VERSION 5.8 ;
BUSBITCHARS "[]" ;
DIVIDERCHAR "/" ;
UNITS
    DATABASE MICRONS 1000 ;
END UNITS

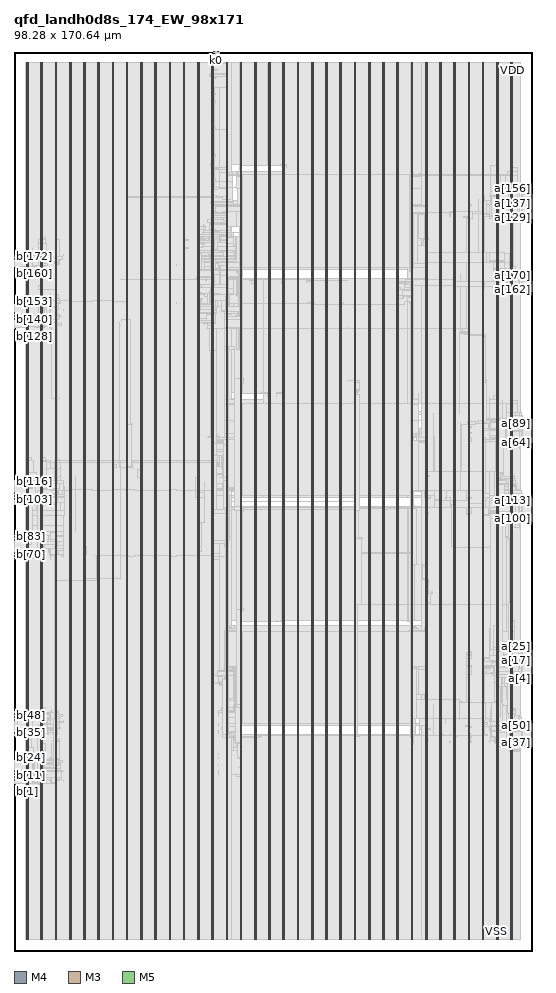
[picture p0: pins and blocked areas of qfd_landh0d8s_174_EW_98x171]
MACRO qfd_landh0d8s_174_EW_98x171
  FOREIGN qfd_landh0d8s_174_EW_98x171 0 0 ;
  CLASS BLOCK ;
  SIZE 98.28 BY 170.64 ;
  PIN a[0]
    DIRECTION INPUT ;
    USE SIGNAL ;
    PORT
      LAYER M4 ;
        RECT  98.196 52.56 98.28 52.584 ;
    END
  END a[0]
  PIN a[100]
    DIRECTION INPUT ;
    USE SIGNAL ;
    PORT
      LAYER M4 ;
        RECT  98.196 81.936 98.28 81.96 ;
    END
  END a[100]
  PIN a[101]
    DIRECTION INPUT ;
    USE SIGNAL ;
    PORT
      LAYER M4 ;
        RECT  98.196 82.08 98.28 82.104 ;
    END
  END a[101]
  PIN a[102]
    DIRECTION INPUT ;
    USE SIGNAL ;
    PORT
      LAYER M4 ;
        RECT  98.196 82.224 98.28 82.248 ;
    END
  END a[102]
  PIN a[103]
    DIRECTION INPUT ;
    USE SIGNAL ;
    PORT
      LAYER M4 ;
        RECT  98.196 82.368 98.28 82.392 ;
    END
  END a[103]
  PIN a[104]
    DIRECTION INPUT ;
    USE SIGNAL ;
    PORT
      LAYER M4 ;
        RECT  98.196 82.512 98.28 82.536 ;
    END
  END a[104]
  PIN a[105]
    DIRECTION INPUT ;
    USE SIGNAL ;
    PORT
      LAYER M4 ;
        RECT  98.196 82.656 98.28 82.68 ;
    END
  END a[105]
  PIN a[106]
    DIRECTION INPUT ;
    USE SIGNAL ;
    PORT
      LAYER M4 ;
        RECT  98.196 82.8 98.28 82.824 ;
    END
  END a[106]
  PIN a[107]
    DIRECTION INPUT ;
    USE SIGNAL ;
    PORT
      LAYER M4 ;
        RECT  98.196 82.944 98.28 82.968 ;
    END
  END a[107]
  PIN a[108]
    DIRECTION INPUT ;
    USE SIGNAL ;
    PORT
      LAYER M4 ;
        RECT  98.196 83.088 98.28 83.112 ;
    END
  END a[108]
  PIN a[109]
    DIRECTION INPUT ;
    USE SIGNAL ;
    PORT
      LAYER M4 ;
        RECT  98.196 83.232 98.28 83.256 ;
    END
  END a[109]
  PIN a[10]
    DIRECTION INPUT ;
    USE SIGNAL ;
    PORT
      LAYER M4 ;
        RECT  98.196 54 98.28 54.024 ;
    END
  END a[10]
  PIN a[110]
    DIRECTION INPUT ;
    USE SIGNAL ;
    PORT
      LAYER M4 ;
        RECT  98.196 83.376 98.28 83.4 ;
    END
  END a[110]
  PIN a[111]
    DIRECTION INPUT ;
    USE SIGNAL ;
    PORT
      LAYER M4 ;
        RECT  98.196 83.52 98.28 83.544 ;
    END
  END a[111]
  PIN a[112]
    DIRECTION INPUT ;
    USE SIGNAL ;
    PORT
      LAYER M4 ;
        RECT  98.196 83.664 98.28 83.688 ;
    END
  END a[112]
  PIN a[113]
    DIRECTION INPUT ;
    USE SIGNAL ;
    PORT
      LAYER M4 ;
        RECT  98.196 83.808 98.28 83.832 ;
    END
  END a[113]
  PIN a[114]
    DIRECTION INPUT ;
    USE SIGNAL ;
    PORT
      LAYER M4 ;
        RECT  98.196 83.952 98.28 83.976 ;
    END
  END a[114]
  PIN a[115]
    DIRECTION INPUT ;
    USE SIGNAL ;
    PORT
      LAYER M4 ;
        RECT  98.196 84.096 98.28 84.12 ;
    END
  END a[115]
  PIN a[116]
    DIRECTION INPUT ;
    USE SIGNAL ;
    PORT
      LAYER M4 ;
        RECT  98.196 84.24 98.28 84.264 ;
    END
  END a[116]
  PIN a[117]
    DIRECTION INPUT ;
    USE SIGNAL ;
    PORT
      LAYER M4 ;
        RECT  98.196 84.384 98.28 84.408 ;
    END
  END a[117]
  PIN a[118]
    DIRECTION INPUT ;
    USE SIGNAL ;
    PORT
      LAYER M4 ;
        RECT  98.196 84.528 98.28 84.552 ;
    END
  END a[118]
  PIN a[119]
    DIRECTION INPUT ;
    USE SIGNAL ;
    PORT
      LAYER M4 ;
        RECT  98.196 84.672 98.28 84.696 ;
    END
  END a[119]
  PIN a[11]
    DIRECTION INPUT ;
    USE SIGNAL ;
    PORT
      LAYER M4 ;
        RECT  98.196 54.144 98.28 54.168 ;
    END
  END a[11]
  PIN a[120]
    DIRECTION INPUT ;
    USE SIGNAL ;
    PORT
      LAYER M4 ;
        RECT  98.196 84.816 98.28 84.84 ;
    END
  END a[120]
  PIN a[121]
    DIRECTION INPUT ;
    USE SIGNAL ;
    PORT
      LAYER M4 ;
        RECT  98.196 84.96 98.28 84.984 ;
    END
  END a[121]
  PIN a[122]
    DIRECTION INPUT ;
    USE SIGNAL ;
    PORT
      LAYER M4 ;
        RECT  98.196 85.104 98.28 85.128 ;
    END
  END a[122]
  PIN a[123]
    DIRECTION INPUT ;
    USE SIGNAL ;
    PORT
      LAYER M4 ;
        RECT  98.196 85.248 98.28 85.272 ;
    END
  END a[123]
  PIN a[124]
    DIRECTION INPUT ;
    USE SIGNAL ;
    PORT
      LAYER M4 ;
        RECT  98.196 85.392 98.28 85.416 ;
    END
  END a[124]
  PIN a[125]
    DIRECTION INPUT ;
    USE SIGNAL ;
    PORT
      LAYER M4 ;
        RECT  98.196 85.536 98.28 85.56 ;
    END
  END a[125]
  PIN a[126]
    DIRECTION INPUT ;
    USE SIGNAL ;
    PORT
      LAYER M4 ;
        RECT  98.196 85.68 98.28 85.704 ;
    END
  END a[126]
  PIN a[127]
    DIRECTION INPUT ;
    USE SIGNAL ;
    PORT
      LAYER M4 ;
        RECT  98.196 85.824 98.28 85.848 ;
    END
  END a[127]
  PIN a[128]
    DIRECTION INPUT ;
    USE SIGNAL ;
    PORT
      LAYER M4 ;
        RECT  98.196 138.96 98.28 138.984 ;
    END
  END a[128]
  PIN a[129]
    DIRECTION INPUT ;
    USE SIGNAL ;
    PORT
      LAYER M4 ;
        RECT  98.196 139.104 98.28 139.128 ;
    END
  END a[129]
  PIN a[12]
    DIRECTION INPUT ;
    USE SIGNAL ;
    PORT
      LAYER M4 ;
        RECT  98.196 54.288 98.28 54.312 ;
    END
  END a[12]
  PIN a[130]
    DIRECTION INPUT ;
    USE SIGNAL ;
    PORT
      LAYER M4 ;
        RECT  98.196 139.248 98.28 139.272 ;
    END
  END a[130]
  PIN a[131]
    DIRECTION INPUT ;
    USE SIGNAL ;
    PORT
      LAYER M4 ;
        RECT  98.196 139.392 98.28 139.416 ;
    END
  END a[131]
  PIN a[132]
    DIRECTION INPUT ;
    USE SIGNAL ;
    PORT
      LAYER M4 ;
        RECT  98.196 139.536 98.28 139.56 ;
    END
  END a[132]
  PIN a[133]
    DIRECTION INPUT ;
    USE SIGNAL ;
    PORT
      LAYER M4 ;
        RECT  98.196 139.68 98.28 139.704 ;
    END
  END a[133]
  PIN a[134]
    DIRECTION INPUT ;
    USE SIGNAL ;
    PORT
      LAYER M4 ;
        RECT  98.196 139.824 98.28 139.848 ;
    END
  END a[134]
  PIN a[135]
    DIRECTION INPUT ;
    USE SIGNAL ;
    PORT
      LAYER M4 ;
        RECT  98.196 139.968 98.28 139.992 ;
    END
  END a[135]
  PIN a[136]
    DIRECTION INPUT ;
    USE SIGNAL ;
    PORT
      LAYER M4 ;
        RECT  98.196 140.112 98.28 140.136 ;
    END
  END a[136]
  PIN a[137]
    DIRECTION INPUT ;
    USE SIGNAL ;
    PORT
      LAYER M4 ;
        RECT  98.196 140.256 98.28 140.28 ;
    END
  END a[137]
  PIN a[138]
    DIRECTION INPUT ;
    USE SIGNAL ;
    PORT
      LAYER M4 ;
        RECT  98.196 140.4 98.28 140.424 ;
    END
  END a[138]
  PIN a[139]
    DIRECTION INPUT ;
    USE SIGNAL ;
    PORT
      LAYER M4 ;
        RECT  98.196 140.544 98.28 140.568 ;
    END
  END a[139]
  PIN a[13]
    DIRECTION INPUT ;
    USE SIGNAL ;
    PORT
      LAYER M4 ;
        RECT  98.196 54.432 98.28 54.456 ;
    END
  END a[13]
  PIN a[140]
    DIRECTION INPUT ;
    USE SIGNAL ;
    PORT
      LAYER M4 ;
        RECT  98.196 140.688 98.28 140.712 ;
    END
  END a[140]
  PIN a[141]
    DIRECTION INPUT ;
    USE SIGNAL ;
    PORT
      LAYER M4 ;
        RECT  98.196 140.832 98.28 140.856 ;
    END
  END a[141]
  PIN a[142]
    DIRECTION INPUT ;
    USE SIGNAL ;
    PORT
      LAYER M4 ;
        RECT  98.196 140.976 98.28 141 ;
    END
  END a[142]
  PIN a[143]
    DIRECTION INPUT ;
    USE SIGNAL ;
    PORT
      LAYER M4 ;
        RECT  98.196 141.12 98.28 141.144 ;
    END
  END a[143]
  PIN a[144]
    DIRECTION INPUT ;
    USE SIGNAL ;
    PORT
      LAYER M4 ;
        RECT  98.196 141.264 98.28 141.288 ;
    END
  END a[144]
  PIN a[145]
    DIRECTION INPUT ;
    USE SIGNAL ;
    PORT
      LAYER M4 ;
        RECT  98.196 141.408 98.28 141.432 ;
    END
  END a[145]
  PIN a[146]
    DIRECTION INPUT ;
    USE SIGNAL ;
    PORT
      LAYER M4 ;
        RECT  98.196 141.552 98.28 141.576 ;
    END
  END a[146]
  PIN a[147]
    DIRECTION INPUT ;
    USE SIGNAL ;
    PORT
      LAYER M4 ;
        RECT  98.196 141.696 98.28 141.72 ;
    END
  END a[147]
  PIN a[148]
    DIRECTION INPUT ;
    USE SIGNAL ;
    PORT
      LAYER M4 ;
        RECT  98.196 141.84 98.28 141.864 ;
    END
  END a[148]
  PIN a[149]
    DIRECTION INPUT ;
    USE SIGNAL ;
    PORT
      LAYER M4 ;
        RECT  98.196 141.984 98.28 142.008 ;
    END
  END a[149]
  PIN a[14]
    DIRECTION INPUT ;
    USE SIGNAL ;
    PORT
      LAYER M4 ;
        RECT  98.196 54.576 98.28 54.6 ;
    END
  END a[14]
  PIN a[150]
    DIRECTION INPUT ;
    USE SIGNAL ;
    PORT
      LAYER M4 ;
        RECT  98.196 142.128 98.28 142.152 ;
    END
  END a[150]
  PIN a[151]
    DIRECTION INPUT ;
    USE SIGNAL ;
    PORT
      LAYER M4 ;
        RECT  98.196 142.272 98.28 142.296 ;
    END
  END a[151]
  PIN a[152]
    DIRECTION INPUT ;
    USE SIGNAL ;
    PORT
      LAYER M4 ;
        RECT  98.196 142.416 98.28 142.44 ;
    END
  END a[152]
  PIN a[153]
    DIRECTION INPUT ;
    USE SIGNAL ;
    PORT
      LAYER M4 ;
        RECT  98.196 142.56 98.28 142.584 ;
    END
  END a[153]
  PIN a[154]
    DIRECTION INPUT ;
    USE SIGNAL ;
    PORT
      LAYER M4 ;
        RECT  98.196 142.704 98.28 142.728 ;
    END
  END a[154]
  PIN a[155]
    DIRECTION INPUT ;
    USE SIGNAL ;
    PORT
      LAYER M4 ;
        RECT  98.196 142.848 98.28 142.872 ;
    END
  END a[155]
  PIN a[156]
    DIRECTION INPUT ;
    USE SIGNAL ;
    PORT
      LAYER M4 ;
        RECT  98.196 142.992 98.28 143.016 ;
    END
  END a[156]
  PIN a[157]
    DIRECTION INPUT ;
    USE SIGNAL ;
    PORT
      LAYER M4 ;
        RECT  98.196 143.136 98.28 143.16 ;
    END
  END a[157]
  PIN a[158]
    DIRECTION INPUT ;
    USE SIGNAL ;
    PORT
      LAYER M4 ;
        RECT  98.196 143.28 98.28 143.304 ;
    END
  END a[158]
  PIN a[159]
    DIRECTION INPUT ;
    USE SIGNAL ;
    PORT
      LAYER M4 ;
        RECT  98.196 143.424 98.28 143.448 ;
    END
  END a[159]
  PIN a[15]
    DIRECTION INPUT ;
    USE SIGNAL ;
    PORT
      LAYER M4 ;
        RECT  98.196 54.72 98.28 54.744 ;
    END
  END a[15]
  PIN a[160]
    DIRECTION INPUT ;
    USE SIGNAL ;
    PORT
      LAYER M4 ;
        RECT  98.196 125.136 98.28 125.16 ;
    END
  END a[160]
  PIN a[161]
    DIRECTION INPUT ;
    USE SIGNAL ;
    PORT
      LAYER M4 ;
        RECT  98.196 125.28 98.28 125.304 ;
    END
  END a[161]
  PIN a[162]
    DIRECTION INPUT ;
    USE SIGNAL ;
    PORT
      LAYER M4 ;
        RECT  98.196 125.424 98.28 125.448 ;
    END
  END a[162]
  PIN a[163]
    DIRECTION INPUT ;
    USE SIGNAL ;
    PORT
      LAYER M4 ;
        RECT  98.196 125.568 98.28 125.592 ;
    END
  END a[163]
  PIN a[164]
    DIRECTION INPUT ;
    USE SIGNAL ;
    PORT
      LAYER M4 ;
        RECT  98.196 125.712 98.28 125.736 ;
    END
  END a[164]
  PIN a[165]
    DIRECTION INPUT ;
    USE SIGNAL ;
    PORT
      LAYER M4 ;
        RECT  98.196 125.856 98.28 125.88 ;
    END
  END a[165]
  PIN a[166]
    DIRECTION INPUT ;
    USE SIGNAL ;
    PORT
      LAYER M4 ;
        RECT  98.196 126 98.28 126.024 ;
    END
  END a[166]
  PIN a[167]
    DIRECTION INPUT ;
    USE SIGNAL ;
    PORT
      LAYER M4 ;
        RECT  98.196 126.144 98.28 126.168 ;
    END
  END a[167]
  PIN a[168]
    DIRECTION INPUT ;
    USE SIGNAL ;
    PORT
      LAYER M4 ;
        RECT  98.196 126.288 98.28 126.312 ;
    END
  END a[168]
  PIN a[169]
    DIRECTION INPUT ;
    USE SIGNAL ;
    PORT
      LAYER M4 ;
        RECT  98.196 126.432 98.28 126.456 ;
    END
  END a[169]
  PIN a[16]
    DIRECTION INPUT ;
    USE SIGNAL ;
    PORT
      LAYER M4 ;
        RECT  98.196 54.864 98.28 54.888 ;
    END
  END a[16]
  PIN a[170]
    DIRECTION INPUT ;
    USE SIGNAL ;
    PORT
      LAYER M4 ;
        RECT  98.196 126.576 98.28 126.6 ;
    END
  END a[170]
  PIN a[171]
    DIRECTION INPUT ;
    USE SIGNAL ;
    PORT
      LAYER M4 ;
        RECT  98.196 126.72 98.28 126.744 ;
    END
  END a[171]
  PIN a[172]
    DIRECTION INPUT ;
    USE SIGNAL ;
    PORT
      LAYER M4 ;
        RECT  98.196 126.864 98.28 126.888 ;
    END
  END a[172]
  PIN a[173]
    DIRECTION INPUT ;
    USE SIGNAL ;
    PORT
      LAYER M4 ;
        RECT  98.196 127.008 98.28 127.032 ;
    END
  END a[173]
  PIN a[17]
    DIRECTION INPUT ;
    USE SIGNAL ;
    PORT
      LAYER M4 ;
        RECT  98.196 55.008 98.28 55.032 ;
    END
  END a[17]
  PIN a[18]
    DIRECTION INPUT ;
    USE SIGNAL ;
    PORT
      LAYER M4 ;
        RECT  98.196 55.152 98.28 55.176 ;
    END
  END a[18]
  PIN a[19]
    DIRECTION INPUT ;
    USE SIGNAL ;
    PORT
      LAYER M4 ;
        RECT  98.196 55.296 98.28 55.32 ;
    END
  END a[19]
  PIN a[1]
    DIRECTION INPUT ;
    USE SIGNAL ;
    PORT
      LAYER M4 ;
        RECT  98.196 52.704 98.28 52.728 ;
    END
  END a[1]
  PIN a[20]
    DIRECTION INPUT ;
    USE SIGNAL ;
    PORT
      LAYER M4 ;
        RECT  98.196 55.44 98.28 55.464 ;
    END
  END a[20]
  PIN a[21]
    DIRECTION INPUT ;
    USE SIGNAL ;
    PORT
      LAYER M4 ;
        RECT  98.196 55.584 98.28 55.608 ;
    END
  END a[21]
  PIN a[22]
    DIRECTION INPUT ;
    USE SIGNAL ;
    PORT
      LAYER M4 ;
        RECT  98.196 55.728 98.28 55.752 ;
    END
  END a[22]
  PIN a[23]
    DIRECTION INPUT ;
    USE SIGNAL ;
    PORT
      LAYER M4 ;
        RECT  98.196 55.872 98.28 55.896 ;
    END
  END a[23]
  PIN a[24]
    DIRECTION INPUT ;
    USE SIGNAL ;
    PORT
      LAYER M4 ;
        RECT  98.196 56.016 98.28 56.04 ;
    END
  END a[24]
  PIN a[25]
    DIRECTION INPUT ;
    USE SIGNAL ;
    PORT
      LAYER M4 ;
        RECT  98.196 56.16 98.28 56.184 ;
    END
  END a[25]
  PIN a[26]
    DIRECTION INPUT ;
    USE SIGNAL ;
    PORT
      LAYER M4 ;
        RECT  98.196 56.304 98.28 56.328 ;
    END
  END a[26]
  PIN a[27]
    DIRECTION INPUT ;
    USE SIGNAL ;
    PORT
      LAYER M4 ;
        RECT  98.196 56.448 98.28 56.472 ;
    END
  END a[27]
  PIN a[28]
    DIRECTION INPUT ;
    USE SIGNAL ;
    PORT
      LAYER M4 ;
        RECT  98.196 56.592 98.28 56.616 ;
    END
  END a[28]
  PIN a[29]
    DIRECTION INPUT ;
    USE SIGNAL ;
    PORT
      LAYER M4 ;
        RECT  98.196 56.736 98.28 56.76 ;
    END
  END a[29]
  PIN a[2]
    DIRECTION INPUT ;
    USE SIGNAL ;
    PORT
      LAYER M4 ;
        RECT  98.196 52.848 98.28 52.872 ;
    END
  END a[2]
  PIN a[30]
    DIRECTION INPUT ;
    USE SIGNAL ;
    PORT
      LAYER M4 ;
        RECT  98.196 56.88 98.28 56.904 ;
    END
  END a[30]
  PIN a[31]
    DIRECTION INPUT ;
    USE SIGNAL ;
    PORT
      LAYER M4 ;
        RECT  98.196 57.024 98.28 57.048 ;
    END
  END a[31]
  PIN a[32]
    DIRECTION INPUT ;
    USE SIGNAL ;
    PORT
      LAYER M4 ;
        RECT  98.196 38.736 98.28 38.76 ;
    END
  END a[32]
  PIN a[33]
    DIRECTION INPUT ;
    USE SIGNAL ;
    PORT
      LAYER M4 ;
        RECT  98.196 38.88 98.28 38.904 ;
    END
  END a[33]
  PIN a[34]
    DIRECTION INPUT ;
    USE SIGNAL ;
    PORT
      LAYER M4 ;
        RECT  98.196 39.024 98.28 39.048 ;
    END
  END a[34]
  PIN a[35]
    DIRECTION INPUT ;
    USE SIGNAL ;
    PORT
      LAYER M4 ;
        RECT  98.196 39.168 98.28 39.192 ;
    END
  END a[35]
  PIN a[36]
    DIRECTION INPUT ;
    USE SIGNAL ;
    PORT
      LAYER M4 ;
        RECT  98.196 39.312 98.28 39.336 ;
    END
  END a[36]
  PIN a[37]
    DIRECTION INPUT ;
    USE SIGNAL ;
    PORT
      LAYER M4 ;
        RECT  98.196 39.456 98.28 39.48 ;
    END
  END a[37]
  PIN a[38]
    DIRECTION INPUT ;
    USE SIGNAL ;
    PORT
      LAYER M4 ;
        RECT  98.196 39.6 98.28 39.624 ;
    END
  END a[38]
  PIN a[39]
    DIRECTION INPUT ;
    USE SIGNAL ;
    PORT
      LAYER M4 ;
        RECT  98.196 39.744 98.28 39.768 ;
    END
  END a[39]
  PIN a[3]
    DIRECTION INPUT ;
    USE SIGNAL ;
    PORT
      LAYER M4 ;
        RECT  98.196 52.992 98.28 53.016 ;
    END
  END a[3]
  PIN a[40]
    DIRECTION INPUT ;
    USE SIGNAL ;
    PORT
      LAYER M4 ;
        RECT  98.196 39.888 98.28 39.912 ;
    END
  END a[40]
  PIN a[41]
    DIRECTION INPUT ;
    USE SIGNAL ;
    PORT
      LAYER M4 ;
        RECT  98.196 40.032 98.28 40.056 ;
    END
  END a[41]
  PIN a[42]
    DIRECTION INPUT ;
    USE SIGNAL ;
    PORT
      LAYER M4 ;
        RECT  98.196 40.176 98.28 40.2 ;
    END
  END a[42]
  PIN a[43]
    DIRECTION INPUT ;
    USE SIGNAL ;
    PORT
      LAYER M4 ;
        RECT  98.196 40.32 98.28 40.344 ;
    END
  END a[43]
  PIN a[44]
    DIRECTION INPUT ;
    USE SIGNAL ;
    PORT
      LAYER M4 ;
        RECT  98.196 40.464 98.28 40.488 ;
    END
  END a[44]
  PIN a[45]
    DIRECTION INPUT ;
    USE SIGNAL ;
    PORT
      LAYER M4 ;
        RECT  98.196 40.608 98.28 40.632 ;
    END
  END a[45]
  PIN a[46]
    DIRECTION INPUT ;
    USE SIGNAL ;
    PORT
      LAYER M4 ;
        RECT  98.196 40.752 98.28 40.776 ;
    END
  END a[46]
  PIN a[47]
    DIRECTION INPUT ;
    USE SIGNAL ;
    PORT
      LAYER M4 ;
        RECT  98.196 40.896 98.28 40.92 ;
    END
  END a[47]
  PIN a[48]
    DIRECTION INPUT ;
    USE SIGNAL ;
    PORT
      LAYER M4 ;
        RECT  98.196 41.04 98.28 41.064 ;
    END
  END a[48]
  PIN a[49]
    DIRECTION INPUT ;
    USE SIGNAL ;
    PORT
      LAYER M4 ;
        RECT  98.196 41.184 98.28 41.208 ;
    END
  END a[49]
  PIN a[4]
    DIRECTION INPUT ;
    USE SIGNAL ;
    PORT
      LAYER M4 ;
        RECT  98.196 53.136 98.28 53.16 ;
    END
  END a[4]
  PIN a[50]
    DIRECTION INPUT ;
    USE SIGNAL ;
    PORT
      LAYER M4 ;
        RECT  98.196 41.328 98.28 41.352 ;
    END
  END a[50]
  PIN a[51]
    DIRECTION INPUT ;
    USE SIGNAL ;
    PORT
      LAYER M4 ;
        RECT  98.196 41.472 98.28 41.496 ;
    END
  END a[51]
  PIN a[52]
    DIRECTION INPUT ;
    USE SIGNAL ;
    PORT
      LAYER M4 ;
        RECT  98.196 41.616 98.28 41.64 ;
    END
  END a[52]
  PIN a[53]
    DIRECTION INPUT ;
    USE SIGNAL ;
    PORT
      LAYER M4 ;
        RECT  98.196 41.76 98.28 41.784 ;
    END
  END a[53]
  PIN a[54]
    DIRECTION INPUT ;
    USE SIGNAL ;
    PORT
      LAYER M4 ;
        RECT  98.196 41.904 98.28 41.928 ;
    END
  END a[54]
  PIN a[55]
    DIRECTION INPUT ;
    USE SIGNAL ;
    PORT
      LAYER M4 ;
        RECT  98.196 42.048 98.28 42.072 ;
    END
  END a[55]
  PIN a[56]
    DIRECTION INPUT ;
    USE SIGNAL ;
    PORT
      LAYER M4 ;
        RECT  98.196 42.192 98.28 42.216 ;
    END
  END a[56]
  PIN a[57]
    DIRECTION INPUT ;
    USE SIGNAL ;
    PORT
      LAYER M4 ;
        RECT  98.196 42.336 98.28 42.36 ;
    END
  END a[57]
  PIN a[58]
    DIRECTION INPUT ;
    USE SIGNAL ;
    PORT
      LAYER M4 ;
        RECT  98.196 42.48 98.28 42.504 ;
    END
  END a[58]
  PIN a[59]
    DIRECTION INPUT ;
    USE SIGNAL ;
    PORT
      LAYER M4 ;
        RECT  98.196 42.624 98.28 42.648 ;
    END
  END a[59]
  PIN a[5]
    DIRECTION INPUT ;
    USE SIGNAL ;
    PORT
      LAYER M4 ;
        RECT  98.196 53.28 98.28 53.304 ;
    END
  END a[5]
  PIN a[60]
    DIRECTION INPUT ;
    USE SIGNAL ;
    PORT
      LAYER M4 ;
        RECT  98.196 42.768 98.28 42.792 ;
    END
  END a[60]
  PIN a[61]
    DIRECTION INPUT ;
    USE SIGNAL ;
    PORT
      LAYER M4 ;
        RECT  98.196 42.912 98.28 42.936 ;
    END
  END a[61]
  PIN a[62]
    DIRECTION INPUT ;
    USE SIGNAL ;
    PORT
      LAYER M4 ;
        RECT  98.196 43.056 98.28 43.08 ;
    END
  END a[62]
  PIN a[63]
    DIRECTION INPUT ;
    USE SIGNAL ;
    PORT
      LAYER M4 ;
        RECT  98.196 43.2 98.28 43.224 ;
    END
  END a[63]
  PIN a[64]
    DIRECTION INPUT ;
    USE SIGNAL ;
    PORT
      LAYER M4 ;
        RECT  98.196 96.336 98.28 96.36 ;
    END
  END a[64]
  PIN a[65]
    DIRECTION INPUT ;
    USE SIGNAL ;
    PORT
      LAYER M4 ;
        RECT  98.196 96.48 98.28 96.504 ;
    END
  END a[65]
  PIN a[66]
    DIRECTION INPUT ;
    USE SIGNAL ;
    PORT
      LAYER M4 ;
        RECT  98.196 96.624 98.28 96.648 ;
    END
  END a[66]
  PIN a[67]
    DIRECTION INPUT ;
    USE SIGNAL ;
    PORT
      LAYER M4 ;
        RECT  98.196 96.768 98.28 96.792 ;
    END
  END a[67]
  PIN a[68]
    DIRECTION INPUT ;
    USE SIGNAL ;
    PORT
      LAYER M4 ;
        RECT  98.196 96.912 98.28 96.936 ;
    END
  END a[68]
  PIN a[69]
    DIRECTION INPUT ;
    USE SIGNAL ;
    PORT
      LAYER M4 ;
        RECT  98.196 97.056 98.28 97.08 ;
    END
  END a[69]
  PIN a[6]
    DIRECTION INPUT ;
    USE SIGNAL ;
    PORT
      LAYER M4 ;
        RECT  98.196 53.424 98.28 53.448 ;
    END
  END a[6]
  PIN a[70]
    DIRECTION INPUT ;
    USE SIGNAL ;
    PORT
      LAYER M4 ;
        RECT  98.196 97.2 98.28 97.224 ;
    END
  END a[70]
  PIN a[71]
    DIRECTION INPUT ;
    USE SIGNAL ;
    PORT
      LAYER M4 ;
        RECT  98.196 97.344 98.28 97.368 ;
    END
  END a[71]
  PIN a[72]
    DIRECTION INPUT ;
    USE SIGNAL ;
    PORT
      LAYER M4 ;
        RECT  98.196 97.488 98.28 97.512 ;
    END
  END a[72]
  PIN a[73]
    DIRECTION INPUT ;
    USE SIGNAL ;
    PORT
      LAYER M4 ;
        RECT  98.196 97.632 98.28 97.656 ;
    END
  END a[73]
  PIN a[74]
    DIRECTION INPUT ;
    USE SIGNAL ;
    PORT
      LAYER M4 ;
        RECT  98.196 97.776 98.28 97.8 ;
    END
  END a[74]
  PIN a[75]
    DIRECTION INPUT ;
    USE SIGNAL ;
    PORT
      LAYER M4 ;
        RECT  98.196 97.92 98.28 97.944 ;
    END
  END a[75]
  PIN a[76]
    DIRECTION INPUT ;
    USE SIGNAL ;
    PORT
      LAYER M4 ;
        RECT  98.196 98.064 98.28 98.088 ;
    END
  END a[76]
  PIN a[77]
    DIRECTION INPUT ;
    USE SIGNAL ;
    PORT
      LAYER M4 ;
        RECT  98.196 98.208 98.28 98.232 ;
    END
  END a[77]
  PIN a[78]
    DIRECTION INPUT ;
    USE SIGNAL ;
    PORT
      LAYER M4 ;
        RECT  98.196 98.352 98.28 98.376 ;
    END
  END a[78]
  PIN a[79]
    DIRECTION INPUT ;
    USE SIGNAL ;
    PORT
      LAYER M4 ;
        RECT  98.196 98.496 98.28 98.52 ;
    END
  END a[79]
  PIN a[7]
    DIRECTION INPUT ;
    USE SIGNAL ;
    PORT
      LAYER M4 ;
        RECT  98.196 53.568 98.28 53.592 ;
    END
  END a[7]
  PIN a[80]
    DIRECTION INPUT ;
    USE SIGNAL ;
    PORT
      LAYER M4 ;
        RECT  98.196 98.64 98.28 98.664 ;
    END
  END a[80]
  PIN a[81]
    DIRECTION INPUT ;
    USE SIGNAL ;
    PORT
      LAYER M4 ;
        RECT  98.196 98.784 98.28 98.808 ;
    END
  END a[81]
  PIN a[82]
    DIRECTION INPUT ;
    USE SIGNAL ;
    PORT
      LAYER M4 ;
        RECT  98.196 98.928 98.28 98.952 ;
    END
  END a[82]
  PIN a[83]
    DIRECTION INPUT ;
    USE SIGNAL ;
    PORT
      LAYER M4 ;
        RECT  98.196 99.072 98.28 99.096 ;
    END
  END a[83]
  PIN a[84]
    DIRECTION INPUT ;
    USE SIGNAL ;
    PORT
      LAYER M4 ;
        RECT  98.196 99.216 98.28 99.24 ;
    END
  END a[84]
  PIN a[85]
    DIRECTION INPUT ;
    USE SIGNAL ;
    PORT
      LAYER M4 ;
        RECT  98.196 99.36 98.28 99.384 ;
    END
  END a[85]
  PIN a[86]
    DIRECTION INPUT ;
    USE SIGNAL ;
    PORT
      LAYER M4 ;
        RECT  98.196 99.504 98.28 99.528 ;
    END
  END a[86]
  PIN a[87]
    DIRECTION INPUT ;
    USE SIGNAL ;
    PORT
      LAYER M4 ;
        RECT  98.196 99.648 98.28 99.672 ;
    END
  END a[87]
  PIN a[88]
    DIRECTION INPUT ;
    USE SIGNAL ;
    PORT
      LAYER M4 ;
        RECT  98.196 99.792 98.28 99.816 ;
    END
  END a[88]
  PIN a[89]
    DIRECTION INPUT ;
    USE SIGNAL ;
    PORT
      LAYER M4 ;
        RECT  98.196 99.936 98.28 99.96 ;
    END
  END a[89]
  PIN a[8]
    DIRECTION INPUT ;
    USE SIGNAL ;
    PORT
      LAYER M4 ;
        RECT  98.196 53.712 98.28 53.736 ;
    END
  END a[8]
  PIN a[90]
    DIRECTION INPUT ;
    USE SIGNAL ;
    PORT
      LAYER M4 ;
        RECT  98.196 100.08 98.28 100.104 ;
    END
  END a[90]
  PIN a[91]
    DIRECTION INPUT ;
    USE SIGNAL ;
    PORT
      LAYER M4 ;
        RECT  98.196 100.224 98.28 100.248 ;
    END
  END a[91]
  PIN a[92]
    DIRECTION INPUT ;
    USE SIGNAL ;
    PORT
      LAYER M4 ;
        RECT  98.196 100.368 98.28 100.392 ;
    END
  END a[92]
  PIN a[93]
    DIRECTION INPUT ;
    USE SIGNAL ;
    PORT
      LAYER M4 ;
        RECT  98.196 100.512 98.28 100.536 ;
    END
  END a[93]
  PIN a[94]
    DIRECTION INPUT ;
    USE SIGNAL ;
    PORT
      LAYER M4 ;
        RECT  98.196 100.656 98.28 100.68 ;
    END
  END a[94]
  PIN a[95]
    DIRECTION INPUT ;
    USE SIGNAL ;
    PORT
      LAYER M4 ;
        RECT  98.196 100.8 98.28 100.824 ;
    END
  END a[95]
  PIN a[96]
    DIRECTION INPUT ;
    USE SIGNAL ;
    PORT
      LAYER M4 ;
        RECT  98.196 81.36 98.28 81.384 ;
    END
  END a[96]
  PIN a[97]
    DIRECTION INPUT ;
    USE SIGNAL ;
    PORT
      LAYER M4 ;
        RECT  98.196 81.504 98.28 81.528 ;
    END
  END a[97]
  PIN a[98]
    DIRECTION INPUT ;
    USE SIGNAL ;
    PORT
      LAYER M4 ;
        RECT  98.196 81.648 98.28 81.672 ;
    END
  END a[98]
  PIN a[99]
    DIRECTION INPUT ;
    USE SIGNAL ;
    PORT
      LAYER M4 ;
        RECT  98.196 81.792 98.28 81.816 ;
    END
  END a[99]
  PIN a[9]
    DIRECTION INPUT ;
    USE SIGNAL ;
    PORT
      LAYER M4 ;
        RECT  98.196 53.856 98.28 53.88 ;
    END
  END a[9]
  PIN b[0]
    DIRECTION OUTPUT ;
    USE SIGNAL ;
    PORT
      LAYER M4 ;
        RECT  0 31.68 0.084 31.704 ;
    END
  END b[0]
  PIN b[100]
    DIRECTION OUTPUT ;
    USE SIGNAL ;
    PORT
      LAYER M4 ;
        RECT  0 85.248 0.084 85.272 ;
    END
  END b[100]
  PIN b[101]
    DIRECTION OUTPUT ;
    USE SIGNAL ;
    PORT
      LAYER M4 ;
        RECT  0 85.392 0.084 85.416 ;
    END
  END b[101]
  PIN b[102]
    DIRECTION OUTPUT ;
    USE SIGNAL ;
    PORT
      LAYER M4 ;
        RECT  0 85.536 0.084 85.56 ;
    END
  END b[102]
  PIN b[103]
    DIRECTION OUTPUT ;
    USE SIGNAL ;
    PORT
      LAYER M4 ;
        RECT  0 85.68 0.084 85.704 ;
    END
  END b[103]
  PIN b[104]
    DIRECTION OUTPUT ;
    USE SIGNAL ;
    PORT
      LAYER M4 ;
        RECT  0 85.824 0.084 85.848 ;
    END
  END b[104]
  PIN b[105]
    DIRECTION OUTPUT ;
    USE SIGNAL ;
    PORT
      LAYER M4 ;
        RECT  0 85.968 0.084 85.992 ;
    END
  END b[105]
  PIN b[106]
    DIRECTION OUTPUT ;
    USE SIGNAL ;
    PORT
      LAYER M4 ;
        RECT  0 86.112 0.084 86.136 ;
    END
  END b[106]
  PIN b[107]
    DIRECTION OUTPUT ;
    USE SIGNAL ;
    PORT
      LAYER M4 ;
        RECT  0 86.256 0.084 86.28 ;
    END
  END b[107]
  PIN b[108]
    DIRECTION OUTPUT ;
    USE SIGNAL ;
    PORT
      LAYER M4 ;
        RECT  0 86.4 0.084 86.424 ;
    END
  END b[108]
  PIN b[109]
    DIRECTION OUTPUT ;
    USE SIGNAL ;
    PORT
      LAYER M4 ;
        RECT  0 86.544 0.084 86.568 ;
    END
  END b[109]
  PIN b[10]
    DIRECTION OUTPUT ;
    USE SIGNAL ;
    PORT
      LAYER M4 ;
        RECT  0 33.12 0.084 33.144 ;
    END
  END b[10]
  PIN b[110]
    DIRECTION OUTPUT ;
    USE SIGNAL ;
    PORT
      LAYER M4 ;
        RECT  0 86.688 0.084 86.712 ;
    END
  END b[110]
  PIN b[111]
    DIRECTION OUTPUT ;
    USE SIGNAL ;
    PORT
      LAYER M4 ;
        RECT  0 86.832 0.084 86.856 ;
    END
  END b[111]
  PIN b[112]
    DIRECTION OUTPUT ;
    USE SIGNAL ;
    PORT
      LAYER M4 ;
        RECT  0 86.976 0.084 87 ;
    END
  END b[112]
  PIN b[113]
    DIRECTION OUTPUT ;
    USE SIGNAL ;
    PORT
      LAYER M4 ;
        RECT  0 87.12 0.084 87.144 ;
    END
  END b[113]
  PIN b[114]
    DIRECTION OUTPUT ;
    USE SIGNAL ;
    PORT
      LAYER M4 ;
        RECT  0 87.264 0.084 87.288 ;
    END
  END b[114]
  PIN b[115]
    DIRECTION OUTPUT ;
    USE SIGNAL ;
    PORT
      LAYER M4 ;
        RECT  0 87.408 0.084 87.432 ;
    END
  END b[115]
  PIN b[116]
    DIRECTION OUTPUT ;
    USE SIGNAL ;
    PORT
      LAYER M4 ;
        RECT  0 87.552 0.084 87.576 ;
    END
  END b[116]
  PIN b[117]
    DIRECTION OUTPUT ;
    USE SIGNAL ;
    PORT
      LAYER M4 ;
        RECT  0 87.696 0.084 87.72 ;
    END
  END b[117]
  PIN b[118]
    DIRECTION OUTPUT ;
    USE SIGNAL ;
    PORT
      LAYER M4 ;
        RECT  0 87.84 0.084 87.864 ;
    END
  END b[118]
  PIN b[119]
    DIRECTION OUTPUT ;
    USE SIGNAL ;
    PORT
      LAYER M4 ;
        RECT  0 87.984 0.084 88.008 ;
    END
  END b[119]
  PIN b[11]
    DIRECTION OUTPUT ;
    USE SIGNAL ;
    PORT
      LAYER M4 ;
        RECT  0 33.264 0.084 33.288 ;
    END
  END b[11]
  PIN b[120]
    DIRECTION OUTPUT ;
    USE SIGNAL ;
    PORT
      LAYER M4 ;
        RECT  0 88.128 0.084 88.152 ;
    END
  END b[120]
  PIN b[121]
    DIRECTION OUTPUT ;
    USE SIGNAL ;
    PORT
      LAYER M4 ;
        RECT  0 88.272 0.084 88.296 ;
    END
  END b[121]
  PIN b[122]
    DIRECTION OUTPUT ;
    USE SIGNAL ;
    PORT
      LAYER M4 ;
        RECT  0 88.416 0.084 88.44 ;
    END
  END b[122]
  PIN b[123]
    DIRECTION OUTPUT ;
    USE SIGNAL ;
    PORT
      LAYER M4 ;
        RECT  0 88.56 0.084 88.584 ;
    END
  END b[123]
  PIN b[124]
    DIRECTION OUTPUT ;
    USE SIGNAL ;
    PORT
      LAYER M4 ;
        RECT  0 88.704 0.084 88.728 ;
    END
  END b[124]
  PIN b[125]
    DIRECTION OUTPUT ;
    USE SIGNAL ;
    PORT
      LAYER M4 ;
        RECT  0 88.848 0.084 88.872 ;
    END
  END b[125]
  PIN b[126]
    DIRECTION OUTPUT ;
    USE SIGNAL ;
    PORT
      LAYER M4 ;
        RECT  0 88.992 0.084 89.016 ;
    END
  END b[126]
  PIN b[127]
    DIRECTION OUTPUT ;
    USE SIGNAL ;
    PORT
      LAYER M4 ;
        RECT  0 89.136 0.084 89.16 ;
    END
  END b[127]
  PIN b[128]
    DIRECTION OUTPUT ;
    USE SIGNAL ;
    PORT
      LAYER M4 ;
        RECT  0 118.08 0.084 118.104 ;
    END
  END b[128]
  PIN b[129]
    DIRECTION OUTPUT ;
    USE SIGNAL ;
    PORT
      LAYER M4 ;
        RECT  0 118.224 0.084 118.248 ;
    END
  END b[129]
  PIN b[12]
    DIRECTION OUTPUT ;
    USE SIGNAL ;
    PORT
      LAYER M4 ;
        RECT  0 33.408 0.084 33.432 ;
    END
  END b[12]
  PIN b[130]
    DIRECTION OUTPUT ;
    USE SIGNAL ;
    PORT
      LAYER M4 ;
        RECT  0 118.368 0.084 118.392 ;
    END
  END b[130]
  PIN b[131]
    DIRECTION OUTPUT ;
    USE SIGNAL ;
    PORT
      LAYER M4 ;
        RECT  0 118.512 0.084 118.536 ;
    END
  END b[131]
  PIN b[132]
    DIRECTION OUTPUT ;
    USE SIGNAL ;
    PORT
      LAYER M4 ;
        RECT  0 118.656 0.084 118.68 ;
    END
  END b[132]
  PIN b[133]
    DIRECTION OUTPUT ;
    USE SIGNAL ;
    PORT
      LAYER M4 ;
        RECT  0 118.8 0.084 118.824 ;
    END
  END b[133]
  PIN b[134]
    DIRECTION OUTPUT ;
    USE SIGNAL ;
    PORT
      LAYER M4 ;
        RECT  0 118.944 0.084 118.968 ;
    END
  END b[134]
  PIN b[135]
    DIRECTION OUTPUT ;
    USE SIGNAL ;
    PORT
      LAYER M4 ;
        RECT  0 119.088 0.084 119.112 ;
    END
  END b[135]
  PIN b[136]
    DIRECTION OUTPUT ;
    USE SIGNAL ;
    PORT
      LAYER M4 ;
        RECT  0 119.232 0.084 119.256 ;
    END
  END b[136]
  PIN b[137]
    DIRECTION OUTPUT ;
    USE SIGNAL ;
    PORT
      LAYER M4 ;
        RECT  0 119.376 0.084 119.4 ;
    END
  END b[137]
  PIN b[138]
    DIRECTION OUTPUT ;
    USE SIGNAL ;
    PORT
      LAYER M4 ;
        RECT  0 119.52 0.084 119.544 ;
    END
  END b[138]
  PIN b[139]
    DIRECTION OUTPUT ;
    USE SIGNAL ;
    PORT
      LAYER M4 ;
        RECT  0 119.664 0.084 119.688 ;
    END
  END b[139]
  PIN b[13]
    DIRECTION OUTPUT ;
    USE SIGNAL ;
    PORT
      LAYER M4 ;
        RECT  0 33.552 0.084 33.576 ;
    END
  END b[13]
  PIN b[140]
    DIRECTION OUTPUT ;
    USE SIGNAL ;
    PORT
      LAYER M4 ;
        RECT  0 119.808 0.084 119.832 ;
    END
  END b[140]
  PIN b[141]
    DIRECTION OUTPUT ;
    USE SIGNAL ;
    PORT
      LAYER M4 ;
        RECT  0 119.952 0.084 119.976 ;
    END
  END b[141]
  PIN b[142]
    DIRECTION OUTPUT ;
    USE SIGNAL ;
    PORT
      LAYER M4 ;
        RECT  0 120.096 0.084 120.12 ;
    END
  END b[142]
  PIN b[143]
    DIRECTION OUTPUT ;
    USE SIGNAL ;
    PORT
      LAYER M4 ;
        RECT  0 120.24 0.084 120.264 ;
    END
  END b[143]
  PIN b[144]
    DIRECTION OUTPUT ;
    USE SIGNAL ;
    PORT
      LAYER M4 ;
        RECT  0 120.384 0.084 120.408 ;
    END
  END b[144]
  PIN b[145]
    DIRECTION OUTPUT ;
    USE SIGNAL ;
    PORT
      LAYER M4 ;
        RECT  0 120.528 0.084 120.552 ;
    END
  END b[145]
  PIN b[146]
    DIRECTION OUTPUT ;
    USE SIGNAL ;
    PORT
      LAYER M4 ;
        RECT  0 120.672 0.084 120.696 ;
    END
  END b[146]
  PIN b[147]
    DIRECTION OUTPUT ;
    USE SIGNAL ;
    PORT
      LAYER M4 ;
        RECT  0 120.816 0.084 120.84 ;
    END
  END b[147]
  PIN b[148]
    DIRECTION OUTPUT ;
    USE SIGNAL ;
    PORT
      LAYER M4 ;
        RECT  0 120.96 0.084 120.984 ;
    END
  END b[148]
  PIN b[149]
    DIRECTION OUTPUT ;
    USE SIGNAL ;
    PORT
      LAYER M4 ;
        RECT  0 121.104 0.084 121.128 ;
    END
  END b[149]
  PIN b[14]
    DIRECTION OUTPUT ;
    USE SIGNAL ;
    PORT
      LAYER M4 ;
        RECT  0 33.696 0.084 33.72 ;
    END
  END b[14]
  PIN b[150]
    DIRECTION OUTPUT ;
    USE SIGNAL ;
    PORT
      LAYER M4 ;
        RECT  0 121.248 0.084 121.272 ;
    END
  END b[150]
  PIN b[151]
    DIRECTION OUTPUT ;
    USE SIGNAL ;
    PORT
      LAYER M4 ;
        RECT  0 121.392 0.084 121.416 ;
    END
  END b[151]
  PIN b[152]
    DIRECTION OUTPUT ;
    USE SIGNAL ;
    PORT
      LAYER M4 ;
        RECT  0 121.536 0.084 121.56 ;
    END
  END b[152]
  PIN b[153]
    DIRECTION OUTPUT ;
    USE SIGNAL ;
    PORT
      LAYER M4 ;
        RECT  0 121.68 0.084 121.704 ;
    END
  END b[153]
  PIN b[154]
    DIRECTION OUTPUT ;
    USE SIGNAL ;
    PORT
      LAYER M4 ;
        RECT  0 121.824 0.084 121.848 ;
    END
  END b[154]
  PIN b[155]
    DIRECTION OUTPUT ;
    USE SIGNAL ;
    PORT
      LAYER M4 ;
        RECT  0 121.968 0.084 121.992 ;
    END
  END b[155]
  PIN b[156]
    DIRECTION OUTPUT ;
    USE SIGNAL ;
    PORT
      LAYER M4 ;
        RECT  0 122.112 0.084 122.136 ;
    END
  END b[156]
  PIN b[157]
    DIRECTION OUTPUT ;
    USE SIGNAL ;
    PORT
      LAYER M4 ;
        RECT  0 122.256 0.084 122.28 ;
    END
  END b[157]
  PIN b[158]
    DIRECTION OUTPUT ;
    USE SIGNAL ;
    PORT
      LAYER M4 ;
        RECT  0 122.4 0.084 122.424 ;
    END
  END b[158]
  PIN b[159]
    DIRECTION OUTPUT ;
    USE SIGNAL ;
    PORT
      LAYER M4 ;
        RECT  0 122.544 0.084 122.568 ;
    END
  END b[159]
  PIN b[15]
    DIRECTION OUTPUT ;
    USE SIGNAL ;
    PORT
      LAYER M4 ;
        RECT  0 33.84 0.084 33.864 ;
    END
  END b[15]
  PIN b[160]
    DIRECTION OUTPUT ;
    USE SIGNAL ;
    PORT
      LAYER M4 ;
        RECT  0 129.888 0.084 129.912 ;
    END
  END b[160]
  PIN b[161]
    DIRECTION OUTPUT ;
    USE SIGNAL ;
    PORT
      LAYER M4 ;
        RECT  0 130.032 0.084 130.056 ;
    END
  END b[161]
  PIN b[162]
    DIRECTION OUTPUT ;
    USE SIGNAL ;
    PORT
      LAYER M4 ;
        RECT  0 130.176 0.084 130.2 ;
    END
  END b[162]
  PIN b[163]
    DIRECTION OUTPUT ;
    USE SIGNAL ;
    PORT
      LAYER M4 ;
        RECT  0 130.32 0.084 130.344 ;
    END
  END b[163]
  PIN b[164]
    DIRECTION OUTPUT ;
    USE SIGNAL ;
    PORT
      LAYER M4 ;
        RECT  0 130.464 0.084 130.488 ;
    END
  END b[164]
  PIN b[165]
    DIRECTION OUTPUT ;
    USE SIGNAL ;
    PORT
      LAYER M4 ;
        RECT  0 130.608 0.084 130.632 ;
    END
  END b[165]
  PIN b[166]
    DIRECTION OUTPUT ;
    USE SIGNAL ;
    PORT
      LAYER M4 ;
        RECT  0 130.752 0.084 130.776 ;
    END
  END b[166]
  PIN b[167]
    DIRECTION OUTPUT ;
    USE SIGNAL ;
    PORT
      LAYER M4 ;
        RECT  0 130.896 0.084 130.92 ;
    END
  END b[167]
  PIN b[168]
    DIRECTION OUTPUT ;
    USE SIGNAL ;
    PORT
      LAYER M4 ;
        RECT  0 131.04 0.084 131.064 ;
    END
  END b[168]
  PIN b[169]
    DIRECTION OUTPUT ;
    USE SIGNAL ;
    PORT
      LAYER M4 ;
        RECT  0 131.184 0.084 131.208 ;
    END
  END b[169]
  PIN b[16]
    DIRECTION OUTPUT ;
    USE SIGNAL ;
    PORT
      LAYER M4 ;
        RECT  0 33.984 0.084 34.008 ;
    END
  END b[16]
  PIN b[170]
    DIRECTION OUTPUT ;
    USE SIGNAL ;
    PORT
      LAYER M4 ;
        RECT  0 131.328 0.084 131.352 ;
    END
  END b[170]
  PIN b[171]
    DIRECTION OUTPUT ;
    USE SIGNAL ;
    PORT
      LAYER M4 ;
        RECT  0 131.472 0.084 131.496 ;
    END
  END b[171]
  PIN b[172]
    DIRECTION OUTPUT ;
    USE SIGNAL ;
    PORT
      LAYER M4 ;
        RECT  0 131.616 0.084 131.64 ;
    END
  END b[172]
  PIN b[173]
    DIRECTION OUTPUT ;
    USE SIGNAL ;
    PORT
      LAYER M4 ;
        RECT  0 131.76 0.084 131.784 ;
    END
  END b[173]
  PIN b[17]
    DIRECTION OUTPUT ;
    USE SIGNAL ;
    PORT
      LAYER M4 ;
        RECT  0 34.128 0.084 34.152 ;
    END
  END b[17]
  PIN b[18]
    DIRECTION OUTPUT ;
    USE SIGNAL ;
    PORT
      LAYER M4 ;
        RECT  0 34.272 0.084 34.296 ;
    END
  END b[18]
  PIN b[19]
    DIRECTION OUTPUT ;
    USE SIGNAL ;
    PORT
      LAYER M4 ;
        RECT  0 34.416 0.084 34.44 ;
    END
  END b[19]
  PIN b[1]
    DIRECTION OUTPUT ;
    USE SIGNAL ;
    PORT
      LAYER M4 ;
        RECT  0 31.824 0.084 31.848 ;
    END
  END b[1]
  PIN b[20]
    DIRECTION OUTPUT ;
    USE SIGNAL ;
    PORT
      LAYER M4 ;
        RECT  0 34.56 0.084 34.584 ;
    END
  END b[20]
  PIN b[21]
    DIRECTION OUTPUT ;
    USE SIGNAL ;
    PORT
      LAYER M4 ;
        RECT  0 34.704 0.084 34.728 ;
    END
  END b[21]
  PIN b[22]
    DIRECTION OUTPUT ;
    USE SIGNAL ;
    PORT
      LAYER M4 ;
        RECT  0 34.848 0.084 34.872 ;
    END
  END b[22]
  PIN b[23]
    DIRECTION OUTPUT ;
    USE SIGNAL ;
    PORT
      LAYER M4 ;
        RECT  0 34.992 0.084 35.016 ;
    END
  END b[23]
  PIN b[24]
    DIRECTION OUTPUT ;
    USE SIGNAL ;
    PORT
      LAYER M4 ;
        RECT  0 35.136 0.084 35.16 ;
    END
  END b[24]
  PIN b[25]
    DIRECTION OUTPUT ;
    USE SIGNAL ;
    PORT
      LAYER M4 ;
        RECT  0 35.28 0.084 35.304 ;
    END
  END b[25]
  PIN b[26]
    DIRECTION OUTPUT ;
    USE SIGNAL ;
    PORT
      LAYER M4 ;
        RECT  0 35.424 0.084 35.448 ;
    END
  END b[26]
  PIN b[27]
    DIRECTION OUTPUT ;
    USE SIGNAL ;
    PORT
      LAYER M4 ;
        RECT  0 35.568 0.084 35.592 ;
    END
  END b[27]
  PIN b[28]
    DIRECTION OUTPUT ;
    USE SIGNAL ;
    PORT
      LAYER M4 ;
        RECT  0 35.712 0.084 35.736 ;
    END
  END b[28]
  PIN b[29]
    DIRECTION OUTPUT ;
    USE SIGNAL ;
    PORT
      LAYER M4 ;
        RECT  0 35.856 0.084 35.88 ;
    END
  END b[29]
  PIN b[2]
    DIRECTION OUTPUT ;
    USE SIGNAL ;
    PORT
      LAYER M4 ;
        RECT  0 31.968 0.084 31.992 ;
    END
  END b[2]
  PIN b[30]
    DIRECTION OUTPUT ;
    USE SIGNAL ;
    PORT
      LAYER M4 ;
        RECT  0 36 0.084 36.024 ;
    END
  END b[30]
  PIN b[31]
    DIRECTION OUTPUT ;
    USE SIGNAL ;
    PORT
      LAYER M4 ;
        RECT  0 36.144 0.084 36.168 ;
    END
  END b[31]
  PIN b[32]
    DIRECTION OUTPUT ;
    USE SIGNAL ;
    PORT
      LAYER M4 ;
        RECT  0 40.896 0.084 40.92 ;
    END
  END b[32]
  PIN b[33]
    DIRECTION OUTPUT ;
    USE SIGNAL ;
    PORT
      LAYER M4 ;
        RECT  0 41.04 0.084 41.064 ;
    END
  END b[33]
  PIN b[34]
    DIRECTION OUTPUT ;
    USE SIGNAL ;
    PORT
      LAYER M4 ;
        RECT  0 41.184 0.084 41.208 ;
    END
  END b[34]
  PIN b[35]
    DIRECTION OUTPUT ;
    USE SIGNAL ;
    PORT
      LAYER M4 ;
        RECT  0 41.328 0.084 41.352 ;
    END
  END b[35]
  PIN b[36]
    DIRECTION OUTPUT ;
    USE SIGNAL ;
    PORT
      LAYER M4 ;
        RECT  0 41.472 0.084 41.496 ;
    END
  END b[36]
  PIN b[37]
    DIRECTION OUTPUT ;
    USE SIGNAL ;
    PORT
      LAYER M4 ;
        RECT  0 41.616 0.084 41.64 ;
    END
  END b[37]
  PIN b[38]
    DIRECTION OUTPUT ;
    USE SIGNAL ;
    PORT
      LAYER M4 ;
        RECT  0 41.76 0.084 41.784 ;
    END
  END b[38]
  PIN b[39]
    DIRECTION OUTPUT ;
    USE SIGNAL ;
    PORT
      LAYER M4 ;
        RECT  0 41.904 0.084 41.928 ;
    END
  END b[39]
  PIN b[3]
    DIRECTION OUTPUT ;
    USE SIGNAL ;
    PORT
      LAYER M4 ;
        RECT  0 32.112 0.084 32.136 ;
    END
  END b[3]
  PIN b[40]
    DIRECTION OUTPUT ;
    USE SIGNAL ;
    PORT
      LAYER M4 ;
        RECT  0 42.048 0.084 42.072 ;
    END
  END b[40]
  PIN b[41]
    DIRECTION OUTPUT ;
    USE SIGNAL ;
    PORT
      LAYER M4 ;
        RECT  0 42.192 0.084 42.216 ;
    END
  END b[41]
  PIN b[42]
    DIRECTION OUTPUT ;
    USE SIGNAL ;
    PORT
      LAYER M4 ;
        RECT  0 42.336 0.084 42.36 ;
    END
  END b[42]
  PIN b[43]
    DIRECTION OUTPUT ;
    USE SIGNAL ;
    PORT
      LAYER M4 ;
        RECT  0 42.48 0.084 42.504 ;
    END
  END b[43]
  PIN b[44]
    DIRECTION OUTPUT ;
    USE SIGNAL ;
    PORT
      LAYER M4 ;
        RECT  0 42.624 0.084 42.648 ;
    END
  END b[44]
  PIN b[45]
    DIRECTION OUTPUT ;
    USE SIGNAL ;
    PORT
      LAYER M4 ;
        RECT  0 42.768 0.084 42.792 ;
    END
  END b[45]
  PIN b[46]
    DIRECTION OUTPUT ;
    USE SIGNAL ;
    PORT
      LAYER M4 ;
        RECT  0 42.912 0.084 42.936 ;
    END
  END b[46]
  PIN b[47]
    DIRECTION OUTPUT ;
    USE SIGNAL ;
    PORT
      LAYER M4 ;
        RECT  0 43.056 0.084 43.08 ;
    END
  END b[47]
  PIN b[48]
    DIRECTION OUTPUT ;
    USE SIGNAL ;
    PORT
      LAYER M4 ;
        RECT  0 43.2 0.084 43.224 ;
    END
  END b[48]
  PIN b[49]
    DIRECTION OUTPUT ;
    USE SIGNAL ;
    PORT
      LAYER M4 ;
        RECT  0 43.344 0.084 43.368 ;
    END
  END b[49]
  PIN b[4]
    DIRECTION OUTPUT ;
    USE SIGNAL ;
    PORT
      LAYER M4 ;
        RECT  0 32.256 0.084 32.28 ;
    END
  END b[4]
  PIN b[50]
    DIRECTION OUTPUT ;
    USE SIGNAL ;
    PORT
      LAYER M4 ;
        RECT  0 43.488 0.084 43.512 ;
    END
  END b[50]
  PIN b[51]
    DIRECTION OUTPUT ;
    USE SIGNAL ;
    PORT
      LAYER M4 ;
        RECT  0 43.632 0.084 43.656 ;
    END
  END b[51]
  PIN b[52]
    DIRECTION OUTPUT ;
    USE SIGNAL ;
    PORT
      LAYER M4 ;
        RECT  0 43.776 0.084 43.8 ;
    END
  END b[52]
  PIN b[53]
    DIRECTION OUTPUT ;
    USE SIGNAL ;
    PORT
      LAYER M4 ;
        RECT  0 43.92 0.084 43.944 ;
    END
  END b[53]
  PIN b[54]
    DIRECTION OUTPUT ;
    USE SIGNAL ;
    PORT
      LAYER M4 ;
        RECT  0 44.064 0.084 44.088 ;
    END
  END b[54]
  PIN b[55]
    DIRECTION OUTPUT ;
    USE SIGNAL ;
    PORT
      LAYER M4 ;
        RECT  0 44.208 0.084 44.232 ;
    END
  END b[55]
  PIN b[56]
    DIRECTION OUTPUT ;
    USE SIGNAL ;
    PORT
      LAYER M4 ;
        RECT  0 44.352 0.084 44.376 ;
    END
  END b[56]
  PIN b[57]
    DIRECTION OUTPUT ;
    USE SIGNAL ;
    PORT
      LAYER M4 ;
        RECT  0 44.496 0.084 44.52 ;
    END
  END b[57]
  PIN b[58]
    DIRECTION OUTPUT ;
    USE SIGNAL ;
    PORT
      LAYER M4 ;
        RECT  0 44.64 0.084 44.664 ;
    END
  END b[58]
  PIN b[59]
    DIRECTION OUTPUT ;
    USE SIGNAL ;
    PORT
      LAYER M4 ;
        RECT  0 44.784 0.084 44.808 ;
    END
  END b[59]
  PIN b[5]
    DIRECTION OUTPUT ;
    USE SIGNAL ;
    PORT
      LAYER M4 ;
        RECT  0 32.4 0.084 32.424 ;
    END
  END b[5]
  PIN b[60]
    DIRECTION OUTPUT ;
    USE SIGNAL ;
    PORT
      LAYER M4 ;
        RECT  0 44.928 0.084 44.952 ;
    END
  END b[60]
  PIN b[61]
    DIRECTION OUTPUT ;
    USE SIGNAL ;
    PORT
      LAYER M4 ;
        RECT  0 45.072 0.084 45.096 ;
    END
  END b[61]
  PIN b[62]
    DIRECTION OUTPUT ;
    USE SIGNAL ;
    PORT
      LAYER M4 ;
        RECT  0 45.216 0.084 45.24 ;
    END
  END b[62]
  PIN b[63]
    DIRECTION OUTPUT ;
    USE SIGNAL ;
    PORT
      LAYER M4 ;
        RECT  0 45.36 0.084 45.384 ;
    END
  END b[63]
  PIN b[64]
    DIRECTION OUTPUT ;
    USE SIGNAL ;
    PORT
      LAYER M4 ;
        RECT  0 74.304 0.084 74.328 ;
    END
  END b[64]
  PIN b[65]
    DIRECTION OUTPUT ;
    USE SIGNAL ;
    PORT
      LAYER M4 ;
        RECT  0 74.448 0.084 74.472 ;
    END
  END b[65]
  PIN b[66]
    DIRECTION OUTPUT ;
    USE SIGNAL ;
    PORT
      LAYER M4 ;
        RECT  0 74.592 0.084 74.616 ;
    END
  END b[66]
  PIN b[67]
    DIRECTION OUTPUT ;
    USE SIGNAL ;
    PORT
      LAYER M4 ;
        RECT  0 74.736 0.084 74.76 ;
    END
  END b[67]
  PIN b[68]
    DIRECTION OUTPUT ;
    USE SIGNAL ;
    PORT
      LAYER M4 ;
        RECT  0 74.88 0.084 74.904 ;
    END
  END b[68]
  PIN b[69]
    DIRECTION OUTPUT ;
    USE SIGNAL ;
    PORT
      LAYER M4 ;
        RECT  0 75.024 0.084 75.048 ;
    END
  END b[69]
  PIN b[6]
    DIRECTION OUTPUT ;
    USE SIGNAL ;
    PORT
      LAYER M4 ;
        RECT  0 32.544 0.084 32.568 ;
    END
  END b[6]
  PIN b[70]
    DIRECTION OUTPUT ;
    USE SIGNAL ;
    PORT
      LAYER M4 ;
        RECT  0 75.168 0.084 75.192 ;
    END
  END b[70]
  PIN b[71]
    DIRECTION OUTPUT ;
    USE SIGNAL ;
    PORT
      LAYER M4 ;
        RECT  0 75.312 0.084 75.336 ;
    END
  END b[71]
  PIN b[72]
    DIRECTION OUTPUT ;
    USE SIGNAL ;
    PORT
      LAYER M4 ;
        RECT  0 75.456 0.084 75.48 ;
    END
  END b[72]
  PIN b[73]
    DIRECTION OUTPUT ;
    USE SIGNAL ;
    PORT
      LAYER M4 ;
        RECT  0 75.6 0.084 75.624 ;
    END
  END b[73]
  PIN b[74]
    DIRECTION OUTPUT ;
    USE SIGNAL ;
    PORT
      LAYER M4 ;
        RECT  0 75.744 0.084 75.768 ;
    END
  END b[74]
  PIN b[75]
    DIRECTION OUTPUT ;
    USE SIGNAL ;
    PORT
      LAYER M4 ;
        RECT  0 75.888 0.084 75.912 ;
    END
  END b[75]
  PIN b[76]
    DIRECTION OUTPUT ;
    USE SIGNAL ;
    PORT
      LAYER M4 ;
        RECT  0 76.032 0.084 76.056 ;
    END
  END b[76]
  PIN b[77]
    DIRECTION OUTPUT ;
    USE SIGNAL ;
    PORT
      LAYER M4 ;
        RECT  0 76.176 0.084 76.2 ;
    END
  END b[77]
  PIN b[78]
    DIRECTION OUTPUT ;
    USE SIGNAL ;
    PORT
      LAYER M4 ;
        RECT  0 76.32 0.084 76.344 ;
    END
  END b[78]
  PIN b[79]
    DIRECTION OUTPUT ;
    USE SIGNAL ;
    PORT
      LAYER M4 ;
        RECT  0 76.464 0.084 76.488 ;
    END
  END b[79]
  PIN b[7]
    DIRECTION OUTPUT ;
    USE SIGNAL ;
    PORT
      LAYER M4 ;
        RECT  0 32.688 0.084 32.712 ;
    END
  END b[7]
  PIN b[80]
    DIRECTION OUTPUT ;
    USE SIGNAL ;
    PORT
      LAYER M4 ;
        RECT  0 76.608 0.084 76.632 ;
    END
  END b[80]
  PIN b[81]
    DIRECTION OUTPUT ;
    USE SIGNAL ;
    PORT
      LAYER M4 ;
        RECT  0 76.752 0.084 76.776 ;
    END
  END b[81]
  PIN b[82]
    DIRECTION OUTPUT ;
    USE SIGNAL ;
    PORT
      LAYER M4 ;
        RECT  0 76.896 0.084 76.92 ;
    END
  END b[82]
  PIN b[83]
    DIRECTION OUTPUT ;
    USE SIGNAL ;
    PORT
      LAYER M4 ;
        RECT  0 77.04 0.084 77.064 ;
    END
  END b[83]
  PIN b[84]
    DIRECTION OUTPUT ;
    USE SIGNAL ;
    PORT
      LAYER M4 ;
        RECT  0 77.184 0.084 77.208 ;
    END
  END b[84]
  PIN b[85]
    DIRECTION OUTPUT ;
    USE SIGNAL ;
    PORT
      LAYER M4 ;
        RECT  0 77.328 0.084 77.352 ;
    END
  END b[85]
  PIN b[86]
    DIRECTION OUTPUT ;
    USE SIGNAL ;
    PORT
      LAYER M4 ;
        RECT  0 77.472 0.084 77.496 ;
    END
  END b[86]
  PIN b[87]
    DIRECTION OUTPUT ;
    USE SIGNAL ;
    PORT
      LAYER M4 ;
        RECT  0 77.616 0.084 77.64 ;
    END
  END b[87]
  PIN b[88]
    DIRECTION OUTPUT ;
    USE SIGNAL ;
    PORT
      LAYER M4 ;
        RECT  0 77.76 0.084 77.784 ;
    END
  END b[88]
  PIN b[89]
    DIRECTION OUTPUT ;
    USE SIGNAL ;
    PORT
      LAYER M4 ;
        RECT  0 77.904 0.084 77.928 ;
    END
  END b[89]
  PIN b[8]
    DIRECTION OUTPUT ;
    USE SIGNAL ;
    PORT
      LAYER M4 ;
        RECT  0 32.832 0.084 32.856 ;
    END
  END b[8]
  PIN b[90]
    DIRECTION OUTPUT ;
    USE SIGNAL ;
    PORT
      LAYER M4 ;
        RECT  0 78.048 0.084 78.072 ;
    END
  END b[90]
  PIN b[91]
    DIRECTION OUTPUT ;
    USE SIGNAL ;
    PORT
      LAYER M4 ;
        RECT  0 78.192 0.084 78.216 ;
    END
  END b[91]
  PIN b[92]
    DIRECTION OUTPUT ;
    USE SIGNAL ;
    PORT
      LAYER M4 ;
        RECT  0 78.336 0.084 78.36 ;
    END
  END b[92]
  PIN b[93]
    DIRECTION OUTPUT ;
    USE SIGNAL ;
    PORT
      LAYER M4 ;
        RECT  0 78.48 0.084 78.504 ;
    END
  END b[93]
  PIN b[94]
    DIRECTION OUTPUT ;
    USE SIGNAL ;
    PORT
      LAYER M4 ;
        RECT  0 78.624 0.084 78.648 ;
    END
  END b[94]
  PIN b[95]
    DIRECTION OUTPUT ;
    USE SIGNAL ;
    PORT
      LAYER M4 ;
        RECT  0 78.768 0.084 78.792 ;
    END
  END b[95]
  PIN b[96]
    DIRECTION OUTPUT ;
    USE SIGNAL ;
    PORT
      LAYER M4 ;
        RECT  0 84.672 0.084 84.696 ;
    END
  END b[96]
  PIN b[97]
    DIRECTION OUTPUT ;
    USE SIGNAL ;
    PORT
      LAYER M4 ;
        RECT  0 84.816 0.084 84.84 ;
    END
  END b[97]
  PIN b[98]
    DIRECTION OUTPUT ;
    USE SIGNAL ;
    PORT
      LAYER M4 ;
        RECT  0 84.96 0.084 84.984 ;
    END
  END b[98]
  PIN b[99]
    DIRECTION OUTPUT ;
    USE SIGNAL ;
    PORT
      LAYER M4 ;
        RECT  0 85.104 0.084 85.128 ;
    END
  END b[99]
  PIN b[9]
    DIRECTION OUTPUT ;
    USE SIGNAL ;
    PORT
      LAYER M4 ;
        RECT  0 32.976 0.084 33 ;
    END
  END b[9]
  PIN ck
    DIRECTION INPUT ;
    USE SIGNAL ;
    PORT
      LAYER M3 ;
        RECT  37.908 170.603 37.926 170.64 ;
    END
  END ck
  PIN ck_s
    DIRECTION INPUT ;
    USE SIGNAL ;
    PORT
      LAYER M3 ;
        RECT  38.016 170.603 38.034 170.64 ;
    END
  END ck_s
  PIN en
    DIRECTION INPUT ;
    USE SIGNAL ;
    PORT
      LAYER M3 ;
        RECT  38.124 170.603 38.142 170.64 ;
    END
  END en
  PIN fault
    DIRECTION OUTPUT ;
    USE SIGNAL ;
    PORT
      LAYER M3 ;
        RECT  38.232 170.603 38.25 170.64 ;
    END
  END fault
  PIN k0
    DIRECTION INPUT ;
    USE SIGNAL ;
    PORT
      LAYER M3 ;
        RECT  38.34 170.603 38.358 170.64 ;
    END
  END k0
  PIN k1
    DIRECTION INPUT ;
    USE SIGNAL ;
    PORT
      LAYER M3 ;
        RECT  38.448 170.603 38.466 170.64 ;
    END
  END k1
  PIN k2
    DIRECTION INPUT ;
    USE SIGNAL ;
    PORT
      LAYER M3 ;
        RECT  38.556 170.603 38.574 170.64 ;
    END
  END k2
  PIN k3
    DIRECTION INPUT ;
    USE SIGNAL ;
    PORT
      LAYER M3 ;
        RECT  38.664 170.603 38.682 170.64 ;
    END
  END k3
  PIN rs
    DIRECTION INPUT ;
    USE SIGNAL ;
    PORT
      LAYER M3 ;
        RECT  38.772 170.603 38.79 170.64 ;
    END
  END rs
  PIN tie_hi
    DIRECTION OUTPUT ;
    USE SIGNAL ;
    PORT
      LAYER M3 ;
        RECT  38.88 170.603 38.898 170.64 ;
    END
  END tie_hi
  PIN tie_lo
    DIRECTION OUTPUT ;
    USE SIGNAL ;
    PORT
      LAYER M3 ;
        RECT  38.988 170.603 39.006 170.64 ;
    END
  END tie_lo
  PIN VDD
    DIRECTION INOUT ;
    USE POWER ;
    PORT
      LAYER M5 ;
        RECT  94.392 2.151 94.512 168.489 ;
        RECT  91.692 2.151 91.812 168.489 ;
        RECT  88.992 2.151 89.112 168.489 ;
        RECT  86.292 2.151 86.412 168.489 ;
        RECT  83.592 2.151 83.712 168.489 ;
        RECT  80.892 2.151 81.012 168.489 ;
        RECT  78.192 2.151 78.312 168.489 ;
        RECT  75.492 2.151 75.612 168.489 ;
        RECT  72.792 2.151 72.912 168.489 ;
        RECT  70.092 2.151 70.212 168.489 ;
        RECT  67.392 2.151 67.512 168.489 ;
        RECT  64.692 2.151 64.812 168.489 ;
        RECT  61.992 2.151 62.112 168.489 ;
        RECT  59.292 2.151 59.412 168.489 ;
        RECT  56.592 2.151 56.712 168.489 ;
        RECT  53.892 2.151 54.012 168.489 ;
        RECT  51.192 2.151 51.312 168.489 ;
        RECT  48.492 2.151 48.612 168.489 ;
        RECT  45.792 2.151 45.912 168.489 ;
        RECT  43.092 2.151 43.212 168.489 ;
        RECT  40.392 2.151 40.512 168.489 ;
        RECT  37.692 2.151 37.812 168.489 ;
        RECT  34.992 2.151 35.112 168.489 ;
        RECT  32.292 2.151 32.412 168.489 ;
        RECT  29.592 2.151 29.712 168.489 ;
        RECT  26.892 2.151 27.012 168.489 ;
        RECT  24.192 2.151 24.312 168.489 ;
        RECT  21.492 2.151 21.612 168.489 ;
        RECT  18.792 2.151 18.912 168.489 ;
        RECT  16.092 2.151 16.212 168.489 ;
        RECT  13.392 2.151 13.512 168.489 ;
        RECT  10.692 2.151 10.812 168.489 ;
        RECT  7.992 2.151 8.112 168.489 ;
        RECT  5.292 2.151 5.412 168.489 ;
        RECT  2.592 2.151 2.712 168.489 ;
    END
  END VDD
  PIN VSS
    DIRECTION INOUT ;
    USE GROUND ;
    PORT
      LAYER M5 ;
        RECT  94.2 2.137 94.32 168.503 ;
        RECT  91.5 2.137 91.62 168.503 ;
        RECT  88.8 2.137 88.92 168.503 ;
        RECT  86.1 2.137 86.22 168.503 ;
        RECT  83.4 2.137 83.52 168.503 ;
        RECT  80.7 2.137 80.82 168.503 ;
        RECT  78 2.137 78.12 168.503 ;
        RECT  75.3 2.137 75.42 168.503 ;
        RECT  72.6 2.137 72.72 168.503 ;
        RECT  69.9 2.137 70.02 168.503 ;
        RECT  67.2 2.137 67.32 168.503 ;
        RECT  64.5 2.137 64.62 168.503 ;
        RECT  61.8 2.137 61.92 168.503 ;
        RECT  59.1 2.137 59.22 168.503 ;
        RECT  56.4 2.137 56.52 168.503 ;
        RECT  53.7 2.137 53.82 168.503 ;
        RECT  51 2.137 51.12 168.503 ;
        RECT  48.3 2.137 48.42 168.503 ;
        RECT  45.6 2.137 45.72 168.503 ;
        RECT  42.9 2.137 43.02 168.503 ;
        RECT  40.2 2.137 40.32 168.503 ;
        RECT  37.5 2.137 37.62 168.503 ;
        RECT  34.8 2.137 34.92 168.503 ;
        RECT  32.1 2.137 32.22 168.503 ;
        RECT  29.4 2.137 29.52 168.503 ;
        RECT  26.7 2.137 26.82 168.503 ;
        RECT  24 2.137 24.12 168.503 ;
        RECT  21.3 2.137 21.42 168.503 ;
        RECT  18.6 2.137 18.72 168.503 ;
        RECT  15.9 2.137 16.02 168.503 ;
        RECT  13.2 2.137 13.32 168.503 ;
        RECT  10.5 2.137 10.62 168.503 ;
        RECT  7.8 2.137 7.92 168.503 ;
        RECT  5.1 2.137 5.22 168.503 ;
        RECT  2.4 2.137 2.52 168.503 ;
    END
  END VSS
  OBS
    LAYER RVTN ;
     RECT  2.16 2.16 96.12 2.295 ;
     RECT  2.16 2.565 96.12 2.835 ;
     RECT  2.16 3.105 96.12 3.375 ;
     RECT  2.16 3.645 96.12 3.915 ;
     RECT  2.16 4.185 96.12 4.455 ;
     RECT  2.16 4.725 96.12 4.995 ;
     RECT  2.16 5.265 96.12 5.535 ;
     RECT  2.16 5.805 96.12 6.075 ;
     RECT  2.16 6.345 96.12 6.615 ;
     RECT  2.16 6.885 96.12 7.155 ;
     RECT  2.16 7.425 96.12 7.695 ;
     RECT  2.16 7.965 96.12 8.235 ;
     RECT  2.16 8.505 96.12 8.775 ;
     RECT  2.16 9.045 96.12 9.315 ;
     RECT  2.16 9.585 96.12 9.855 ;
     RECT  2.16 10.125 96.12 10.395 ;
     RECT  2.16 10.665 96.12 10.935 ;
     RECT  2.16 11.205 96.12 11.475 ;
     RECT  2.16 11.745 96.12 12.015 ;
     RECT  2.16 12.285 96.12 12.555 ;
     RECT  2.16 12.825 96.12 13.095 ;
     RECT  2.16 13.365 96.12 13.635 ;
     RECT  2.16 13.905 96.12 14.175 ;
     RECT  2.16 14.445 96.12 14.715 ;
     RECT  2.16 14.985 96.12 15.255 ;
     RECT  2.16 15.525 96.12 15.795 ;
     RECT  2.16 16.065 96.12 16.335 ;
     RECT  2.16 16.605 96.12 16.875 ;
     RECT  2.16 17.145 96.12 17.415 ;
     RECT  2.16 17.685 96.12 17.955 ;
     RECT  2.16 18.225 96.12 18.495 ;
     RECT  2.16 18.765 96.12 19.035 ;
     RECT  2.16 19.305 96.12 19.575 ;
     RECT  2.16 19.845 96.12 20.115 ;
     RECT  2.16 20.385 96.12 20.655 ;
     RECT  2.16 20.925 96.12 21.195 ;
     RECT  2.16 21.465 96.12 21.735 ;
     RECT  2.16 22.005 96.12 22.275 ;
     RECT  2.16 22.545 96.12 22.815 ;
     RECT  2.16 23.085 96.12 23.355 ;
     RECT  2.16 23.625 96.12 23.895 ;
     RECT  2.16 24.165 96.12 24.435 ;
     RECT  2.16 24.705 96.12 24.975 ;
     RECT  2.16 25.245 96.12 25.515 ;
     RECT  2.16 25.785 96.12 26.055 ;
     RECT  2.16 26.325 96.12 26.595 ;
     RECT  2.16 26.865 96.12 27.135 ;
     RECT  2.16 27.405 96.12 27.675 ;
     RECT  2.16 27.945 96.12 28.215 ;
     RECT  2.16 28.485 96.12 28.755 ;
     RECT  2.16 29.025 96.12 29.295 ;
     RECT  2.16 29.565 96.12 29.835 ;
     RECT  2.16 30.105 96.12 30.375 ;
     RECT  2.16 30.645 96.12 30.915 ;
     RECT  2.16 31.185 96.12 31.455 ;
     RECT  2.16 31.725 96.12 31.995 ;
     RECT  2.16 32.265 96.12 32.535 ;
     RECT  2.16 32.805 96.12 33.075 ;
     RECT  2.16 33.345 96.12 33.615 ;
     RECT  2.16 33.885 96.12 34.155 ;
     RECT  2.16 34.425 96.12 34.695 ;
     RECT  2.16 34.965 96.12 35.235 ;
     RECT  2.16 35.505 96.12 35.775 ;
     RECT  2.16 36.045 96.12 36.315 ;
     RECT  2.16 36.585 96.12 36.855 ;
     RECT  2.16 37.125 96.12 37.395 ;
     RECT  2.16 37.665 96.12 37.935 ;
     RECT  2.16 38.205 96.12 38.475 ;
     RECT  2.16 38.745 96.12 39.015 ;
     RECT  2.16 39.285 96.12 39.555 ;
     RECT  2.16 39.825 96.12 40.095 ;
     RECT  2.16 40.365 96.12 40.635 ;
     RECT  2.16 40.905 96.12 41.04 ;
     RECT  2.16 41.04 41.148 41.175 ;
     RECT  77.22 41.04 96.12 41.175 ;
     RECT  2.16 41.445 41.148 41.715 ;
     RECT  77.22 41.445 96.12 41.715 ;
     RECT  2.16 41.985 41.148 42.255 ;
     RECT  77.22 41.985 96.12 42.255 ;
     RECT  2.16 42.525 41.148 42.795 ;
     RECT  77.22 42.525 96.12 42.795 ;
     RECT  2.16 43.065 41.148 43.335 ;
     RECT  77.22 43.065 96.12 43.335 ;
     RECT  2.16 43.605 41.148 43.875 ;
     RECT  77.22 43.605 96.12 43.875 ;
     RECT  2.16 44.145 41.148 44.415 ;
     RECT  77.22 44.145 96.12 44.415 ;
     RECT  2.16 44.685 41.148 44.955 ;
     RECT  77.22 44.685 96.12 44.955 ;
     RECT  2.16 45.225 41.148 45.495 ;
     RECT  77.22 45.225 96.12 45.495 ;
     RECT  2.16 45.765 41.148 46.035 ;
     RECT  77.22 45.765 96.12 46.035 ;
     RECT  2.16 46.305 41.148 46.575 ;
     RECT  77.22 46.305 96.12 46.575 ;
     RECT  2.16 46.845 41.148 47.115 ;
     RECT  77.22 46.845 96.12 47.115 ;
     RECT  2.16 47.385 41.148 47.655 ;
     RECT  77.22 47.385 96.12 47.655 ;
     RECT  2.16 47.925 41.148 48.195 ;
     RECT  77.22 47.925 96.12 48.195 ;
     RECT  2.16 48.465 41.148 48.735 ;
     RECT  77.22 48.465 96.12 48.735 ;
     RECT  2.16 49.005 41.148 49.275 ;
     RECT  77.22 49.005 96.12 49.275 ;
     RECT  2.16 49.545 41.148 49.815 ;
     RECT  77.22 49.545 96.12 49.815 ;
     RECT  2.16 50.085 41.148 50.355 ;
     RECT  77.22 50.085 96.12 50.355 ;
     RECT  2.16 50.625 41.148 50.895 ;
     RECT  77.22 50.625 96.12 50.895 ;
     RECT  2.16 51.165 41.148 51.435 ;
     RECT  77.22 51.165 96.12 51.435 ;
     RECT  2.16 51.705 41.148 51.975 ;
     RECT  77.22 51.705 96.12 51.975 ;
     RECT  2.16 52.245 41.148 52.515 ;
     RECT  77.22 52.245 96.12 52.515 ;
     RECT  2.16 52.785 41.148 53.055 ;
     RECT  77.22 52.785 96.12 53.055 ;
     RECT  2.16 53.325 41.148 53.595 ;
     RECT  77.22 53.325 96.12 53.595 ;
     RECT  2.16 53.865 41.148 54.135 ;
     RECT  77.22 53.865 96.12 54.135 ;
     RECT  2.16 54.405 41.148 54.675 ;
     RECT  77.22 54.405 96.12 54.675 ;
     RECT  2.16 54.945 41.148 55.215 ;
     RECT  77.22 54.945 96.12 55.215 ;
     RECT  2.16 55.485 41.148 55.755 ;
     RECT  77.22 55.485 96.12 55.755 ;
     RECT  2.16 56.025 41.148 56.295 ;
     RECT  77.22 56.025 96.12 56.295 ;
     RECT  2.16 56.565 41.148 56.835 ;
     RECT  77.22 56.565 96.12 56.835 ;
     RECT  2.16 57.105 41.148 57.375 ;
     RECT  77.22 57.105 96.12 57.375 ;
     RECT  2.16 57.645 41.148 57.915 ;
     RECT  77.22 57.645 96.12 57.915 ;
     RECT  2.16 58.185 41.148 58.455 ;
     RECT  77.22 58.185 96.12 58.455 ;
     RECT  2.16 58.725 41.148 58.995 ;
     RECT  77.22 58.725 96.12 58.995 ;
     RECT  2.16 59.265 41.148 59.535 ;
     RECT  77.22 59.265 96.12 59.535 ;
     RECT  2.16 59.805 41.148 60.075 ;
     RECT  77.22 59.805 96.12 60.075 ;
     RECT  2.16 60.345 41.148 60.615 ;
     RECT  77.22 60.345 96.12 60.615 ;
     RECT  2.16 60.885 41.148 61.155 ;
     RECT  77.22 60.885 96.12 61.155 ;
     RECT  2.16 61.425 41.148 61.695 ;
     RECT  77.22 61.425 96.12 61.695 ;
     RECT  2.16 61.965 41.148 62.235 ;
     RECT  77.22 61.965 96.12 62.235 ;
     RECT  2.16 62.505 41.148 62.64 ;
     RECT  77.22 62.505 96.12 62.64 ;
     RECT  2.16 62.64 96.12 62.775 ;
     RECT  2.16 63.045 96.12 63.315 ;
     RECT  2.16 63.585 96.12 63.855 ;
     RECT  2.16 64.125 96.12 64.395 ;
     RECT  2.16 64.665 96.12 64.935 ;
     RECT  2.16 65.205 96.12 65.475 ;
     RECT  2.16 65.745 96.12 66.015 ;
     RECT  2.16 66.285 96.12 66.555 ;
     RECT  2.16 66.825 96.12 67.095 ;
     RECT  2.16 67.365 96.12 67.635 ;
     RECT  2.16 67.905 96.12 68.175 ;
     RECT  2.16 68.445 96.12 68.715 ;
     RECT  2.16 68.985 96.12 69.255 ;
     RECT  2.16 69.525 96.12 69.795 ;
     RECT  2.16 70.065 96.12 70.335 ;
     RECT  2.16 70.605 96.12 70.875 ;
     RECT  2.16 71.145 96.12 71.415 ;
     RECT  2.16 71.685 96.12 71.955 ;
     RECT  2.16 72.225 96.12 72.495 ;
     RECT  2.16 72.765 96.12 73.035 ;
     RECT  2.16 73.305 96.12 73.575 ;
     RECT  2.16 73.845 96.12 74.115 ;
     RECT  2.16 74.385 96.12 74.655 ;
     RECT  2.16 74.925 96.12 75.195 ;
     RECT  2.16 75.465 96.12 75.735 ;
     RECT  2.16 76.005 96.12 76.275 ;
     RECT  2.16 76.545 96.12 76.815 ;
     RECT  2.16 77.085 96.12 77.355 ;
     RECT  2.16 77.625 96.12 77.895 ;
     RECT  2.16 78.165 96.12 78.435 ;
     RECT  2.16 78.705 96.12 78.975 ;
     RECT  2.16 79.245 96.12 79.515 ;
     RECT  2.16 79.785 96.12 80.055 ;
     RECT  2.16 80.325 96.12 80.595 ;
     RECT  2.16 80.865 96.12 81.135 ;
     RECT  2.16 81.405 96.12 81.675 ;
     RECT  2.16 81.945 96.12 82.215 ;
     RECT  2.16 82.485 96.12 82.755 ;
     RECT  2.16 83.025 96.12 83.295 ;
     RECT  2.16 83.565 96.12 83.835 ;
     RECT  2.16 84.105 96.12 84.24 ;
     RECT  2.16 84.24 41.148 84.375 ;
     RECT  77.22 84.24 96.12 84.375 ;
     RECT  2.16 84.645 41.148 84.915 ;
     RECT  77.22 84.645 96.12 84.915 ;
     RECT  2.16 85.185 41.148 85.455 ;
     RECT  77.22 85.185 96.12 85.455 ;
     RECT  2.16 85.725 41.148 85.995 ;
     RECT  77.22 85.725 96.12 85.995 ;
     RECT  2.16 86.265 41.148 86.535 ;
     RECT  77.22 86.265 96.12 86.535 ;
     RECT  2.16 86.805 41.148 87.075 ;
     RECT  77.22 86.805 96.12 87.075 ;
     RECT  2.16 87.345 41.148 87.615 ;
     RECT  77.22 87.345 96.12 87.615 ;
     RECT  2.16 87.885 41.148 88.155 ;
     RECT  77.22 87.885 96.12 88.155 ;
     RECT  2.16 88.425 41.148 88.695 ;
     RECT  77.22 88.425 96.12 88.695 ;
     RECT  2.16 88.965 41.148 89.235 ;
     RECT  77.22 88.965 96.12 89.235 ;
     RECT  2.16 89.505 41.148 89.775 ;
     RECT  77.22 89.505 96.12 89.775 ;
     RECT  2.16 90.045 41.148 90.315 ;
     RECT  77.22 90.045 96.12 90.315 ;
     RECT  2.16 90.585 41.148 90.855 ;
     RECT  77.22 90.585 96.12 90.855 ;
     RECT  2.16 91.125 41.148 91.395 ;
     RECT  77.22 91.125 96.12 91.395 ;
     RECT  2.16 91.665 41.148 91.935 ;
     RECT  77.22 91.665 96.12 91.935 ;
     RECT  2.16 92.205 41.148 92.475 ;
     RECT  77.22 92.205 96.12 92.475 ;
     RECT  2.16 92.745 41.148 93.015 ;
     RECT  77.22 92.745 96.12 93.015 ;
     RECT  2.16 93.285 41.148 93.555 ;
     RECT  77.22 93.285 96.12 93.555 ;
     RECT  2.16 93.825 41.148 94.095 ;
     RECT  77.22 93.825 96.12 94.095 ;
     RECT  2.16 94.365 41.148 94.635 ;
     RECT  77.22 94.365 96.12 94.635 ;
     RECT  2.16 94.905 41.148 95.175 ;
     RECT  77.22 94.905 96.12 95.175 ;
     RECT  2.16 95.445 41.148 95.715 ;
     RECT  77.22 95.445 96.12 95.715 ;
     RECT  2.16 95.985 41.148 96.255 ;
     RECT  77.22 95.985 96.12 96.255 ;
     RECT  2.16 96.525 41.148 96.795 ;
     RECT  77.22 96.525 96.12 96.795 ;
     RECT  2.16 97.065 41.148 97.335 ;
     RECT  77.22 97.065 96.12 97.335 ;
     RECT  2.16 97.605 41.148 97.875 ;
     RECT  77.22 97.605 96.12 97.875 ;
     RECT  2.16 98.145 41.148 98.415 ;
     RECT  77.22 98.145 96.12 98.415 ;
     RECT  2.16 98.685 41.148 98.955 ;
     RECT  77.22 98.685 96.12 98.955 ;
     RECT  2.16 99.225 41.148 99.495 ;
     RECT  77.22 99.225 96.12 99.495 ;
     RECT  2.16 99.765 41.148 100.035 ;
     RECT  77.22 99.765 96.12 100.035 ;
     RECT  2.16 100.305 41.148 100.575 ;
     RECT  77.22 100.305 96.12 100.575 ;
     RECT  2.16 100.845 41.148 101.115 ;
     RECT  77.22 100.845 96.12 101.115 ;
     RECT  2.16 101.385 41.148 101.655 ;
     RECT  77.22 101.385 96.12 101.655 ;
     RECT  2.16 101.925 41.148 102.195 ;
     RECT  77.22 101.925 96.12 102.195 ;
     RECT  2.16 102.465 41.148 102.735 ;
     RECT  77.22 102.465 96.12 102.735 ;
     RECT  2.16 103.005 41.148 103.275 ;
     RECT  77.22 103.005 96.12 103.275 ;
     RECT  2.16 103.545 41.148 103.815 ;
     RECT  77.22 103.545 96.12 103.815 ;
     RECT  2.16 104.085 41.148 104.355 ;
     RECT  77.22 104.085 96.12 104.355 ;
     RECT  2.16 104.625 41.148 104.895 ;
     RECT  77.22 104.625 96.12 104.895 ;
     RECT  2.16 105.165 41.148 105.435 ;
     RECT  77.22 105.165 96.12 105.435 ;
     RECT  2.16 105.705 41.148 105.84 ;
     RECT  77.22 105.705 96.12 105.84 ;
     RECT  2.16 105.84 96.12 105.975 ;
     RECT  2.16 106.245 96.12 106.515 ;
     RECT  2.16 106.785 96.12 107.055 ;
     RECT  2.16 107.325 96.12 107.595 ;
     RECT  2.16 107.865 96.12 108.135 ;
     RECT  2.16 108.405 96.12 108.675 ;
     RECT  2.16 108.945 96.12 109.215 ;
     RECT  2.16 109.485 96.12 109.755 ;
     RECT  2.16 110.025 96.12 110.295 ;
     RECT  2.16 110.565 96.12 110.835 ;
     RECT  2.16 111.105 96.12 111.375 ;
     RECT  2.16 111.645 96.12 111.915 ;
     RECT  2.16 112.185 96.12 112.455 ;
     RECT  2.16 112.725 96.12 112.995 ;
     RECT  2.16 113.265 96.12 113.535 ;
     RECT  2.16 113.805 96.12 114.075 ;
     RECT  2.16 114.345 96.12 114.615 ;
     RECT  2.16 114.885 96.12 115.155 ;
     RECT  2.16 115.425 96.12 115.695 ;
     RECT  2.16 115.965 96.12 116.235 ;
     RECT  2.16 116.505 96.12 116.775 ;
     RECT  2.16 117.045 96.12 117.315 ;
     RECT  2.16 117.585 96.12 117.855 ;
     RECT  2.16 118.125 96.12 118.395 ;
     RECT  2.16 118.665 96.12 118.935 ;
     RECT  2.16 119.205 96.12 119.475 ;
     RECT  2.16 119.745 96.12 120.015 ;
     RECT  2.16 120.285 96.12 120.555 ;
     RECT  2.16 120.825 96.12 121.095 ;
     RECT  2.16 121.365 96.12 121.635 ;
     RECT  2.16 121.905 96.12 122.175 ;
     RECT  2.16 122.445 96.12 122.715 ;
     RECT  2.16 122.985 96.12 123.255 ;
     RECT  2.16 123.525 96.12 123.795 ;
     RECT  2.16 124.065 96.12 124.335 ;
     RECT  2.16 124.605 96.12 124.875 ;
     RECT  2.16 125.145 96.12 125.415 ;
     RECT  2.16 125.685 96.12 125.955 ;
     RECT  2.16 126.225 96.12 126.495 ;
     RECT  2.16 126.765 96.12 127.035 ;
     RECT  2.16 127.305 96.12 127.44 ;
     RECT  2.16 127.44 41.148 127.575 ;
     RECT  77.22 127.44 96.12 127.575 ;
     RECT  2.16 127.845 41.148 128.115 ;
     RECT  77.22 127.845 96.12 128.115 ;
     RECT  2.16 128.385 41.148 128.655 ;
     RECT  77.22 128.385 96.12 128.655 ;
     RECT  2.16 128.925 41.148 129.195 ;
     RECT  77.22 128.925 96.12 129.195 ;
     RECT  2.16 129.465 41.148 129.735 ;
     RECT  77.22 129.465 96.12 129.735 ;
     RECT  2.16 130.005 41.148 130.275 ;
     RECT  77.22 130.005 96.12 130.275 ;
     RECT  2.16 130.545 41.148 130.815 ;
     RECT  77.22 130.545 96.12 130.815 ;
     RECT  2.16 131.085 41.148 131.355 ;
     RECT  77.22 131.085 96.12 131.355 ;
     RECT  2.16 131.625 41.148 131.895 ;
     RECT  77.22 131.625 96.12 131.895 ;
     RECT  2.16 132.165 41.148 132.435 ;
     RECT  77.22 132.165 96.12 132.435 ;
     RECT  2.16 132.705 41.148 132.975 ;
     RECT  77.22 132.705 96.12 132.975 ;
     RECT  2.16 133.245 41.148 133.515 ;
     RECT  77.22 133.245 96.12 133.515 ;
     RECT  2.16 133.785 41.148 134.055 ;
     RECT  77.22 133.785 96.12 134.055 ;
     RECT  2.16 134.325 41.148 134.595 ;
     RECT  77.22 134.325 96.12 134.595 ;
     RECT  2.16 134.865 41.148 135.135 ;
     RECT  77.22 134.865 96.12 135.135 ;
     RECT  2.16 135.405 41.148 135.675 ;
     RECT  77.22 135.405 96.12 135.675 ;
     RECT  2.16 135.945 41.148 136.215 ;
     RECT  77.22 135.945 96.12 136.215 ;
     RECT  2.16 136.485 41.148 136.755 ;
     RECT  77.22 136.485 96.12 136.755 ;
     RECT  2.16 137.025 41.148 137.295 ;
     RECT  77.22 137.025 96.12 137.295 ;
     RECT  2.16 137.565 41.148 137.835 ;
     RECT  77.22 137.565 96.12 137.835 ;
     RECT  2.16 138.105 41.148 138.375 ;
     RECT  77.22 138.105 96.12 138.375 ;
     RECT  2.16 138.645 41.148 138.915 ;
     RECT  77.22 138.645 96.12 138.915 ;
     RECT  2.16 139.185 41.148 139.455 ;
     RECT  77.22 139.185 96.12 139.455 ;
     RECT  2.16 139.725 41.148 139.995 ;
     RECT  77.22 139.725 96.12 139.995 ;
     RECT  2.16 140.265 41.148 140.535 ;
     RECT  77.22 140.265 96.12 140.535 ;
     RECT  2.16 140.805 41.148 141.075 ;
     RECT  77.22 140.805 96.12 141.075 ;
     RECT  2.16 141.345 41.148 141.615 ;
     RECT  77.22 141.345 96.12 141.615 ;
     RECT  2.16 141.885 41.148 142.155 ;
     RECT  77.22 141.885 96.12 142.155 ;
     RECT  2.16 142.425 41.148 142.695 ;
     RECT  77.22 142.425 96.12 142.695 ;
     RECT  2.16 142.965 41.148 143.235 ;
     RECT  77.22 142.965 96.12 143.235 ;
     RECT  2.16 143.505 41.148 143.775 ;
     RECT  77.22 143.505 96.12 143.775 ;
     RECT  2.16 144.045 41.148 144.315 ;
     RECT  77.22 144.045 96.12 144.315 ;
     RECT  2.16 144.585 41.148 144.855 ;
     RECT  77.22 144.585 96.12 144.855 ;
     RECT  2.16 145.125 41.148 145.395 ;
     RECT  77.22 145.125 96.12 145.395 ;
     RECT  2.16 145.665 41.148 145.935 ;
     RECT  77.22 145.665 96.12 145.935 ;
     RECT  2.16 146.205 41.148 146.475 ;
     RECT  77.22 146.205 96.12 146.475 ;
     RECT  2.16 146.745 41.148 147.015 ;
     RECT  77.22 146.745 96.12 147.015 ;
     RECT  2.16 147.285 41.148 147.555 ;
     RECT  77.22 147.285 96.12 147.555 ;
     RECT  2.16 147.825 41.148 148.095 ;
     RECT  77.22 147.825 96.12 148.095 ;
     RECT  2.16 148.365 41.148 148.635 ;
     RECT  77.22 148.365 96.12 148.635 ;
     RECT  2.16 148.905 41.148 149.04 ;
     RECT  77.22 148.905 96.12 149.04 ;
     RECT  2.16 149.04 96.12 149.175 ;
     RECT  2.16 149.445 96.12 149.715 ;
     RECT  2.16 149.985 96.12 150.255 ;
     RECT  2.16 150.525 96.12 150.795 ;
     RECT  2.16 151.065 96.12 151.335 ;
     RECT  2.16 151.605 96.12 151.875 ;
     RECT  2.16 152.145 96.12 152.415 ;
     RECT  2.16 152.685 96.12 152.955 ;
     RECT  2.16 153.225 96.12 153.495 ;
     RECT  2.16 153.765 96.12 154.035 ;
     RECT  2.16 154.305 96.12 154.575 ;
     RECT  2.16 154.845 96.12 155.115 ;
     RECT  2.16 155.385 96.12 155.655 ;
     RECT  2.16 155.925 96.12 156.195 ;
     RECT  2.16 156.465 96.12 156.735 ;
     RECT  2.16 157.005 96.12 157.275 ;
     RECT  2.16 157.545 96.12 157.815 ;
     RECT  2.16 158.085 96.12 158.355 ;
     RECT  2.16 158.625 96.12 158.895 ;
     RECT  2.16 159.165 96.12 159.435 ;
     RECT  2.16 159.705 96.12 159.975 ;
     RECT  2.16 160.245 96.12 160.515 ;
     RECT  2.16 160.785 96.12 161.055 ;
     RECT  2.16 161.325 96.12 161.595 ;
     RECT  2.16 161.865 96.12 162.135 ;
     RECT  2.16 162.405 96.12 162.675 ;
     RECT  2.16 162.945 96.12 163.215 ;
     RECT  2.16 163.485 96.12 163.755 ;
     RECT  2.16 164.025 96.12 164.295 ;
     RECT  2.16 164.565 96.12 164.835 ;
     RECT  2.16 165.105 96.12 165.375 ;
     RECT  2.16 165.645 96.12 165.915 ;
     RECT  2.16 166.185 96.12 166.455 ;
     RECT  2.16 166.725 96.12 166.995 ;
     RECT  2.16 167.265 96.12 167.535 ;
     RECT  2.16 167.805 96.12 168.075 ;
     RECT  2.16 168.345 96.12 168.48 ;
    LAYER RVTP ;
     RECT  2.16 2.295 96.12 2.565 ;
     RECT  2.16 2.835 96.12 3.105 ;
     RECT  2.16 3.375 96.12 3.645 ;
     RECT  2.16 3.915 96.12 4.185 ;
     RECT  2.16 4.455 96.12 4.725 ;
     RECT  2.16 4.995 96.12 5.265 ;
     RECT  2.16 5.535 96.12 5.805 ;
     RECT  2.16 6.075 96.12 6.345 ;
     RECT  2.16 6.615 96.12 6.885 ;
     RECT  2.16 7.155 96.12 7.425 ;
     RECT  2.16 7.695 96.12 7.965 ;
     RECT  2.16 8.235 96.12 8.505 ;
     RECT  2.16 8.775 96.12 9.045 ;
     RECT  2.16 9.315 96.12 9.585 ;
     RECT  2.16 9.855 96.12 10.125 ;
     RECT  2.16 10.395 96.12 10.665 ;
     RECT  2.16 10.935 96.12 11.205 ;
     RECT  2.16 11.475 96.12 11.745 ;
     RECT  2.16 12.015 96.12 12.285 ;
     RECT  2.16 12.555 96.12 12.825 ;
     RECT  2.16 13.095 96.12 13.365 ;
     RECT  2.16 13.635 96.12 13.905 ;
     RECT  2.16 14.175 96.12 14.445 ;
     RECT  2.16 14.715 96.12 14.985 ;
     RECT  2.16 15.255 96.12 15.525 ;
     RECT  2.16 15.795 96.12 16.065 ;
     RECT  2.16 16.335 96.12 16.605 ;
     RECT  2.16 16.875 96.12 17.145 ;
     RECT  2.16 17.415 96.12 17.685 ;
     RECT  2.16 17.955 96.12 18.225 ;
     RECT  2.16 18.495 96.12 18.765 ;
     RECT  2.16 19.035 96.12 19.305 ;
     RECT  2.16 19.575 96.12 19.845 ;
     RECT  2.16 20.115 96.12 20.385 ;
     RECT  2.16 20.655 96.12 20.925 ;
     RECT  2.16 21.195 96.12 21.465 ;
     RECT  2.16 21.735 96.12 22.005 ;
     RECT  2.16 22.275 96.12 22.545 ;
     RECT  2.16 22.815 96.12 23.085 ;
     RECT  2.16 23.355 96.12 23.625 ;
     RECT  2.16 23.895 96.12 24.165 ;
     RECT  2.16 24.435 96.12 24.705 ;
     RECT  2.16 24.975 96.12 25.245 ;
     RECT  2.16 25.515 96.12 25.785 ;
     RECT  2.16 26.055 96.12 26.325 ;
     RECT  2.16 26.595 96.12 26.865 ;
     RECT  2.16 27.135 96.12 27.405 ;
     RECT  2.16 27.675 96.12 27.945 ;
     RECT  2.16 28.215 96.12 28.485 ;
     RECT  2.16 28.755 96.12 29.025 ;
     RECT  2.16 29.295 96.12 29.565 ;
     RECT  2.16 29.835 96.12 30.105 ;
     RECT  2.16 30.375 96.12 30.645 ;
     RECT  2.16 30.915 96.12 31.185 ;
     RECT  2.16 31.455 96.12 31.725 ;
     RECT  2.16 31.995 96.12 32.265 ;
     RECT  2.16 32.535 96.12 32.805 ;
     RECT  2.16 33.075 96.12 33.345 ;
     RECT  2.16 33.615 96.12 33.885 ;
     RECT  2.16 34.155 96.12 34.425 ;
     RECT  2.16 34.695 96.12 34.965 ;
     RECT  2.16 35.235 96.12 35.505 ;
     RECT  2.16 35.775 96.12 36.045 ;
     RECT  2.16 36.315 96.12 36.585 ;
     RECT  2.16 36.855 96.12 37.125 ;
     RECT  2.16 37.395 96.12 37.665 ;
     RECT  2.16 37.935 96.12 38.205 ;
     RECT  2.16 38.475 96.12 38.745 ;
     RECT  2.16 39.015 96.12 39.285 ;
     RECT  2.16 39.555 96.12 39.825 ;
     RECT  2.16 40.095 96.12 40.365 ;
     RECT  2.16 40.635 96.12 40.905 ;
     RECT  2.16 41.175 41.148 41.445 ;
     RECT  77.22 41.175 96.12 41.445 ;
     RECT  2.16 41.715 41.148 41.985 ;
     RECT  77.22 41.715 96.12 41.985 ;
     RECT  2.16 42.255 41.148 42.525 ;
     RECT  77.22 42.255 96.12 42.525 ;
     RECT  2.16 42.795 41.148 43.065 ;
     RECT  77.22 42.795 96.12 43.065 ;
     RECT  2.16 43.335 41.148 43.605 ;
     RECT  77.22 43.335 96.12 43.605 ;
     RECT  2.16 43.875 41.148 44.145 ;
     RECT  77.22 43.875 96.12 44.145 ;
     RECT  2.16 44.415 41.148 44.685 ;
     RECT  77.22 44.415 96.12 44.685 ;
     RECT  2.16 44.955 41.148 45.225 ;
     RECT  77.22 44.955 96.12 45.225 ;
     RECT  2.16 45.495 41.148 45.765 ;
     RECT  77.22 45.495 96.12 45.765 ;
     RECT  2.16 46.035 41.148 46.305 ;
     RECT  77.22 46.035 96.12 46.305 ;
     RECT  2.16 46.575 41.148 46.845 ;
     RECT  77.22 46.575 96.12 46.845 ;
     RECT  2.16 47.115 41.148 47.385 ;
     RECT  77.22 47.115 96.12 47.385 ;
     RECT  2.16 47.655 41.148 47.925 ;
     RECT  77.22 47.655 96.12 47.925 ;
     RECT  2.16 48.195 41.148 48.465 ;
     RECT  77.22 48.195 96.12 48.465 ;
     RECT  2.16 48.735 41.148 49.005 ;
     RECT  77.22 48.735 96.12 49.005 ;
     RECT  2.16 49.275 41.148 49.545 ;
     RECT  77.22 49.275 96.12 49.545 ;
     RECT  2.16 49.815 41.148 50.085 ;
     RECT  77.22 49.815 96.12 50.085 ;
     RECT  2.16 50.355 41.148 50.625 ;
     RECT  77.22 50.355 96.12 50.625 ;
     RECT  2.16 50.895 41.148 51.165 ;
     RECT  77.22 50.895 96.12 51.165 ;
     RECT  2.16 51.435 41.148 51.705 ;
     RECT  77.22 51.435 96.12 51.705 ;
     RECT  2.16 51.975 41.148 52.245 ;
     RECT  77.22 51.975 96.12 52.245 ;
     RECT  2.16 52.515 41.148 52.785 ;
     RECT  77.22 52.515 96.12 52.785 ;
     RECT  2.16 53.055 41.148 53.325 ;
     RECT  77.22 53.055 96.12 53.325 ;
     RECT  2.16 53.595 41.148 53.865 ;
     RECT  77.22 53.595 96.12 53.865 ;
     RECT  2.16 54.135 41.148 54.405 ;
     RECT  77.22 54.135 96.12 54.405 ;
     RECT  2.16 54.675 41.148 54.945 ;
     RECT  77.22 54.675 96.12 54.945 ;
     RECT  2.16 55.215 41.148 55.485 ;
     RECT  77.22 55.215 96.12 55.485 ;
     RECT  2.16 55.755 41.148 56.025 ;
     RECT  77.22 55.755 96.12 56.025 ;
     RECT  2.16 56.295 41.148 56.565 ;
     RECT  77.22 56.295 96.12 56.565 ;
     RECT  2.16 56.835 41.148 57.105 ;
     RECT  77.22 56.835 96.12 57.105 ;
     RECT  2.16 57.375 41.148 57.645 ;
     RECT  77.22 57.375 96.12 57.645 ;
     RECT  2.16 57.915 41.148 58.185 ;
     RECT  77.22 57.915 96.12 58.185 ;
     RECT  2.16 58.455 41.148 58.725 ;
     RECT  77.22 58.455 96.12 58.725 ;
     RECT  2.16 58.995 41.148 59.265 ;
     RECT  77.22 58.995 96.12 59.265 ;
     RECT  2.16 59.535 41.148 59.805 ;
     RECT  77.22 59.535 96.12 59.805 ;
     RECT  2.16 60.075 41.148 60.345 ;
     RECT  77.22 60.075 96.12 60.345 ;
     RECT  2.16 60.615 41.148 60.885 ;
     RECT  77.22 60.615 96.12 60.885 ;
     RECT  2.16 61.155 41.148 61.425 ;
     RECT  77.22 61.155 96.12 61.425 ;
     RECT  2.16 61.695 41.148 61.965 ;
     RECT  77.22 61.695 96.12 61.965 ;
     RECT  2.16 62.235 41.148 62.505 ;
     RECT  77.22 62.235 96.12 62.505 ;
     RECT  2.16 62.775 96.12 63.045 ;
     RECT  2.16 63.315 96.12 63.585 ;
     RECT  2.16 63.855 96.12 64.125 ;
     RECT  2.16 64.395 96.12 64.665 ;
     RECT  2.16 64.935 96.12 65.205 ;
     RECT  2.16 65.475 96.12 65.745 ;
     RECT  2.16 66.015 96.12 66.285 ;
     RECT  2.16 66.555 96.12 66.825 ;
     RECT  2.16 67.095 96.12 67.365 ;
     RECT  2.16 67.635 96.12 67.905 ;
     RECT  2.16 68.175 96.12 68.445 ;
     RECT  2.16 68.715 96.12 68.985 ;
     RECT  2.16 69.255 96.12 69.525 ;
     RECT  2.16 69.795 96.12 70.065 ;
     RECT  2.16 70.335 96.12 70.605 ;
     RECT  2.16 70.875 96.12 71.145 ;
     RECT  2.16 71.415 96.12 71.685 ;
     RECT  2.16 71.955 96.12 72.225 ;
     RECT  2.16 72.495 96.12 72.765 ;
     RECT  2.16 73.035 96.12 73.305 ;
     RECT  2.16 73.575 96.12 73.845 ;
     RECT  2.16 74.115 96.12 74.385 ;
     RECT  2.16 74.655 96.12 74.925 ;
     RECT  2.16 75.195 96.12 75.465 ;
     RECT  2.16 75.735 96.12 76.005 ;
     RECT  2.16 76.275 96.12 76.545 ;
     RECT  2.16 76.815 96.12 77.085 ;
     RECT  2.16 77.355 96.12 77.625 ;
     RECT  2.16 77.895 96.12 78.165 ;
     RECT  2.16 78.435 96.12 78.705 ;
     RECT  2.16 78.975 96.12 79.245 ;
     RECT  2.16 79.515 96.12 79.785 ;
     RECT  2.16 80.055 96.12 80.325 ;
     RECT  2.16 80.595 96.12 80.865 ;
     RECT  2.16 81.135 96.12 81.405 ;
     RECT  2.16 81.675 96.12 81.945 ;
     RECT  2.16 82.215 96.12 82.485 ;
     RECT  2.16 82.755 96.12 83.025 ;
     RECT  2.16 83.295 96.12 83.565 ;
     RECT  2.16 83.835 96.12 84.105 ;
     RECT  2.16 84.375 41.148 84.645 ;
     RECT  77.22 84.375 96.12 84.645 ;
     RECT  2.16 84.915 41.148 85.185 ;
     RECT  77.22 84.915 96.12 85.185 ;
     RECT  2.16 85.455 41.148 85.725 ;
     RECT  77.22 85.455 96.12 85.725 ;
     RECT  2.16 85.995 41.148 86.265 ;
     RECT  77.22 85.995 96.12 86.265 ;
     RECT  2.16 86.535 41.148 86.805 ;
     RECT  77.22 86.535 96.12 86.805 ;
     RECT  2.16 87.075 41.148 87.345 ;
     RECT  77.22 87.075 96.12 87.345 ;
     RECT  2.16 87.615 41.148 87.885 ;
     RECT  77.22 87.615 96.12 87.885 ;
     RECT  2.16 88.155 41.148 88.425 ;
     RECT  77.22 88.155 96.12 88.425 ;
     RECT  2.16 88.695 41.148 88.965 ;
     RECT  77.22 88.695 96.12 88.965 ;
     RECT  2.16 89.235 41.148 89.505 ;
     RECT  77.22 89.235 96.12 89.505 ;
     RECT  2.16 89.775 41.148 90.045 ;
     RECT  77.22 89.775 96.12 90.045 ;
     RECT  2.16 90.315 41.148 90.585 ;
     RECT  77.22 90.315 96.12 90.585 ;
     RECT  2.16 90.855 41.148 91.125 ;
     RECT  77.22 90.855 96.12 91.125 ;
     RECT  2.16 91.395 41.148 91.665 ;
     RECT  77.22 91.395 96.12 91.665 ;
     RECT  2.16 91.935 41.148 92.205 ;
     RECT  77.22 91.935 96.12 92.205 ;
     RECT  2.16 92.475 41.148 92.745 ;
     RECT  77.22 92.475 96.12 92.745 ;
     RECT  2.16 93.015 41.148 93.285 ;
     RECT  77.22 93.015 96.12 93.285 ;
     RECT  2.16 93.555 41.148 93.825 ;
     RECT  77.22 93.555 96.12 93.825 ;
     RECT  2.16 94.095 41.148 94.365 ;
     RECT  77.22 94.095 96.12 94.365 ;
     RECT  2.16 94.635 41.148 94.905 ;
     RECT  77.22 94.635 96.12 94.905 ;
     RECT  2.16 95.175 41.148 95.445 ;
     RECT  77.22 95.175 96.12 95.445 ;
     RECT  2.16 95.715 41.148 95.985 ;
     RECT  77.22 95.715 96.12 95.985 ;
     RECT  2.16 96.255 41.148 96.525 ;
     RECT  77.22 96.255 96.12 96.525 ;
     RECT  2.16 96.795 41.148 97.065 ;
     RECT  77.22 96.795 96.12 97.065 ;
     RECT  2.16 97.335 41.148 97.605 ;
     RECT  77.22 97.335 96.12 97.605 ;
     RECT  2.16 97.875 41.148 98.145 ;
     RECT  77.22 97.875 96.12 98.145 ;
     RECT  2.16 98.415 41.148 98.685 ;
     RECT  77.22 98.415 96.12 98.685 ;
     RECT  2.16 98.955 41.148 99.225 ;
     RECT  77.22 98.955 96.12 99.225 ;
     RECT  2.16 99.495 41.148 99.765 ;
     RECT  77.22 99.495 96.12 99.765 ;
     RECT  2.16 100.035 41.148 100.305 ;
     RECT  77.22 100.035 96.12 100.305 ;
     RECT  2.16 100.575 41.148 100.845 ;
     RECT  77.22 100.575 96.12 100.845 ;
     RECT  2.16 101.115 41.148 101.385 ;
     RECT  77.22 101.115 96.12 101.385 ;
     RECT  2.16 101.655 41.148 101.925 ;
     RECT  77.22 101.655 96.12 101.925 ;
     RECT  2.16 102.195 41.148 102.465 ;
     RECT  77.22 102.195 96.12 102.465 ;
     RECT  2.16 102.735 41.148 103.005 ;
     RECT  77.22 102.735 96.12 103.005 ;
     RECT  2.16 103.275 41.148 103.545 ;
     RECT  77.22 103.275 96.12 103.545 ;
     RECT  2.16 103.815 41.148 104.085 ;
     RECT  77.22 103.815 96.12 104.085 ;
     RECT  2.16 104.355 41.148 104.625 ;
     RECT  77.22 104.355 96.12 104.625 ;
     RECT  2.16 104.895 41.148 105.165 ;
     RECT  77.22 104.895 96.12 105.165 ;
     RECT  2.16 105.435 41.148 105.705 ;
     RECT  77.22 105.435 96.12 105.705 ;
     RECT  2.16 105.975 96.12 106.245 ;
     RECT  2.16 106.515 96.12 106.785 ;
     RECT  2.16 107.055 96.12 107.325 ;
     RECT  2.16 107.595 96.12 107.865 ;
     RECT  2.16 108.135 96.12 108.405 ;
     RECT  2.16 108.675 96.12 108.945 ;
     RECT  2.16 109.215 96.12 109.485 ;
     RECT  2.16 109.755 96.12 110.025 ;
     RECT  2.16 110.295 96.12 110.565 ;
     RECT  2.16 110.835 96.12 111.105 ;
     RECT  2.16 111.375 96.12 111.645 ;
     RECT  2.16 111.915 96.12 112.185 ;
     RECT  2.16 112.455 96.12 112.725 ;
     RECT  2.16 112.995 96.12 113.265 ;
     RECT  2.16 113.535 96.12 113.805 ;
     RECT  2.16 114.075 96.12 114.345 ;
     RECT  2.16 114.615 96.12 114.885 ;
     RECT  2.16 115.155 96.12 115.425 ;
     RECT  2.16 115.695 96.12 115.965 ;
     RECT  2.16 116.235 96.12 116.505 ;
     RECT  2.16 116.775 96.12 117.045 ;
     RECT  2.16 117.315 96.12 117.585 ;
     RECT  2.16 117.855 96.12 118.125 ;
     RECT  2.16 118.395 96.12 118.665 ;
     RECT  2.16 118.935 96.12 119.205 ;
     RECT  2.16 119.475 96.12 119.745 ;
     RECT  2.16 120.015 96.12 120.285 ;
     RECT  2.16 120.555 96.12 120.825 ;
     RECT  2.16 121.095 96.12 121.365 ;
     RECT  2.16 121.635 96.12 121.905 ;
     RECT  2.16 122.175 96.12 122.445 ;
     RECT  2.16 122.715 96.12 122.985 ;
     RECT  2.16 123.255 96.12 123.525 ;
     RECT  2.16 123.795 96.12 124.065 ;
     RECT  2.16 124.335 96.12 124.605 ;
     RECT  2.16 124.875 96.12 125.145 ;
     RECT  2.16 125.415 96.12 125.685 ;
     RECT  2.16 125.955 96.12 126.225 ;
     RECT  2.16 126.495 96.12 126.765 ;
     RECT  2.16 127.035 96.12 127.305 ;
     RECT  2.16 127.575 41.148 127.845 ;
     RECT  77.22 127.575 96.12 127.845 ;
     RECT  2.16 128.115 41.148 128.385 ;
     RECT  77.22 128.115 96.12 128.385 ;
     RECT  2.16 128.655 41.148 128.925 ;
     RECT  77.22 128.655 96.12 128.925 ;
     RECT  2.16 129.195 41.148 129.465 ;
     RECT  77.22 129.195 96.12 129.465 ;
     RECT  2.16 129.735 41.148 130.005 ;
     RECT  77.22 129.735 96.12 130.005 ;
     RECT  2.16 130.275 41.148 130.545 ;
     RECT  77.22 130.275 96.12 130.545 ;
     RECT  2.16 130.815 41.148 131.085 ;
     RECT  77.22 130.815 96.12 131.085 ;
     RECT  2.16 131.355 41.148 131.625 ;
     RECT  77.22 131.355 96.12 131.625 ;
     RECT  2.16 131.895 41.148 132.165 ;
     RECT  77.22 131.895 96.12 132.165 ;
     RECT  2.16 132.435 41.148 132.705 ;
     RECT  77.22 132.435 96.12 132.705 ;
     RECT  2.16 132.975 41.148 133.245 ;
     RECT  77.22 132.975 96.12 133.245 ;
     RECT  2.16 133.515 41.148 133.785 ;
     RECT  77.22 133.515 96.12 133.785 ;
     RECT  2.16 134.055 41.148 134.325 ;
     RECT  77.22 134.055 96.12 134.325 ;
     RECT  2.16 134.595 41.148 134.865 ;
     RECT  77.22 134.595 96.12 134.865 ;
     RECT  2.16 135.135 41.148 135.405 ;
     RECT  77.22 135.135 96.12 135.405 ;
     RECT  2.16 135.675 41.148 135.945 ;
     RECT  77.22 135.675 96.12 135.945 ;
     RECT  2.16 136.215 41.148 136.485 ;
     RECT  77.22 136.215 96.12 136.485 ;
     RECT  2.16 136.755 41.148 137.025 ;
     RECT  77.22 136.755 96.12 137.025 ;
     RECT  2.16 137.295 41.148 137.565 ;
     RECT  77.22 137.295 96.12 137.565 ;
     RECT  2.16 137.835 41.148 138.105 ;
     RECT  77.22 137.835 96.12 138.105 ;
     RECT  2.16 138.375 41.148 138.645 ;
     RECT  77.22 138.375 96.12 138.645 ;
     RECT  2.16 138.915 41.148 139.185 ;
     RECT  77.22 138.915 96.12 139.185 ;
     RECT  2.16 139.455 41.148 139.725 ;
     RECT  77.22 139.455 96.12 139.725 ;
     RECT  2.16 139.995 41.148 140.265 ;
     RECT  77.22 139.995 96.12 140.265 ;
     RECT  2.16 140.535 41.148 140.805 ;
     RECT  77.22 140.535 96.12 140.805 ;
     RECT  2.16 141.075 41.148 141.345 ;
     RECT  77.22 141.075 96.12 141.345 ;
     RECT  2.16 141.615 41.148 141.885 ;
     RECT  77.22 141.615 96.12 141.885 ;
     RECT  2.16 142.155 41.148 142.425 ;
     RECT  77.22 142.155 96.12 142.425 ;
     RECT  2.16 142.695 41.148 142.965 ;
     RECT  77.22 142.695 96.12 142.965 ;
     RECT  2.16 143.235 41.148 143.505 ;
     RECT  77.22 143.235 96.12 143.505 ;
     RECT  2.16 143.775 41.148 144.045 ;
     RECT  77.22 143.775 96.12 144.045 ;
     RECT  2.16 144.315 41.148 144.585 ;
     RECT  77.22 144.315 96.12 144.585 ;
     RECT  2.16 144.855 41.148 145.125 ;
     RECT  77.22 144.855 96.12 145.125 ;
     RECT  2.16 145.395 41.148 145.665 ;
     RECT  77.22 145.395 96.12 145.665 ;
     RECT  2.16 145.935 41.148 146.205 ;
     RECT  77.22 145.935 96.12 146.205 ;
     RECT  2.16 146.475 41.148 146.745 ;
     RECT  77.22 146.475 96.12 146.745 ;
     RECT  2.16 147.015 41.148 147.285 ;
     RECT  77.22 147.015 96.12 147.285 ;
     RECT  2.16 147.555 41.148 147.825 ;
     RECT  77.22 147.555 96.12 147.825 ;
     RECT  2.16 148.095 41.148 148.365 ;
     RECT  77.22 148.095 96.12 148.365 ;
     RECT  2.16 148.635 41.148 148.905 ;
     RECT  77.22 148.635 96.12 148.905 ;
     RECT  2.16 149.175 96.12 149.445 ;
     RECT  2.16 149.715 96.12 149.985 ;
     RECT  2.16 150.255 96.12 150.525 ;
     RECT  2.16 150.795 96.12 151.065 ;
     RECT  2.16 151.335 96.12 151.605 ;
     RECT  2.16 151.875 96.12 152.145 ;
     RECT  2.16 152.415 96.12 152.685 ;
     RECT  2.16 152.955 96.12 153.225 ;
     RECT  2.16 153.495 96.12 153.765 ;
     RECT  2.16 154.035 96.12 154.305 ;
     RECT  2.16 154.575 96.12 154.845 ;
     RECT  2.16 155.115 96.12 155.385 ;
     RECT  2.16 155.655 96.12 155.925 ;
     RECT  2.16 156.195 96.12 156.465 ;
     RECT  2.16 156.735 96.12 157.005 ;
     RECT  2.16 157.275 96.12 157.545 ;
     RECT  2.16 157.815 96.12 158.085 ;
     RECT  2.16 158.355 96.12 158.625 ;
     RECT  2.16 158.895 96.12 159.165 ;
     RECT  2.16 159.435 96.12 159.705 ;
     RECT  2.16 159.975 96.12 160.245 ;
     RECT  2.16 160.515 96.12 160.785 ;
     RECT  2.16 161.055 96.12 161.325 ;
     RECT  2.16 161.595 96.12 161.865 ;
     RECT  2.16 162.135 96.12 162.405 ;
     RECT  2.16 162.675 96.12 162.945 ;
     RECT  2.16 163.215 96.12 163.485 ;
     RECT  2.16 163.755 96.12 164.025 ;
     RECT  2.16 164.295 96.12 164.565 ;
     RECT  2.16 164.835 96.12 165.105 ;
     RECT  2.16 165.375 96.12 165.645 ;
     RECT  2.16 165.915 96.12 166.185 ;
     RECT  2.16 166.455 96.12 166.725 ;
     RECT  2.16 166.995 96.12 167.265 ;
     RECT  2.16 167.535 96.12 167.805 ;
     RECT  2.16 168.075 96.12 168.345 ;
    LAYER M1 ;
     RECT  2.16 2.151 96.12 41.049 ;
     RECT  43.2 43.2 75.192 60.504 ;
     RECT  2.16 41.049 41.148 62.631 ;
     RECT  77.22 41.049 96.12 62.631 ;
     RECT  2.16 62.631 96.12 84.249 ;
     RECT  43.2 86.4 75.192 103.704 ;
     RECT  2.16 84.249 41.148 105.831 ;
     RECT  77.22 84.249 96.12 105.831 ;
     RECT  2.16 105.831 96.12 127.449 ;
     RECT  43.2 129.6 75.192 146.904 ;
     RECT  2.16 127.449 41.148 149.031 ;
     RECT  77.22 127.449 96.12 149.031 ;
     RECT  2.16 149.031 96.12 168.489 ;
    LAYER M2 ;
     RECT  0.103 42.336 0.175 42.714 ;
     RECT  0.175 42.228 0.275 42.714 ;
     RECT  0.103 32.976 0.535 33.804 ;
     RECT  0.103 34.668 0.535 34.686 ;
     RECT  0.103 44.388 0.535 44.406 ;
     RECT  0.103 45.306 0.535 45.324 ;
     RECT  0.103 84.888 0.535 86.634 ;
     RECT  0.103 118.206 2.155 118.224 ;
     RECT  0.535 32.346 2.16 34.686 ;
     RECT  0.103 35.856 2.16 35.874 ;
     RECT  0.535 40.986 2.16 41.004 ;
     RECT  0.275 42.696 2.16 42.714 ;
     RECT  0.535 44.388 2.16 45.324 ;
     RECT  0.103 74.466 2.16 75.024 ;
     RECT  0.103 76.356 2.16 78.534 ;
     RECT  0.535 84.888 2.16 86.904 ;
     RECT  0.103 88.776 2.16 88.794 ;
     RECT  2.155 118.206 2.16 118.386 ;
     RECT  0.103 120.096 2.16 120.654 ;
     RECT  0.103 121.878 2.16 122.274 ;
     RECT  0.103 130.518 2.16 131.076 ;
     RECT  37.831 170.586 37.903 170.604 ;
     RECT  37.903 170.514 38.003 170.604 ;
     RECT  38.003 170.586 38.767 170.604 ;
     RECT  38.767 170.514 38.903 170.604 ;
     RECT  38.903 170.586 38.975 170.604 ;
     RECT  2.16 2.151 41.148 168.489 ;
     RECT  41.148 2.151 41.243 43.866 ;
     RECT  41.243 2.151 41.315 43.29 ;
     RECT  41.148 87.156 41.315 100.872 ;
     RECT  41.148 134.298 41.315 140.724 ;
     RECT  41.148 51.21 41.351 56.484 ;
     RECT  41.148 130.284 41.351 130.302 ;
     RECT  41.315 42.03 41.387 43.29 ;
     RECT  41.148 58.086 41.387 58.284 ;
     RECT  41.148 131.058 41.387 132.228 ;
     RECT  41.387 42.3 41.423 43.29 ;
     RECT  41.315 98.046 41.423 100.872 ;
     RECT  41.148 143.946 41.423 144.684 ;
     RECT  41.315 137.304 41.459 140.724 ;
     RECT  41.423 42.3 41.495 43.254 ;
     RECT  41.351 51.21 41.495 54.594 ;
     RECT  41.423 98.046 41.495 99.486 ;
     RECT  41.423 100.854 41.495 100.872 ;
     RECT  41.495 42.3 41.531 43.164 ;
     RECT  41.495 53.766 41.531 54.594 ;
     RECT  41.495 99.396 41.531 99.486 ;
     RECT  41.351 55.386 41.567 56.484 ;
     RECT  41.495 98.046 41.567 98.604 ;
     RECT  41.315 87.156 41.603 97.254 ;
     RECT  41.567 98.586 41.603 98.604 ;
     RECT  41.459 140.616 41.603 140.724 ;
     RECT  41.603 90.828 41.639 97.254 ;
     RECT  41.387 131.058 41.639 131.076 ;
     RECT  41.315 134.298 41.639 136.206 ;
     RECT  41.603 87.156 41.675 89.766 ;
     RECT  41.639 91.908 41.675 97.254 ;
     RECT  41.387 131.94 41.711 132.228 ;
     RECT  41.148 44.622 41.927 45.72 ;
     RECT  41.567 55.656 41.963 56.484 ;
     RECT  41.675 92.106 41.963 97.254 ;
     RECT  41.148 103.752 41.999 104.688 ;
     RECT  41.531 42.651 42.035 43.164 ;
     RECT  41.495 51.21 42.179 52.974 ;
     RECT  41.963 92.106 42.179 96.246 ;
     RECT  41.459 137.304 42.179 139.644 ;
     RECT  41.148 147.222 42.187 147.888 ;
     RECT  41.675 89.28 42.215 89.766 ;
     RECT  42.179 92.106 42.215 93.744 ;
     RECT  42.179 94.536 42.215 96.246 ;
     RECT  41.639 134.298 42.215 135.09 ;
     RECT  42.179 137.646 42.215 139.644 ;
     RECT  41.423 144.666 42.215 144.684 ;
     RECT  42.179 51.21 42.251 52.776 ;
     RECT  41.675 87.156 42.251 88.146 ;
     RECT  42.215 92.106 42.251 93.348 ;
     RECT  42.215 137.646 42.251 137.664 ;
     RECT  41.148 105.831 42.259 127.449 ;
     RECT  42.251 92.178 42.287 93.348 ;
     RECT  41.148 128.781 42.295 129.294 ;
     RECT  42.187 147.096 42.439 147.888 ;
     RECT  41.927 44.622 42.467 45.522 ;
     RECT  42.295 128.7 42.475 129.294 ;
     RECT  42.475 128.664 42.575 129.294 ;
     RECT  42.259 105.831 42.583 127.494 ;
     RECT  42.583 105.678 42.619 127.494 ;
     RECT  42.575 129.204 42.619 129.294 ;
     RECT  41.148 60.552 42.655 61.65 ;
     RECT  41.148 62.631 42.655 84.249 ;
     RECT  42.619 105.516 42.655 127.494 ;
     RECT  41.148 149.031 42.727 168.489 ;
     RECT  42.655 60.552 42.755 84.249 ;
     RECT  42.655 105.444 42.755 127.494 ;
     RECT  42.755 62.442 42.791 84.249 ;
     RECT  42.755 105.642 42.791 127.494 ;
     RECT  41.148 141.516 43.015 142.344 ;
     RECT  42.727 148.95 43.087 168.489 ;
     RECT  42.035 42.732 43.2 43.164 ;
     RECT  42.467 44.622 43.2 45.216 ;
     RECT  42.251 51.246 43.2 52.776 ;
     RECT  41.531 53.766 43.2 54.504 ;
     RECT  41.963 55.656 43.2 55.674 ;
     RECT  41.963 56.466 43.2 56.484 ;
     RECT  41.387 58.086 43.2 58.104 ;
     RECT  42.755 60.552 43.2 61.65 ;
     RECT  41.148 86.04 43.2 86.364 ;
     RECT  42.251 87.156 43.2 87.912 ;
     RECT  42.215 89.478 43.2 89.496 ;
     RECT  41.639 90.828 43.2 90.846 ;
     RECT  42.287 92.214 43.2 93.348 ;
     RECT  42.215 95.076 43.2 96.246 ;
     RECT  41.963 97.146 43.2 97.254 ;
     RECT  43.015 98.586 43.2 98.604 ;
     RECT  41.531 99.396 43.2 99.414 ;
     RECT  42.583 102.636 43.2 102.654 ;
     RECT  41.999 103.752 43.2 104.616 ;
     RECT  42.619 129.204 43.2 129.564 ;
     RECT  41.711 131.94 43.2 131.958 ;
     RECT  41.148 133.182 43.2 133.344 ;
     RECT  42.215 134.946 43.2 134.964 ;
     RECT  41.639 136.188 43.2 136.206 ;
     RECT  42.215 138.501 43.2 139.644 ;
     RECT  41.603 140.616 43.2 140.634 ;
     RECT  43.015 141.516 43.2 142.488 ;
     RECT  42.439 147.06 43.2 147.888 ;
     RECT  42.799 128.286 43.259 128.304 ;
     RECT  42.791 105.678 43.367 127.494 ;
     RECT  43.2 86.04 47.263 104.616 ;
     RECT  43.367 105.678 47.263 127.449 ;
     RECT  43.087 148.914 48.127 168.489 ;
     RECT  42.791 62.514 50.639 84.249 ;
     RECT  43.2 129.204 50.827 147.888 ;
     RECT  48.127 148.878 50.827 168.489 ;
     RECT  41.148 85.23 65.255 85.248 ;
     RECT  50.639 62.586 74.659 84.249 ;
     RECT  47.263 86.04 74.659 127.449 ;
     RECT  74.659 62.478 74.839 84.249 ;
     RECT  43.2 42.732 75.192 61.65 ;
     RECT  74.659 86.04 75.192 127.494 ;
     RECT  50.827 129.204 75.192 168.489 ;
     RECT  74.839 62.478 75.271 84.294 ;
     RECT  75.192 103.752 75.271 127.494 ;
     RECT  75.192 47.898 75.335 50.148 ;
     RECT  75.192 52.992 75.335 54.738 ;
     RECT  75.192 142.506 75.335 142.524 ;
     RECT  75.192 58.698 75.371 58.986 ;
     RECT  75.271 62.478 75.371 85.014 ;
     RECT  75.192 146.106 75.371 168.489 ;
     RECT  75.192 90.126 75.407 90.81 ;
     RECT  75.371 58.77 75.551 58.986 ;
     RECT  75.192 88.776 75.587 88.794 ;
     RECT  75.551 58.851 75.623 58.986 ;
     RECT  75.371 62.478 75.623 84.942 ;
     RECT  75.271 103.752 75.659 127.53 ;
     RECT  75.192 131.796 75.731 132.894 ;
     RECT  75.731 131.976 75.803 132.894 ;
     RECT  75.623 62.631 75.875 84.402 ;
     RECT  75.192 99.126 76.063 99.144 ;
     RECT  75.335 52.992 76.099 54.432 ;
     RECT  75.192 97.38 76.099 97.668 ;
     RECT  76.063 141.588 76.135 141.606 ;
     RECT  76.099 52.992 76.171 54.972 ;
     RECT  76.099 97.38 76.171 98.172 ;
     RECT  76.063 99.036 76.171 99.144 ;
     RECT  76.171 52.992 76.243 55.512 ;
     RECT  75.407 90.126 76.315 90.144 ;
     RECT  75.803 132.876 76.315 132.894 ;
     RECT  75.192 133.866 76.315 136.782 ;
     RECT  75.335 48.276 76.351 50.148 ;
     RECT  76.351 47.592 76.387 50.544 ;
     RECT  76.351 93.798 76.387 93.816 ;
     RECT  75.192 94.572 76.387 94.59 ;
     RECT  75.192 96.534 76.387 96.552 ;
     RECT  76.171 97.38 76.387 99.144 ;
     RECT  76.315 132.876 76.387 136.782 ;
     RECT  75.192 101.736 76.639 101.754 ;
     RECT  75.192 139.932 76.639 140.634 ;
     RECT  76.135 141.588 76.639 142.074 ;
     RECT  76.243 52.992 76.675 56.088 ;
     RECT  76.675 100.656 76.747 100.674 ;
     RECT  75.192 129.204 76.783 130.23 ;
     RECT  76.783 129.132 76.855 130.23 ;
     RECT  76.351 91.476 76.927 91.494 ;
     RECT  76.387 93.096 76.927 99.144 ;
     RECT  75.192 42.732 77.215 43.164 ;
     RECT  76.387 132.876 77.215 138.87 ;
     RECT  76.639 139.932 77.215 142.074 ;
     RECT  41.315 2.151 77.22 41.049 ;
     RECT  77.215 42.066 77.22 43.164 ;
     RECT  75.192 44.154 77.22 44.91 ;
     RECT  75.192 46.656 77.22 46.674 ;
     RECT  76.387 47.592 77.22 52.164 ;
     RECT  76.675 52.992 77.22 56.79 ;
     RECT  75.623 58.932 77.22 58.986 ;
     RECT  75.192 60.552 77.22 61.65 ;
     RECT  75.875 62.631 77.22 84.249 ;
     RECT  75.192 86.04 77.22 86.364 ;
     RECT  75.192 87.156 77.22 87.174 ;
     RECT  76.315 89.856 77.22 90.144 ;
     RECT  76.927 91.476 77.22 99.144 ;
     RECT  76.747 100.512 77.22 100.674 ;
     RECT  76.639 101.736 77.22 102.384 ;
     RECT  75.659 103.752 77.22 127.494 ;
     RECT  76.855 129.096 77.22 130.23 ;
     RECT  76.927 131.166 77.22 131.184 ;
     RECT  75.803 131.976 77.22 131.994 ;
     RECT  77.215 132.876 77.22 142.074 ;
     RECT  76.387 142.866 77.22 142.884 ;
     RECT  76.675 144.252 77.22 144.27 ;
     RECT  75.371 146.106 77.22 146.124 ;
     RECT  75.371 147.06 77.22 168.489 ;
     RECT  77.22 2.151 96.12 168.489 ;
     RECT  96.12 57.618 96.287 57.636 ;
     RECT  96.12 40.446 96.431 40.896 ;
     RECT  96.12 82.998 96.431 83.214 ;
     RECT  96.12 42.498 96.935 42.624 ;
     RECT  96.12 99.468 97.331 100.836 ;
     RECT  96.12 84.348 97.439 85.176 ;
     RECT  96.431 40.878 97.475 40.896 ;
     RECT  96.12 41.688 97.475 41.706 ;
     RECT  96.935 42.498 97.475 42.516 ;
     RECT  96.12 54.918 97.475 56.826 ;
     RECT  96.12 82.188 97.475 82.206 ;
     RECT  96.431 82.998 97.475 83.016 ;
     RECT  97.439 84.348 97.475 84.366 ;
     RECT  97.439 85.158 97.475 85.176 ;
     RECT  96.12 97.848 97.475 98.136 ;
     RECT  97.331 99.468 97.475 100.026 ;
     RECT  97.331 100.818 97.475 100.836 ;
     RECT  96.12 125.154 97.475 125.406 ;
     RECT  96.12 139.158 97.475 139.176 ;
     RECT  98.167 97.308 98.267 97.326 ;
    LAYER M3 ;
     RECT  2.415 2.143 2.505 2.413 ;
     RECT  5.115 2.143 5.205 2.413 ;
     RECT  7.815 2.143 7.905 2.413 ;
     RECT  10.515 2.143 10.605 2.413 ;
     RECT  13.215 2.143 13.305 2.413 ;
     RECT  15.915 2.143 16.005 2.413 ;
     RECT  18.615 2.143 18.705 2.413 ;
     RECT  21.315 2.143 21.405 2.413 ;
     RECT  24.015 2.143 24.105 2.413 ;
     RECT  26.715 2.143 26.805 2.413 ;
     RECT  29.415 2.143 29.505 2.413 ;
     RECT  32.115 2.143 32.205 2.413 ;
     RECT  34.815 2.143 34.905 2.413 ;
     RECT  37.515 2.143 37.605 2.413 ;
     RECT  40.215 2.143 40.305 2.413 ;
     RECT  42.915 2.143 43.005 2.413 ;
     RECT  45.615 2.143 45.705 2.413 ;
     RECT  48.315 2.143 48.405 2.413 ;
     RECT  51.015 2.143 51.105 2.413 ;
     RECT  53.715 2.143 53.805 2.413 ;
     RECT  56.415 2.143 56.505 2.413 ;
     RECT  59.115 2.143 59.205 2.413 ;
     RECT  61.815 2.143 61.905 2.413 ;
     RECT  64.515 2.143 64.605 2.413 ;
     RECT  67.215 2.143 67.305 2.413 ;
     RECT  69.915 2.143 70.005 2.413 ;
     RECT  72.615 2.143 72.705 2.413 ;
     RECT  75.315 2.143 75.405 2.413 ;
     RECT  78.015 2.143 78.105 2.413 ;
     RECT  80.715 2.143 80.805 2.413 ;
     RECT  83.415 2.143 83.505 2.413 ;
     RECT  86.115 2.143 86.205 2.413 ;
     RECT  88.815 2.143 88.905 2.413 ;
     RECT  91.515 2.143 91.605 2.413 ;
     RECT  94.215 2.143 94.305 2.413 ;
     RECT  5.115 2.413 5.397 31.621 ;
     RECT  3.42 31.675 3.438 31.723 ;
     RECT  3.42 31.723 3.69 31.729 ;
     RECT  4.644 31.621 5.397 31.729 ;
     RECT  3.42 31.729 5.397 31.765 ;
     RECT  3.42 31.765 5.454 31.801 ;
     RECT  6.876 31.765 6.894 31.801 ;
     RECT  7.815 2.413 8.097 31.801 ;
     RECT  0.144 31.723 0.162 31.853 ;
     RECT  6.876 31.801 8.097 31.919 ;
     RECT  2.415 2.413 2.697 32.059 ;
     RECT  3.42 31.801 5.742 32.059 ;
     RECT  2.415 32.059 5.742 32.099 ;
     RECT  3.456 32.099 5.742 32.161 ;
     RECT  9.432 32.071 9.45 32.297 ;
     RECT  6.876 31.919 7.074 32.305 ;
     RECT  7.815 31.919 8.097 32.305 ;
     RECT  7.815 32.305 8.478 32.341 ;
     RECT  0.54 32.251 0.558 32.369 ;
     RECT  2.415 32.099 2.697 32.395 ;
     RECT  3.456 32.161 5.85 32.431 ;
     RECT  2.304 32.395 2.697 32.459 ;
     RECT  3.456 32.431 6.066 32.587 ;
     RECT  6.804 32.305 7.074 32.587 ;
     RECT  7.815 32.341 8.658 32.611 ;
     RECT  0.144 32.587 0.342 32.827 ;
     RECT  3.456 32.587 7.074 32.827 ;
     RECT  2.415 32.459 2.697 32.881 ;
     RECT  3.42 32.827 7.074 32.881 ;
     RECT  7.815 32.611 9.054 32.881 ;
     RECT  0.108 32.827 0.342 33.005 ;
     RECT  42.915 2.413 43.197 33.007 ;
     RECT  42.66 33.007 43.197 33.043 ;
     RECT  42.336 33.043 43.197 33.151 ;
     RECT  41.292 32.269 41.31 33.421 ;
     RECT  42.12 33.151 43.197 33.421 ;
     RECT  38.772 33.511 38.79 33.611 ;
     RECT  0.108 33.005 0.126 33.809 ;
     RECT  2.415 32.881 9.054 33.961 ;
     RECT  0.54 33.961 0.558 34.013 ;
     RECT  2.415 33.961 9.306 34.079 ;
     RECT  38.808 33.655 38.826 34.187 ;
     RECT  2.415 34.079 9.162 34.223 ;
     RECT  2.415 34.223 8.874 34.529 ;
     RECT  0.108 34.555 0.126 34.691 ;
     RECT  2.415 34.529 8.802 35.131 ;
     RECT  38.772 35.203 38.79 35.303 ;
     RECT  2.304 35.131 8.802 35.509 ;
     RECT  0.144 35.467 0.162 35.597 ;
     RECT  2.304 35.509 8.874 35.743 ;
     RECT  0.108 35.707 0.126 35.879 ;
     RECT  2.304 35.743 9.162 36.149 ;
     RECT  2.304 36.149 8.658 36.269 ;
     RECT  2.415 36.269 8.658 36.275 ;
     RECT  6.804 36.275 8.658 36.509 ;
     RECT  38.808 36.481 38.826 36.653 ;
     RECT  6.804 36.509 7.074 36.689 ;
     RECT  2.415 36.275 6.066 36.779 ;
     RECT  4.608 36.779 6.066 37.319 ;
     RECT  38.772 37.291 38.79 37.427 ;
     RECT  94.215 2.413 94.497 37.867 ;
     RECT  5.115 37.319 6.066 37.931 ;
     RECT  95.904 37.831 95.922 37.963 ;
     RECT  41.292 33.421 43.197 38.003 ;
     RECT  94.032 37.867 94.497 38.059 ;
     RECT  94.032 38.059 94.698 38.101 ;
     RECT  95.616 37.963 95.922 38.101 ;
     RECT  94.032 38.101 95.922 38.155 ;
     RECT  41.544 38.003 43.197 38.551 ;
     RECT  93.996 38.155 95.922 38.551 ;
     RECT  2.415 36.779 3.618 38.579 ;
     RECT  41.544 38.551 43.254 38.669 ;
     RECT  93.852 38.551 95.922 38.669 ;
     RECT  93.852 38.669 95.778 38.821 ;
     RECT  92.736 38.731 92.754 39.091 ;
     RECT  93.492 38.821 95.778 39.091 ;
     RECT  75.315 2.413 75.597 39.181 ;
     RECT  91.515 2.413 91.797 39.289 ;
     RECT  7.056 36.689 7.074 39.353 ;
     RECT  91.44 39.289 91.797 39.361 ;
     RECT  92.736 39.091 95.778 39.361 ;
     RECT  5.115 37.931 6.03 39.389 ;
     RECT  86.115 2.413 86.397 39.451 ;
     RECT  91.44 39.361 95.778 39.559 ;
     RECT  91.296 39.559 95.778 39.589 ;
     RECT  91.116 39.589 95.778 39.631 ;
     RECT  7.815 36.509 8.658 39.691 ;
     RECT  82.656 39.451 82.674 39.749 ;
     RECT  86.115 39.451 86.67 39.749 ;
     RECT  90.072 39.523 90.09 39.865 ;
     RECT  91.116 39.631 95.814 39.865 ;
     RECT  90.072 39.865 95.814 39.883 ;
     RECT  90.072 39.883 95.922 39.893 ;
     RECT  78.015 2.413 78.297 39.901 ;
     RECT  7.416 39.691 8.658 39.917 ;
     RECT  78.015 39.901 78.678 40.019 ;
     RECT  2.415 38.579 3.402 40.163 ;
     RECT  7.815 39.917 8.658 40.199 ;
     RECT  75.315 39.181 75.834 40.405 ;
     RECT  90.432 39.893 95.922 40.441 ;
     RECT  90.432 40.441 96.426 40.493 ;
     RECT  86.115 39.749 86.634 40.531 ;
     RECT  45.615 2.413 45.897 40.555 ;
     RECT  45.615 40.555 46.53 40.711 ;
     RECT  64.515 2.413 64.797 40.711 ;
     RECT  75.24 40.405 75.834 40.711 ;
     RECT  83.415 2.413 83.697 40.711 ;
     RECT  86.115 40.531 86.67 40.739 ;
     RECT  41.544 38.669 43.197 40.787 ;
     RECT  45.615 40.711 46.854 40.787 ;
     RECT  48.315 2.413 48.597 40.787 ;
     RECT  51.015 2.413 51.297 40.787 ;
     RECT  53.715 2.413 53.997 40.787 ;
     RECT  56.415 2.413 56.697 40.787 ;
     RECT  59.115 2.413 59.397 40.787 ;
     RECT  61.815 2.413 62.097 40.787 ;
     RECT  67.215 2.413 67.497 40.787 ;
     RECT  69.915 2.413 70.197 40.787 ;
     RECT  72.615 2.413 72.897 40.787 ;
     RECT  59.115 40.787 59.205 40.801 ;
     RECT  88.815 2.413 89.097 40.801 ;
     RECT  46.512 40.787 46.854 40.829 ;
     RECT  57.42 40.711 57.438 40.837 ;
     RECT  83.415 40.711 84.078 40.865 ;
     RECT  46.512 40.829 46.53 40.877 ;
     RECT  57.312 40.837 57.546 40.877 ;
     RECT  58.86 40.801 59.205 40.877 ;
     RECT  80.715 2.413 80.997 40.909 ;
     RECT  57.528 40.877 57.546 40.925 ;
     RECT  40.215 2.413 40.497 40.939 ;
     RECT  40.215 40.939 40.662 40.981 ;
     RECT  75.132 40.711 75.834 40.981 ;
     RECT  0.54 40.891 0.558 41.009 ;
     RECT  64.515 40.711 65.466 41.009 ;
     RECT  82.656 40.873 82.674 41.009 ;
     RECT  64.515 41.009 65.178 41.021 ;
     RECT  45.615 40.787 45.705 41.057 ;
     RECT  48.315 40.787 48.405 41.057 ;
     RECT  51.015 40.787 51.105 41.057 ;
     RECT  53.715 40.787 53.805 41.057 ;
     RECT  56.415 40.787 56.505 41.057 ;
     RECT  59.115 40.877 59.205 41.057 ;
     RECT  61.815 40.787 61.905 41.057 ;
     RECT  64.515 41.021 64.605 41.057 ;
     RECT  67.215 40.787 67.305 41.057 ;
     RECT  69.915 40.787 70.005 41.057 ;
     RECT  72.615 40.787 72.705 41.057 ;
     RECT  3.492 40.981 3.51 41.071 ;
     RECT  7.815 40.199 8.097 41.071 ;
     RECT  80.715 40.909 81.522 41.099 ;
     RECT  4.284 40.801 4.302 41.107 ;
     RECT  5.115 39.389 5.397 41.107 ;
     RECT  88.815 40.801 89.694 41.135 ;
     RECT  4.284 41.107 5.397 41.179 ;
     RECT  6.444 41.107 6.462 41.179 ;
     RECT  86.115 40.739 86.634 41.207 ;
     RECT  7.815 41.071 8.154 41.215 ;
     RECT  40.215 40.981 40.806 41.251 ;
     RECT  39.852 41.251 40.806 41.309 ;
     RECT  39.924 41.309 40.806 41.341 ;
     RECT  41.544 40.787 43.146 41.341 ;
     RECT  7.344 41.215 8.154 41.371 ;
     RECT  10.515 2.413 10.797 41.449 ;
     RECT  2.415 40.163 2.697 41.467 ;
     RECT  90.432 40.493 95.922 41.485 ;
     RECT  2.376 41.467 2.697 41.515 ;
     RECT  3.456 41.071 3.51 41.515 ;
     RECT  4.284 41.179 6.462 41.521 ;
     RECT  7.344 41.371 8.262 41.521 ;
     RECT  10.515 41.449 10.854 41.549 ;
     RECT  2.376 41.515 3.51 41.611 ;
     RECT  39.924 41.341 43.146 41.639 ;
     RECT  75.132 40.981 76.05 41.645 ;
     RECT  2.304 41.611 3.51 41.648 ;
     RECT  38.772 41.251 38.79 41.783 ;
     RECT  90.288 41.485 95.922 41.837 ;
     RECT  2.376 41.648 3.51 41.881 ;
     RECT  4.284 41.521 8.262 41.881 ;
     RECT  2.376 41.881 8.262 41.909 ;
     RECT  76.86 40.981 76.878 42.061 ;
     RECT  78.015 40.019 78.297 42.061 ;
     RECT  10.515 41.549 10.818 42.089 ;
     RECT  78.015 42.061 78.93 42.151 ;
     RECT  0.144 41.035 0.162 42.187 ;
     RECT  0.144 42.187 0.198 42.223 ;
     RECT  2.415 41.909 8.262 42.223 ;
     RECT  78.015 42.151 79.002 42.251 ;
     RECT  0.144 42.223 0.27 42.269 ;
     RECT  39.348 42.061 39.366 42.287 ;
     RECT  0.144 42.269 0.198 42.331 ;
     RECT  0.108 42.331 0.198 42.359 ;
     RECT  86.115 41.207 86.397 42.421 ;
     RECT  2.415 42.223 8.874 42.449 ;
     RECT  97.452 40.603 97.47 42.521 ;
     RECT  40.14 41.639 43.146 42.529 ;
     RECT  86.115 42.421 86.67 42.565 ;
     RECT  90.612 41.837 95.922 42.565 ;
     RECT  88.815 41.135 89.097 42.571 ;
     RECT  85.608 42.565 86.67 42.593 ;
     RECT  90.252 42.565 95.994 42.605 ;
     RECT  96.912 42.601 96.93 42.653 ;
     RECT  76.86 42.061 77.238 42.691 ;
     RECT  90.252 42.605 95.922 42.701 ;
     RECT  0.108 42.359 0.126 42.719 ;
     RECT  88.776 42.571 89.097 42.719 ;
     RECT  90.612 42.701 95.922 42.719 ;
     RECT  76.86 42.691 77.274 42.727 ;
     RECT  78.015 42.251 78.297 42.727 ;
     RECT  85.608 42.593 86.397 42.791 ;
     RECT  88.815 42.719 89.097 42.871 ;
     RECT  98.1 42.763 98.118 42.893 ;
     RECT  2.415 42.449 8.55 42.899 ;
     RECT  3.42 42.899 8.55 42.989 ;
     RECT  39.852 42.529 43.146 43.069 ;
     RECT  3.42 42.989 6.93 43.133 ;
     RECT  38.772 42.763 38.79 43.133 ;
     RECT  39.78 43.069 43.146 43.141 ;
     RECT  39.672 43.141 43.146 43.2 ;
     RECT  75.24 41.645 76.05 43.2 ;
     RECT  7.74 42.989 8.55 43.267 ;
     RECT  88.815 42.871 89.73 43.295 ;
     RECT  0.144 43.195 0.162 43.325 ;
     RECT  7.74 43.267 8.982 43.375 ;
     RECT  90.648 42.719 95.922 43.501 ;
     RECT  7.74 43.375 9.45 43.529 ;
     RECT  90.18 43.501 95.922 43.565 ;
     RECT  9.432 43.529 9.45 43.637 ;
     RECT  3.42 43.133 6.858 43.709 ;
     RECT  88.815 43.295 89.262 43.709 ;
     RECT  2.415 42.899 2.697 43.771 ;
     RECT  6.48 43.709 6.858 43.799 ;
     RECT  34.815 2.413 35.097 43.951 ;
     RECT  6.696 43.799 6.858 44.041 ;
     RECT  90.18 43.565 90.198 44.059 ;
     RECT  7.74 43.529 8.622 44.069 ;
     RECT  76.86 42.727 78.297 44.107 ;
     RECT  86.115 42.791 86.397 44.107 ;
     RECT  10.515 42.089 10.797 44.149 ;
     RECT  86.115 44.107 86.67 44.237 ;
     RECT  2.304 43.771 2.697 44.249 ;
     RECT  10.515 44.149 10.854 44.249 ;
     RECT  34.776 43.951 35.097 44.249 ;
     RECT  39.672 43.2 76.05 44.339 ;
     RECT  0.144 44.107 0.162 44.347 ;
     RECT  90.936 43.565 95.922 44.381 ;
     RECT  2.415 44.249 2.697 44.383 ;
     RECT  3.42 43.709 5.67 44.383 ;
     RECT  7.815 44.069 8.622 44.419 ;
     RECT  6.696 44.041 6.966 44.483 ;
     RECT  0.108 44.347 0.162 44.491 ;
     RECT  90.108 44.059 90.198 44.491 ;
     RECT  90.936 44.381 95.85 44.491 ;
     RECT  83.415 40.865 83.697 44.581 ;
     RECT  76.86 44.107 78.678 44.587 ;
     RECT  90.108 44.491 95.85 44.609 ;
     RECT  90.612 44.609 95.85 44.621 ;
     RECT  90.612 44.621 95.742 44.645 ;
     RECT  2.415 44.383 5.67 44.689 ;
     RECT  2.415 44.689 5.706 44.761 ;
     RECT  6.696 44.483 6.93 44.761 ;
     RECT  86.115 44.237 86.397 44.761 ;
     RECT  38.808 44.455 38.826 44.851 ;
     RECT  7.815 44.419 9.162 44.879 ;
     RECT  83.232 44.581 83.697 44.909 ;
     RECT  0.108 44.491 0.342 44.917 ;
     RECT  2.415 44.761 6.93 44.951 ;
     RECT  0.108 44.917 0.558 44.957 ;
     RECT  2.415 44.951 2.754 44.957 ;
     RECT  38.772 44.851 38.826 44.987 ;
     RECT  80.715 41.099 80.997 45.019 ;
     RECT  81.756 43.411 81.774 45.019 ;
     RECT  85.752 44.761 86.397 45.019 ;
     RECT  80.715 45.019 81.774 45.059 ;
     RECT  3.636 44.951 6.93 45.149 ;
     RECT  6.912 45.149 6.93 45.197 ;
     RECT  85.752 45.019 86.49 45.259 ;
     RECT  38.808 44.987 38.826 45.301 ;
     RECT  39.78 44.339 76.05 45.301 ;
     RECT  0.108 44.957 0.126 45.329 ;
     RECT  7.815 44.879 8.37 45.329 ;
     RECT  2.415 44.957 2.697 45.355 ;
     RECT  80.715 45.059 80.997 45.355 ;
     RECT  2.304 45.355 2.697 45.419 ;
     RECT  3.636 45.149 5.922 45.419 ;
     RECT  80.604 45.355 80.997 45.419 ;
     RECT  34.815 44.249 35.097 45.427 ;
     RECT  7.815 45.329 8.19 45.455 ;
     RECT  6.984 45.301 7.074 45.491 ;
     RECT  85.752 45.259 86.706 45.499 ;
     RECT  4.284 45.419 5.886 45.527 ;
     RECT  38.808 45.301 76.05 45.527 ;
     RECT  76.86 44.587 78.786 45.533 ;
     RECT  34.776 45.427 35.097 45.563 ;
     RECT  85.752 45.499 86.814 45.563 ;
     RECT  85.752 45.563 86.634 45.581 ;
     RECT  84.528 43.843 84.546 45.691 ;
     RECT  85.752 45.581 86.397 45.691 ;
     RECT  90.612 44.645 95.166 45.691 ;
     RECT  4.608 45.527 5.886 45.725 ;
     RECT  76.86 45.533 78.678 45.725 ;
     RECT  7.056 45.491 7.074 45.797 ;
     RECT  90.396 45.691 95.166 45.821 ;
     RECT  90.792 45.821 95.166 45.959 ;
     RECT  80.715 45.419 80.997 45.979 ;
     RECT  81.756 45.059 81.774 45.979 ;
     RECT  90.792 45.959 94.842 46.013 ;
     RECT  82.656 45.019 82.674 46.027 ;
     RECT  90.828 46.013 94.842 46.031 ;
     RECT  84.528 45.691 86.397 46.061 ;
     RECT  39.348 45.527 76.05 46.109 ;
     RECT  80.715 45.979 81.774 46.109 ;
     RECT  82.512 46.027 82.674 46.109 ;
     RECT  84.528 46.061 84.978 46.109 ;
     RECT  82.512 46.109 82.53 46.139 ;
     RECT  5.115 45.725 5.886 46.229 ;
     RECT  39.348 46.109 75.834 46.229 ;
     RECT  90.828 46.031 94.497 46.301 ;
     RECT  77.22 45.725 78.678 46.493 ;
     RECT  93.492 46.301 94.497 46.589 ;
     RECT  90.828 46.301 92.718 46.769 ;
     RECT  83.415 44.909 83.697 46.777 ;
     RECT  84.528 46.109 84.942 46.777 ;
     RECT  90.828 46.769 92.574 46.795 ;
     RECT  77.256 46.493 78.678 46.973 ;
     RECT  83.415 46.777 84.942 47.047 ;
     RECT  90.648 46.795 92.574 47.069 ;
     RECT  77.796 46.973 78.678 47.083 ;
     RECT  83.415 47.047 84.978 47.083 ;
     RECT  90.648 47.069 92.538 47.111 ;
     RECT  81.756 46.109 81.774 47.117 ;
     RECT  79.632 46.747 79.65 47.131 ;
     RECT  80.715 46.109 80.997 47.131 ;
     RECT  82.728 47.083 84.978 47.131 ;
     RECT  77.796 47.083 78.75 47.213 ;
     RECT  82.656 47.131 84.978 47.219 ;
     RECT  91.08 47.111 92.538 47.219 ;
     RECT  77.796 47.213 78.678 47.261 ;
     RECT  82.656 47.219 84.546 47.261 ;
     RECT  80.715 47.131 81.162 47.309 ;
     RECT  82.656 47.261 82.674 47.309 ;
     RECT  83.415 47.261 84.546 47.453 ;
     RECT  79.632 47.131 79.794 47.489 ;
     RECT  79.632 47.489 79.65 47.579 ;
     RECT  39.852 46.229 75.834 47.587 ;
     RECT  84.528 47.453 84.546 47.645 ;
     RECT  93.528 46.589 94.497 47.803 ;
     RECT  93.384 47.803 94.497 47.849 ;
     RECT  39.852 47.587 76.374 48.701 ;
     RECT  39.888 48.701 76.374 48.811 ;
     RECT  77.796 47.261 78.297 48.811 ;
     RECT  39.888 48.811 78.297 48.989 ;
     RECT  39.888 48.989 76.41 50.045 ;
     RECT  39.888 50.045 42.462 50.125 ;
     RECT  39.708 50.125 42.462 50.141 ;
     RECT  92.52 47.219 92.538 50.155 ;
     RECT  93.42 47.849 94.497 50.155 ;
     RECT  43.2 50.045 76.41 50.237 ;
     RECT  39.708 50.141 41.022 50.359 ;
     RECT  39.492 50.359 41.022 50.395 ;
     RECT  92.52 50.155 94.497 50.717 ;
     RECT  38.916 50.395 41.022 50.731 ;
     RECT  76.356 50.237 76.41 50.813 ;
     RECT  91.08 47.219 91.797 50.819 ;
     RECT  38.52 50.731 41.022 50.891 ;
     RECT  76.392 50.813 76.41 50.971 ;
     RECT  38.7 50.891 41.022 51.067 ;
     RECT  41.904 50.141 42.462 51.067 ;
     RECT  76.392 50.971 76.446 51.101 ;
     RECT  38.7 51.067 42.462 51.163 ;
     RECT  43.2 50.237 75.192 51.163 ;
     RECT  77.616 48.989 78.297 51.205 ;
     RECT  95.904 51.601 95.922 51.745 ;
     RECT  77.58 51.205 78.297 51.835 ;
     RECT  92.52 50.717 92.538 51.871 ;
     RECT  93.42 50.717 94.497 51.871 ;
     RECT  95.76 51.745 95.922 51.871 ;
     RECT  92.52 51.871 94.497 51.917 ;
     RECT  38.7 51.163 75.192 52.015 ;
     RECT  76.392 51.101 76.41 52.169 ;
     RECT  91.152 50.819 91.797 52.213 ;
     RECT  90.648 52.213 91.797 52.249 ;
     RECT  92.52 51.917 92.646 52.249 ;
     RECT  95.724 51.871 95.922 52.411 ;
     RECT  95.472 52.411 95.922 52.445 ;
     RECT  77.4 51.835 78.297 52.475 ;
     RECT  85.752 46.061 86.397 52.519 ;
     RECT  90.648 52.249 92.646 52.651 ;
     RECT  90.288 52.651 92.646 52.681 ;
     RECT  93.384 51.917 94.497 52.681 ;
     RECT  90.288 52.681 94.497 52.717 ;
     RECT  90.288 52.717 94.518 52.789 ;
     RECT  90.288 52.789 94.59 52.795 ;
     RECT  90.288 52.795 94.698 52.889 ;
     RECT  95.472 52.445 95.778 52.979 ;
     RECT  38.592 52.015 75.192 52.987 ;
     RECT  90.9 52.889 94.698 53.024 ;
     RECT  88.815 43.709 89.097 53.083 ;
     RECT  38.592 52.987 75.834 53.117 ;
     RECT  38.592 53.117 75.582 53.123 ;
     RECT  38.952 53.123 75.582 53.249 ;
     RECT  77.436 52.475 78.297 53.275 ;
     RECT  39.78 53.249 75.582 53.285 ;
     RECT  95.544 52.979 95.778 53.323 ;
     RECT  88.815 53.083 89.154 53.365 ;
     RECT  77.4 53.275 78.297 53.401 ;
     RECT  77.22 53.401 78.297 53.467 ;
     RECT  88.815 53.365 89.298 53.563 ;
     RECT  90.072 53.221 90.09 53.563 ;
     RECT  95.544 53.323 95.85 53.611 ;
     RECT  91.008 53.024 94.698 53.671 ;
     RECT  98.1 53.563 98.118 53.693 ;
     RECT  88.815 53.563 90.09 53.761 ;
     RECT  91.008 53.671 94.77 53.761 ;
     RECT  39.924 53.285 75.582 53.905 ;
     RECT  76.68 53.467 78.297 53.905 ;
     RECT  85.752 52.519 86.67 53.941 ;
     RECT  88.815 53.761 94.77 53.995 ;
     RECT  95.544 53.611 95.922 53.995 ;
     RECT  88.815 53.995 95.922 54.059 ;
     RECT  85.752 53.941 86.706 54.095 ;
     RECT  88.815 54.059 95.814 54.173 ;
     RECT  92.52 54.173 95.814 54.811 ;
     RECT  88.815 54.173 91.797 54.977 ;
     RECT  90.072 54.977 91.797 55.099 ;
     RECT  92.52 54.811 95.922 55.099 ;
     RECT  90.072 55.099 95.922 55.147 ;
     RECT  85.752 54.095 86.397 55.489 ;
     RECT  88.815 54.977 89.19 55.679 ;
     RECT  85.752 55.489 86.67 56.029 ;
     RECT  85.752 56.029 86.706 56.219 ;
     RECT  85.752 56.219 86.67 56.669 ;
     RECT  86.115 56.669 86.67 56.795 ;
     RECT  97.452 54.859 97.47 56.831 ;
     RECT  90.072 55.147 95.958 57.101 ;
     RECT  90.864 57.101 95.958 57.149 ;
     RECT  90.936 57.149 95.958 57.569 ;
     RECT  92.7 57.569 95.958 57.595 ;
     RECT  92.7 57.595 96.282 57.629 ;
     RECT  95.76 57.629 96.282 57.641 ;
     RECT  95.76 57.641 95.958 58.415 ;
     RECT  92.7 57.629 94.878 58.693 ;
     RECT  39.924 53.905 78.297 60.504 ;
     RECT  95.94 58.415 95.958 60.575 ;
     RECT  92.628 58.693 94.878 60.611 ;
     RECT  92.628 60.611 94.842 60.647 ;
     RECT  70.704 60.504 70.794 60.683 ;
     RECT  74.736 60.504 78.297 60.683 ;
     RECT  39.924 60.504 42.75 60.719 ;
     RECT  75.204 60.683 78.297 60.719 ;
     RECT  70.704 60.683 70.722 60.764 ;
     RECT  75.204 60.719 76.986 60.764 ;
     RECT  40.215 60.719 42.75 61.151 ;
     RECT  90.072 57.101 90.09 61.151 ;
     RECT  41.868 61.151 42.75 61.187 ;
     RECT  75.204 60.764 76.662 61.223 ;
     RECT  75.204 61.223 76.266 61.259 ;
     RECT  40.215 61.151 41.022 61.349 ;
     RECT  77.868 60.719 78.297 61.421 ;
     RECT  75.204 61.259 76.194 61.457 ;
     RECT  41.868 61.187 41.886 61.619 ;
     RECT  92.628 60.647 92.646 61.619 ;
     RECT  40.215 61.349 40.914 61.655 ;
     RECT  90.936 57.569 91.797 61.655 ;
     RECT  42.696 61.187 42.75 62.131 ;
     RECT  42.66 62.131 42.75 62.437 ;
     RECT  75.204 61.457 75.618 62.473 ;
     RECT  74.664 62.473 75.618 62.501 ;
     RECT  42.66 62.437 42.786 62.537 ;
     RECT  42.768 62.537 42.786 62.573 ;
     RECT  49.86 62.545 49.878 62.581 ;
     RECT  74.664 62.501 75.597 62.609 ;
     RECT  50.616 62.509 50.634 62.623 ;
     RECT  49.752 62.581 49.878 62.699 ;
     RECT  93.42 60.647 94.842 62.699 ;
     RECT  50.616 62.623 51.105 62.735 ;
     RECT  75.204 62.609 75.597 62.735 ;
     RECT  42.915 62.623 43.005 62.893 ;
     RECT  45.615 62.623 45.705 62.893 ;
     RECT  48.315 62.623 48.405 62.893 ;
     RECT  51.015 62.735 51.105 62.893 ;
     RECT  53.715 62.623 53.805 62.893 ;
     RECT  56.415 62.623 56.505 62.893 ;
     RECT  59.115 62.623 59.205 62.893 ;
     RECT  61.815 62.623 61.905 62.893 ;
     RECT  64.515 62.623 64.605 62.893 ;
     RECT  67.215 62.623 67.305 62.893 ;
     RECT  69.915 62.623 70.005 62.893 ;
     RECT  72.615 62.623 72.705 62.893 ;
     RECT  75.24 62.735 75.597 62.969 ;
     RECT  42.915 62.893 43.197 64.561 ;
     RECT  42.915 64.561 43.542 64.859 ;
     RECT  42.915 64.859 43.254 64.877 ;
     RECT  42.915 64.877 43.218 64.973 ;
     RECT  80.715 47.309 80.997 65.707 ;
     RECT  80.532 65.707 80.997 65.747 ;
     RECT  78.015 61.421 78.297 65.821 ;
     RECT  78.015 65.821 79.002 66.125 ;
     RECT  79.236 67.819 79.254 68.099 ;
     RECT  78.015 66.125 78.297 70.123 ;
     RECT  14.256 70.231 14.274 70.301 ;
     RECT  13.215 2.413 13.497 70.411 ;
     RECT  78.015 70.123 78.678 70.501 ;
     RECT  77.472 70.501 78.678 70.529 ;
     RECT  13.215 70.411 13.986 70.589 ;
     RECT  77.472 70.529 78.297 70.685 ;
     RECT  78.015 70.685 78.297 72.955 ;
     RECT  77.472 72.955 78.297 73.229 ;
     RECT  76.644 73.273 76.662 73.325 ;
     RECT  37.515 2.413 37.797 74.281 ;
     RECT  38.952 53.249 38.97 74.281 ;
     RECT  0.108 74.299 0.126 74.347 ;
     RECT  5.115 46.229 5.397 74.425 ;
     RECT  4.284 74.317 4.302 74.443 ;
     RECT  4.212 74.443 4.302 74.461 ;
     RECT  2.415 45.419 2.697 74.587 ;
     RECT  3.852 74.461 4.302 74.587 ;
     RECT  0.108 74.347 0.198 74.623 ;
     RECT  0.108 74.623 0.27 74.669 ;
     RECT  6.84 74.281 6.858 74.695 ;
     RECT  0.108 74.669 0.198 74.759 ;
     RECT  5.115 74.425 5.562 74.821 ;
     RECT  9.396 74.587 9.414 74.821 ;
     RECT  40.215 61.655 40.497 74.821 ;
     RECT  21.315 2.413 21.597 74.827 ;
     RECT  29.415 2.413 29.697 74.827 ;
     RECT  40.032 74.821 40.497 74.861 ;
     RECT  7.815 45.455 8.097 74.929 ;
     RECT  10.515 44.249 10.797 74.929 ;
     RECT  21.315 74.827 21.69 74.957 ;
     RECT  22.824 74.827 22.842 74.957 ;
     RECT  29.415 74.827 29.79 74.957 ;
     RECT  30.78 74.827 30.798 74.957 ;
     RECT  6.84 74.695 6.966 74.965 ;
     RECT  7.776 74.929 8.097 74.965 ;
     RECT  6.84 74.965 8.097 75.001 ;
     RECT  0.108 74.759 0.162 75.029 ;
     RECT  6.804 75.001 8.097 75.091 ;
     RECT  8.964 74.821 9.414 75.091 ;
     RECT  6.804 75.091 9.414 75.119 ;
     RECT  13.215 70.589 13.497 75.127 ;
     RECT  2.415 74.587 4.302 75.163 ;
     RECT  5.115 74.821 5.85 75.163 ;
     RECT  6.804 75.119 8.37 75.197 ;
     RECT  40.176 74.861 40.497 75.197 ;
     RECT  10.515 74.929 10.818 75.361 ;
     RECT  37.515 74.281 38.97 75.361 ;
     RECT  2.415 75.163 5.85 75.389 ;
     RECT  7.632 75.197 8.37 75.389 ;
     RECT  75.315 62.969 75.597 75.451 ;
     RECT  6.804 75.197 6.822 75.541 ;
     RECT  75.315 75.451 75.906 75.541 ;
     RECT  10.515 75.361 10.854 75.569 ;
     RECT  75.315 75.541 76.23 75.581 ;
     RECT  34.815 45.563 35.097 75.667 ;
     RECT  7.815 75.389 8.37 76.009 ;
     RECT  9.396 75.119 9.414 76.009 ;
     RECT  0.144 75.029 0.162 76.027 ;
     RECT  6.552 75.541 6.822 76.045 ;
     RECT  0.108 76.027 0.162 76.301 ;
     RECT  6.552 76.045 6.966 76.309 ;
     RECT  2.415 75.389 5.778 76.315 ;
     RECT  6.552 76.309 7.002 76.315 ;
     RECT  2.415 76.315 7.002 76.351 ;
     RECT  7.815 76.009 9.414 76.351 ;
     RECT  83.415 47.453 83.697 76.459 ;
     RECT  40.215 75.197 40.497 76.621 ;
     RECT  13.215 75.127 13.698 76.649 ;
     RECT  83.415 76.459 83.79 76.739 ;
     RECT  2.415 76.351 9.414 76.795 ;
     RECT  2.268 76.795 9.414 76.925 ;
     RECT  37.515 75.361 39.042 77.323 ;
     RECT  39.852 76.621 40.497 77.323 ;
     RECT  2.415 76.925 9.414 77.729 ;
     RECT  37.515 77.323 40.497 77.827 ;
     RECT  0.108 76.301 0.126 77.947 ;
     RECT  64.515 62.893 64.797 78.043 ;
     RECT  64.515 78.043 65.43 78.091 ;
     RECT  64.515 78.091 65.682 78.241 ;
     RECT  64.515 78.241 66.006 78.359 ;
     RECT  93.42 62.699 94.497 78.403 ;
     RECT  64.515 78.359 65.682 78.467 ;
     RECT  64.515 78.467 65.25 78.503 ;
     RECT  93.24 78.403 94.497 78.503 ;
     RECT  2.415 77.729 2.697 78.511 ;
     RECT  3.456 77.729 9.414 78.511 ;
     RECT  0.108 77.947 0.162 78.539 ;
     RECT  0.144 78.539 0.162 78.653 ;
     RECT  2.415 78.511 9.414 78.763 ;
     RECT  2.304 78.763 9.414 78.809 ;
     RECT  2.415 78.809 9.414 79.547 ;
     RECT  95.76 80.095 95.778 80.131 ;
     RECT  95.76 80.131 95.922 80.221 ;
     RECT  94.215 78.503 94.497 80.299 ;
     RECT  95.724 80.221 95.922 80.333 ;
     RECT  3.42 79.547 9.414 80.671 ;
     RECT  94.215 80.299 94.626 80.761 ;
     RECT  95.724 80.333 95.814 80.761 ;
     RECT  93.24 78.503 93.258 80.875 ;
     RECT  94.215 80.761 94.806 80.905 ;
     RECT  95.58 80.761 95.814 80.905 ;
     RECT  34.815 75.667 35.622 81.301 ;
     RECT  93.24 80.875 93.402 81.445 ;
     RECT  94.215 80.905 95.814 81.445 ;
     RECT  93.24 81.445 95.814 81.481 ;
     RECT  91.515 61.655 91.797 81.715 ;
     RECT  91.296 81.715 91.797 81.751 ;
     RECT  92.916 81.481 95.814 81.751 ;
     RECT  91.296 81.751 95.814 81.841 ;
     RECT  90.9 81.841 95.814 82.183 ;
     RECT  90.648 82.183 95.814 82.267 ;
     RECT  75.315 75.581 75.597 82.291 ;
     RECT  3.42 80.671 9.45 82.651 ;
     RECT  88.815 55.679 89.097 82.651 ;
     RECT  88.815 82.651 89.694 82.687 ;
     RECT  86.115 56.795 86.397 82.723 ;
     RECT  88.815 82.687 89.838 82.723 ;
     RECT  90.648 82.267 95.922 82.723 ;
     RECT  78.015 73.229 78.297 82.831 ;
     RECT  88.815 82.723 95.922 82.831 ;
     RECT  37.515 77.827 40.77 82.921 ;
     RECT  97.452 82.075 97.47 83.021 ;
     RECT  85.824 82.723 86.397 83.029 ;
     RECT  75.315 82.291 75.726 83.065 ;
     RECT  78.015 82.831 78.642 83.129 ;
     RECT  88.815 82.831 95.994 83.191 ;
     RECT  88.815 83.191 96.426 83.261 ;
     RECT  42.915 64.973 43.197 83.275 ;
     RECT  64.515 78.503 65.214 83.461 ;
     RECT  88.815 83.261 95.922 83.489 ;
     RECT  3.42 82.651 9.522 83.525 ;
     RECT  3.42 83.525 3.474 83.561 ;
     RECT  4.356 83.525 9.522 83.597 ;
     RECT  75.096 83.065 75.726 83.641 ;
     RECT  69.915 62.893 70.197 83.731 ;
     RECT  64.515 83.461 65.43 83.851 ;
     RECT  53.715 62.893 53.997 83.899 ;
     RECT  61.815 62.893 62.097 83.899 ;
     RECT  75.096 83.641 75.87 83.911 ;
     RECT  98.1 83.803 98.118 83.933 ;
     RECT  45.615 62.893 45.897 83.987 ;
     RECT  48.315 62.893 48.597 83.987 ;
     RECT  51.015 62.893 51.297 83.987 ;
     RECT  56.415 62.893 56.697 83.987 ;
     RECT  59.115 62.893 59.397 83.987 ;
     RECT  67.215 62.893 67.497 83.987 ;
     RECT  72.615 62.893 72.897 83.987 ;
     RECT  49.464 83.731 49.482 84.001 ;
     RECT  85.752 83.029 86.67 84.029 ;
     RECT  72.615 83.987 72.705 84.037 ;
     RECT  53.715 83.899 54.09 84.043 ;
     RECT  54.828 83.899 54.846 84.043 ;
     RECT  61.815 83.899 62.19 84.043 ;
     RECT  64.515 83.851 65.898 84.043 ;
     RECT  49.176 84.001 49.482 84.077 ;
     RECT  53.715 84.043 54.846 84.077 ;
     RECT  69.915 83.731 70.794 84.077 ;
     RECT  72.324 84.037 72.705 84.077 ;
     RECT  3.456 83.561 3.474 84.101 ;
     RECT  74.664 83.911 75.87 84.101 ;
     RECT  64.512 84.043 65.898 84.109 ;
     RECT  49.464 84.077 49.482 84.125 ;
     RECT  70.776 84.077 70.794 84.125 ;
     RECT  46.764 84.043 46.782 84.173 ;
     RECT  53.715 84.077 54.198 84.173 ;
     RECT  61.815 84.043 62.298 84.173 ;
     RECT  64.512 84.109 66.078 84.173 ;
     RECT  72.396 84.077 72.705 84.173 ;
     RECT  79.236 84.109 79.758 84.173 ;
     RECT  42.915 83.275 43.542 84.257 ;
     RECT  45.615 83.987 45.705 84.257 ;
     RECT  48.315 83.987 48.405 84.257 ;
     RECT  51.015 83.987 51.105 84.257 ;
     RECT  53.715 84.173 53.805 84.257 ;
     RECT  56.415 83.987 56.505 84.257 ;
     RECT  59.115 83.987 59.205 84.257 ;
     RECT  61.815 84.173 61.905 84.257 ;
     RECT  64.515 84.173 65.25 84.257 ;
     RECT  67.215 83.987 67.305 84.257 ;
     RECT  69.915 84.077 70.005 84.257 ;
     RECT  72.615 84.173 72.705 84.257 ;
     RECT  74.844 84.101 75.87 84.299 ;
     RECT  90.324 83.489 95.922 84.307 ;
     RECT  43.056 84.257 43.542 84.365 ;
     RECT  97.452 84.235 97.47 84.37 ;
     RECT  97.416 84.37 97.47 84.371 ;
     RECT  75.096 84.299 75.87 84.407 ;
     RECT  83.415 76.739 83.697 84.523 ;
     RECT  82.872 84.523 83.697 84.569 ;
     RECT  88.815 83.489 89.097 84.571 ;
     RECT  84.42 84.568 84.438 84.605 ;
     RECT  90.144 84.307 95.922 84.605 ;
     RECT  97.416 84.371 97.434 84.641 ;
     RECT  4.356 83.597 8.097 84.667 ;
     RECT  3.96 84.667 8.097 84.749 ;
     RECT  0.108 84.667 0.342 84.845 ;
     RECT  2.415 79.547 2.697 84.847 ;
     RECT  85.752 84.029 86.397 84.859 ;
     RECT  3.996 84.749 8.097 84.989 ;
     RECT  4.068 84.989 8.097 84.991 ;
     RECT  8.856 83.597 9.522 84.991 ;
     RECT  2.415 84.847 3.222 85.181 ;
     RECT  97.452 85.099 97.47 85.181 ;
     RECT  65.232 84.257 65.25 85.253 ;
     RECT  79.74 84.173 79.758 85.387 ;
     RECT  80.715 65.747 80.997 85.387 ;
     RECT  85.68 84.859 86.397 85.415 ;
     RECT  88.815 84.571 89.262 85.423 ;
     RECT  88.815 85.423 89.406 85.483 ;
     RECT  90.144 84.605 95.778 85.483 ;
     RECT  79.74 85.387 80.997 85.649 ;
     RECT  78.015 83.129 78.297 85.801 ;
     RECT  85.752 85.415 86.397 85.801 ;
     RECT  88.815 85.483 95.778 85.801 ;
     RECT  88.815 85.801 95.814 85.829 ;
     RECT  81.9 85.801 81.918 85.919 ;
     RECT  82.656 85.801 82.674 85.919 ;
     RECT  2.415 85.181 3.15 85.927 ;
     RECT  4.068 84.991 9.522 85.927 ;
     RECT  34.815 81.301 36.198 85.927 ;
     RECT  2.415 85.927 9.522 85.963 ;
     RECT  90.9 85.829 95.814 85.997 ;
     RECT  85.752 85.801 86.67 86.027 ;
     RECT  78.015 85.801 78.93 86.035 ;
     RECT  88.815 85.829 90.054 86.045 ;
     RECT  2.304 85.963 9.522 86.063 ;
     RECT  2.304 86.063 2.79 86.099 ;
     RECT  3.78 86.063 9.522 86.189 ;
     RECT  37.515 82.921 40.95 86.341 ;
     RECT  77.904 86.035 78.93 86.341 ;
     RECT  79.74 85.649 79.758 86.341 ;
     RECT  2.304 86.099 2.697 86.369 ;
     RECT  43.056 84.365 43.11 86.4 ;
     RECT  70.704 86.269 70.722 86.4 ;
     RECT  75.096 84.407 75.834 86.4 ;
     RECT  3.816 86.189 9.522 86.459 ;
     RECT  90.036 86.045 90.054 86.531 ;
     RECT  83.415 84.569 83.697 86.611 ;
     RECT  90.9 85.997 95.778 86.611 ;
     RECT  3.816 86.459 8.37 86.621 ;
     RECT  0.108 84.845 0.126 86.639 ;
     RECT  3.852 86.621 8.37 86.729 ;
     RECT  90.828 86.611 95.778 86.764 ;
     RECT  34.452 85.927 36.198 86.999 ;
     RECT  0.54 86.881 0.558 87.005 ;
     RECT  43.056 86.4 75.834 87.151 ;
     RECT  90.828 86.764 95.814 87.241 ;
     RECT  9.108 86.459 9.522 87.269 ;
     RECT  37.515 86.341 41.31 87.277 ;
     RECT  85.752 86.027 86.397 87.307 ;
     RECT  90.828 87.241 95.922 87.341 ;
     RECT  2.415 86.369 2.697 87.349 ;
     RECT  42.732 87.151 75.834 87.349 ;
     RECT  84.564 87.259 84.582 87.355 ;
     RECT  13.215 76.649 13.497 87.403 ;
     RECT  21.315 74.957 21.597 87.403 ;
     RECT  77.904 86.341 79.758 87.421 ;
     RECT  14.832 87.307 14.85 87.437 ;
     RECT  22.824 87.307 22.842 87.437 ;
     RECT  30.78 87.307 30.798 87.437 ;
     RECT  85.752 87.307 86.67 87.437 ;
     RECT  13.104 87.403 13.497 87.449 ;
     RECT  21.204 87.403 21.597 87.449 ;
     RECT  77.868 87.421 79.758 87.485 ;
     RECT  2.304 87.349 2.697 87.547 ;
     RECT  90.828 87.341 95.778 87.575 ;
     RECT  42.624 87.349 75.834 87.581 ;
     RECT  37.515 87.277 41.634 87.583 ;
     RECT  37.515 87.583 41.67 87.619 ;
     RECT  2.304 87.547 2.79 87.691 ;
     RECT  3.888 86.729 8.37 87.691 ;
     RECT  2.304 87.691 3.042 87.781 ;
     RECT  3.888 87.691 8.586 87.781 ;
     RECT  42.984 87.581 75.834 87.809 ;
     RECT  43.02 87.809 75.834 87.917 ;
     RECT  9.396 87.269 9.522 88.079 ;
     RECT  90.828 87.575 95.31 88.123 ;
     RECT  77.904 87.485 79.758 88.231 ;
     RECT  90.648 88.123 95.31 88.253 ;
     RECT  85.752 87.437 86.49 88.363 ;
     RECT  85.752 88.363 86.67 88.445 ;
     RECT  85.824 88.445 86.67 88.459 ;
     RECT  91.188 88.253 95.31 88.493 ;
     RECT  91.188 88.493 95.13 88.619 ;
     RECT  37.515 87.619 42.246 88.637 ;
     RECT  2.304 87.781 8.586 88.699 ;
     RECT  9.396 88.079 9.414 88.699 ;
     RECT  85.824 88.459 86.706 88.733 ;
     RECT  0.108 88.699 0.126 88.747 ;
     RECT  36.18 86.999 36.198 88.763 ;
     RECT  85.824 88.733 86.67 88.781 ;
     RECT  0.108 88.747 0.198 88.799 ;
     RECT  0.18 88.799 0.198 88.877 ;
     RECT  10.515 75.569 10.797 89.041 ;
     RECT  86.004 88.781 86.67 89.069 ;
     RECT  91.188 88.619 93.33 89.131 ;
     RECT  94.215 88.619 95.13 89.159 ;
     RECT  2.304 88.699 9.414 89.168 ;
     RECT  2.415 89.168 9.414 89.195 ;
     RECT  10.515 89.041 10.818 89.231 ;
     RECT  90.648 89.131 93.33 89.339 ;
     RECT  43.2 87.917 75.834 89.371 ;
     RECT  43.092 89.371 75.834 89.501 ;
     RECT  91.224 89.339 93.33 89.515 ;
     RECT  94.215 89.159 94.878 89.515 ;
     RECT  24.015 2.413 24.297 89.779 ;
     RECT  34.452 86.999 35.097 89.807 ;
     RECT  43.2 89.501 75.834 89.851 ;
     RECT  2.415 89.195 8.838 89.879 ;
     RECT  11.664 79.519 11.682 89.969 ;
     RECT  91.224 89.515 94.878 89.969 ;
     RECT  84.564 87.355 84.87 89.977 ;
     RECT  94.068 89.969 94.878 89.981 ;
     RECT  86.004 89.069 86.397 90.077 ;
     RECT  77.436 88.231 79.758 90.173 ;
     RECT  94.215 89.981 94.878 90.239 ;
     RECT  37.515 88.637 42.21 90.269 ;
     RECT  84.564 89.977 84.906 90.269 ;
     RECT  91.224 89.969 92.79 90.311 ;
     RECT  81.972 86.071 81.99 90.317 ;
     RECT  37.515 90.269 41.67 90.461 ;
     RECT  2.415 89.879 4.266 90.653 ;
     RECT  92.736 90.311 92.79 90.653 ;
     RECT  86.115 90.077 86.397 90.763 ;
     RECT  43.2 89.851 76.338 90.823 ;
     RECT  83.376 86.611 83.697 90.845 ;
     RECT  77.436 90.173 78.678 90.893 ;
     RECT  86.115 90.763 86.67 90.893 ;
     RECT  91.224 90.311 91.854 90.893 ;
     RECT  42.768 90.823 76.338 91.133 ;
     RECT  23.364 89.779 24.297 91.229 ;
     RECT  5.115 89.879 8.838 91.463 ;
     RECT  43.2 91.133 76.338 91.471 ;
     RECT  18.615 2.413 18.897 91.597 ;
     RECT  43.2 91.471 76.374 91.613 ;
     RECT  22.572 91.561 22.59 91.661 ;
     RECT  76.32 91.613 76.374 91.805 ;
     RECT  22.356 91.741 22.374 91.853 ;
     RECT  37.515 90.461 41.634 91.9 ;
     RECT  76.356 91.805 76.374 92.011 ;
     RECT  77.436 90.893 78.297 92.011 ;
     RECT  37.515 91.9 41.67 92.101 ;
     RECT  37.515 92.101 42.246 92.173 ;
     RECT  76.356 92.011 78.297 92.189 ;
     RECT  37.515 92.173 42.282 92.209 ;
     RECT  43.2 91.613 75.192 92.209 ;
     RECT  18.615 91.597 19.422 92.309 ;
     RECT  37.515 92.209 75.192 92.477 ;
     RECT  34.815 89.807 35.097 92.515 ;
     RECT  7.815 91.463 8.838 92.543 ;
     RECT  76.932 92.189 78.297 92.861 ;
     RECT  13.215 87.449 13.497 92.911 ;
     RECT  21.315 87.449 21.597 92.911 ;
     RECT  13.104 92.911 13.497 92.957 ;
     RECT  21.204 92.911 21.597 92.957 ;
     RECT  5.115 91.463 6.858 92.975 ;
     RECT  2.415 90.653 3.762 93.047 ;
     RECT  14.832 92.923 14.85 93.053 ;
     RECT  22.824 92.923 22.842 93.053 ;
     RECT  30.78 92.923 30.798 93.053 ;
     RECT  6.84 92.975 6.858 93.083 ;
     RECT  7.815 92.543 8.586 93.119 ;
     RECT  34.776 92.515 35.097 93.353 ;
     RECT  2.415 93.047 3.402 93.515 ;
     RECT  77.4 92.861 78.297 93.515 ;
     RECT  5.115 92.975 5.886 93.551 ;
     RECT  42.192 92.477 75.192 93.629 ;
     RECT  76.392 93.091 76.41 93.793 ;
     RECT  77.544 93.515 78.297 94.055 ;
     RECT  42.192 93.629 42.21 94.441 ;
     RECT  43.092 93.629 75.192 94.567 ;
     RECT  76.356 93.793 76.41 94.567 ;
     RECT  37.515 92.477 41.31 94.651 ;
     RECT  42.156 94.441 42.21 94.651 ;
     RECT  91.224 90.893 91.797 94.667 ;
     RECT  43.092 94.567 76.41 94.685 ;
     RECT  77.616 94.055 78.297 94.939 ;
     RECT  37.515 94.651 42.21 95.143 ;
     RECT  43.092 94.685 75.192 95.143 ;
     RECT  95.904 95.341 95.922 95.405 ;
     RECT  95.76 95.485 95.778 95.611 ;
     RECT  91.296 94.667 91.797 95.995 ;
     RECT  92.772 90.653 92.79 95.995 ;
     RECT  94.215 90.239 94.554 95.995 ;
     RECT  76.392 94.685 76.41 96.025 ;
     RECT  94.14 95.995 94.554 96.061 ;
     RECT  37.515 95.143 75.192 96.151 ;
     RECT  95.724 95.611 95.778 96.151 ;
     RECT  94.14 96.061 94.662 96.187 ;
     RECT  95.616 96.151 95.922 96.221 ;
     RECT  37.44 96.151 75.192 96.251 ;
     RECT  95.616 96.221 95.778 96.283 ;
     RECT  94.068 96.187 94.662 96.295 ;
     RECT  95.508 96.283 95.778 96.295 ;
     RECT  91.296 95.995 92.79 96.331 ;
     RECT  94.068 96.295 95.778 96.331 ;
     RECT  77.58 94.939 78.297 96.379 ;
     RECT  88.815 86.045 89.097 96.379 ;
     RECT  37.515 96.251 75.192 96.475 ;
     RECT  76.392 96.025 76.446 96.475 ;
     RECT  86.115 90.893 86.397 96.529 ;
     RECT  88.815 96.379 89.442 96.571 ;
     RECT  91.296 96.331 95.778 96.601 ;
     RECT  88.815 96.571 89.586 96.629 ;
     RECT  37.515 96.475 76.446 96.667 ;
     RECT  77.4 96.379 78.297 96.667 ;
     RECT  37.515 96.667 78.297 96.755 ;
     RECT  90.324 96.601 90.342 96.859 ;
     RECT  91.224 96.601 95.778 96.859 ;
     RECT  37.515 96.755 75.834 96.997 ;
     RECT  90.324 96.859 95.778 97.141 ;
     RECT  98.244 97.291 98.262 97.303 ;
     RECT  86.115 96.529 86.67 97.331 ;
     RECT  88.815 96.629 89.442 97.331 ;
     RECT  98.172 97.303 98.262 97.331 ;
     RECT  98.172 97.331 98.19 97.373 ;
     RECT  37.512 96.997 75.834 97.375 ;
     RECT  37.476 97.375 75.834 97.403 ;
     RECT  76.644 96.755 78.297 97.403 ;
     RECT  36.72 97.387 36.738 97.411 ;
     RECT  37.476 97.403 39.006 97.411 ;
     RECT  90.252 97.141 95.778 97.411 ;
     RECT  36.72 97.411 39.006 97.439 ;
     RECT  36.828 97.439 39.006 97.529 ;
     RECT  37.26 97.529 38.79 97.565 ;
     RECT  90.144 97.411 95.778 97.723 ;
     RECT  79.56 90.173 79.758 97.799 ;
     RECT  37.26 97.565 38.502 97.943 ;
     RECT  97.452 97.627 97.47 98.141 ;
     RECT  39.996 97.403 75.834 98.149 ;
     RECT  76.644 97.403 76.77 98.149 ;
     RECT  86.115 97.331 86.397 98.149 ;
     RECT  86.115 98.149 86.67 98.339 ;
     RECT  90.144 97.723 95.922 98.635 ;
     RECT  90.144 98.635 96.426 98.725 ;
     RECT  88.815 97.331 89.097 98.731 ;
     RECT  90.108 98.725 96.426 98.765 ;
     RECT  88.815 98.731 89.226 98.851 ;
     RECT  88.815 98.851 89.37 98.887 ;
     RECT  90.108 98.765 95.922 98.887 ;
     RECT  88.815 98.887 95.922 99.005 ;
     RECT  86.115 98.339 86.397 99.301 ;
     RECT  90 99.005 95.922 99.437 ;
     RECT  84.564 90.269 84.87 99.491 ;
     RECT  86.115 99.301 86.67 99.491 ;
     RECT  84.636 99.491 84.87 99.689 ;
     RECT  84.636 99.689 84.762 99.821 ;
     RECT  86.115 99.491 86.397 99.931 ;
     RECT  97.452 99.211 97.47 99.931 ;
     RECT  22.428 99.739 22.446 99.959 ;
     RECT  87.516 99.787 87.534 99.959 ;
     RECT  90 99.437 95.634 99.959 ;
     RECT  88.815 99.005 89.097 99.967 ;
     RECT  88.815 99.967 89.19 100.003 ;
     RECT  90 99.959 95.49 100.003 ;
     RECT  21.315 92.957 21.597 100.069 ;
     RECT  21.315 100.069 22.122 100.109 ;
     RECT  87.408 100.069 87.426 100.109 ;
     RECT  84.636 99.821 84.654 100.139 ;
     RECT  85.896 99.931 86.397 100.301 ;
     RECT  97.308 99.931 97.47 100.301 ;
     RECT  88.815 100.003 95.49 100.363 ;
     RECT  39.996 98.149 76.77 100.535 ;
     RECT  88.272 100.363 95.49 100.603 ;
     RECT  88.164 100.603 95.49 100.643 ;
     RECT  88.815 100.643 95.49 100.84 ;
     RECT  97.452 100.301 97.47 100.841 ;
     RECT  88.815 100.84 95.994 100.877 ;
     RECT  88.815 100.877 91.797 100.883 ;
     RECT  92.556 100.877 95.922 100.949 ;
     RECT  79.56 97.799 79.578 101.849 ;
     RECT  93.384 100.949 95.922 102.128 ;
     RECT  93.384 102.128 95.778 102.155 ;
     RECT  39.996 100.535 76.698 103.704 ;
     RECT  93.384 102.155 95.382 103.811 ;
     RECT  93.384 103.811 93.402 103.847 ;
     RECT  94.215 103.811 95.382 104.351 ;
     RECT  94.215 104.351 94.95 104.387 ;
     RECT  92.556 100.949 92.574 104.423 ;
     RECT  39.996 103.704 43.146 104.549 ;
     RECT  90.072 100.883 91.797 104.549 ;
     RECT  75.276 103.704 76.698 104.621 ;
     RECT  41.976 104.549 43.146 104.693 ;
     RECT  7.815 93.119 8.097 104.779 ;
     RECT  7.815 104.779 8.586 104.819 ;
     RECT  7.056 104.791 7.074 105.089 ;
     RECT  90.072 104.549 90.09 105.197 ;
     RECT  90.9 104.549 91.797 105.233 ;
     RECT  47.268 105.133 47.286 105.673 ;
     RECT  48.096 105.169 48.114 105.673 ;
     RECT  42.588 104.693 43.146 105.701 ;
     RECT  47.268 105.673 48.114 105.709 ;
     RECT  49.752 105.205 49.77 105.709 ;
     RECT  76.68 104.621 76.698 105.737 ;
     RECT  47.268 105.709 48.186 105.745 ;
     RECT  42.66 105.701 43.146 105.773 ;
     RECT  49.752 105.709 49.986 105.781 ;
     RECT  42.732 105.773 43.146 105.809 ;
     RECT  46.872 105.745 48.186 105.823 ;
     RECT  49.752 105.781 50.706 105.823 ;
     RECT  65.088 105.451 65.106 105.823 ;
     RECT  46.872 105.823 48.405 105.871 ;
     RECT  46.764 105.871 48.405 105.899 ;
     RECT  49.752 105.823 51.105 105.899 ;
     RECT  46.764 105.899 46.89 105.971 ;
     RECT  46.836 105.971 46.854 106.007 ;
     RECT  75.276 104.621 75.582 106.007 ;
     RECT  64.515 105.823 65.106 106.051 ;
     RECT  42.915 105.809 43.146 106.093 ;
     RECT  45.615 105.823 45.705 106.093 ;
     RECT  48.315 105.899 48.405 106.093 ;
     RECT  51.015 105.899 51.105 106.093 ;
     RECT  53.715 105.823 53.805 106.093 ;
     RECT  56.415 105.823 56.505 106.093 ;
     RECT  59.115 105.823 59.205 106.093 ;
     RECT  61.815 105.823 61.905 106.093 ;
     RECT  67.215 105.823 67.305 106.093 ;
     RECT  69.915 105.823 70.005 106.093 ;
     RECT  72.615 105.823 72.705 106.093 ;
     RECT  75.315 106.007 75.582 106.093 ;
     RECT  64.515 106.051 65.322 106.321 ;
     RECT  64.515 106.321 65.43 106.589 ;
     RECT  42.915 106.093 43.197 107.275 ;
     RECT  42.915 107.275 43.254 107.671 ;
     RECT  64.515 106.589 64.797 107.752 ;
     RECT  88.815 100.883 89.097 107.755 ;
     RECT  64.515 107.752 65.106 107.941 ;
     RECT  64.515 107.941 65.43 108.173 ;
     RECT  88.815 107.755 89.514 108.329 ;
     RECT  42.915 107.671 43.542 108.509 ;
     RECT  42.915 108.509 43.398 108.557 ;
     RECT  37.26 97.943 37.854 113.803 ;
     RECT  37.008 113.803 37.854 113.843 ;
     RECT  39.996 104.549 41.238 113.995 ;
     RECT  39.996 113.995 41.778 114.539 ;
     RECT  39.996 114.539 41.454 114.575 ;
     RECT  88.815 108.329 89.097 116.239 ;
     RECT  88.815 116.239 89.298 116.288 ;
     RECT  88.815 116.288 89.478 116.609 ;
     RECT  88.815 116.609 89.298 116.621 ;
     RECT  86.115 100.301 86.397 116.683 ;
     RECT  86.115 116.683 86.67 116.813 ;
     RECT  86.115 116.813 86.397 116.851 ;
     RECT  84.528 101.821 84.546 117.013 ;
     RECT  85.392 116.851 86.397 117.013 ;
     RECT  84.528 117.013 86.397 117.239 ;
     RECT  84.6 117.239 86.397 117.437 ;
     RECT  39.996 114.575 41.238 118.021 ;
     RECT  64.515 108.173 64.797 118.075 ;
     RECT  63.072 118.057 63.342 118.109 ;
     RECT  63.216 118.109 63.234 118.163 ;
     RECT  5.115 93.551 5.397 118.165 ;
     RECT  6.84 118.021 6.858 118.165 ;
     RECT  4.428 118.165 5.397 118.201 ;
     RECT  2.415 93.515 2.697 118.219 ;
     RECT  0.108 118.075 0.126 118.229 ;
     RECT  64.515 118.075 64.818 118.229 ;
     RECT  6.768 118.165 6.858 118.291 ;
     RECT  39.996 118.021 41.886 118.291 ;
     RECT  42.915 108.557 43.197 118.291 ;
     RECT  3.924 118.201 5.85 118.319 ;
     RECT  2.16 118.219 2.697 118.391 ;
     RECT  2.304 118.391 2.697 118.459 ;
     RECT  7.815 104.819 8.097 118.471 ;
     RECT  2.304 118.459 2.79 118.499 ;
     RECT  37.26 113.843 37.854 118.555 ;
     RECT  7.815 118.471 8.298 118.561 ;
     RECT  7.812 118.561 8.298 118.597 ;
     RECT  6.768 118.291 6.93 118.669 ;
     RECT  7.704 118.597 8.298 118.669 ;
     RECT  3.456 118.651 3.474 118.769 ;
     RECT  4.212 118.319 5.85 118.859 ;
     RECT  6.768 118.669 9.018 118.931 ;
     RECT  34.815 93.353 35.097 118.939 ;
     RECT  35.856 118.705 35.874 118.939 ;
     RECT  36.684 118.555 37.854 118.939 ;
     RECT  9 118.931 9.018 118.975 ;
     RECT  6.768 118.931 8.154 119.011 ;
     RECT  34.776 118.939 35.097 119.039 ;
     RECT  9 118.975 9.09 119.129 ;
     RECT  20.052 118.555 20.07 119.129 ;
     RECT  34.815 119.039 35.097 119.137 ;
     RECT  35.856 118.939 38.142 119.137 ;
     RECT  2.304 118.499 2.697 119.227 ;
     RECT  4.284 118.859 5.85 119.245 ;
     RECT  6.696 119.011 8.154 119.245 ;
     RECT  2.268 119.227 2.697 119.309 ;
     RECT  4.284 119.245 8.154 119.399 ;
     RECT  2.304 119.309 2.697 119.408 ;
     RECT  2.415 119.408 2.697 119.551 ;
     RECT  0.144 118.987 0.162 119.693 ;
     RECT  20.376 119.281 20.394 119.693 ;
     RECT  39.996 118.291 43.197 119.785 ;
     RECT  2.415 119.551 3.078 119.821 ;
     RECT  6.66 119.399 8.154 119.821 ;
     RECT  2.415 119.821 3.114 119.947 ;
     RECT  4.284 119.399 5.706 119.947 ;
     RECT  6.66 119.821 8.37 119.983 ;
     RECT  6.66 119.983 8.586 120.209 ;
     RECT  39.996 119.785 43.254 120.209 ;
     RECT  6.732 120.209 8.586 120.245 ;
     RECT  2.415 119.947 5.706 120.269 ;
     RECT  6.768 120.245 8.586 120.325 ;
     RECT  6.768 120.325 8.91 120.479 ;
     RECT  2.415 120.269 3.438 120.515 ;
     RECT  0.108 119.803 0.126 120.658 ;
     RECT  0.108 120.658 0.162 120.659 ;
     RECT  6.768 120.479 8.586 120.659 ;
     RECT  34.815 119.137 38.142 120.829 ;
     RECT  39.996 120.209 43.197 120.829 ;
     RECT  4.5 120.269 5.706 120.901 ;
     RECT  6.768 120.659 8.154 121.003 ;
     RECT  34.776 120.829 38.43 121.019 ;
     RECT  4.5 120.901 5.814 121.051 ;
     RECT  6.624 121.003 8.154 121.051 ;
     RECT  0.144 120.659 0.162 121.085 ;
     RECT  3.564 120.991 3.582 121.099 ;
     RECT  2.415 120.515 2.79 121.147 ;
     RECT  3.564 121.099 3.69 121.171 ;
     RECT  4.5 121.051 8.154 121.171 ;
     RECT  2.268 121.147 2.79 121.277 ;
     RECT  39.924 120.829 43.197 121.297 ;
     RECT  2.304 121.277 2.79 121.339 ;
     RECT  3.564 121.171 8.154 121.339 ;
     RECT  9.36 121.441 9.378 121.559 ;
     RECT  2.304 121.339 8.154 121.675 ;
     RECT  34.776 121.019 38.394 121.703 ;
     RECT  2.304 121.675 8.226 121.711 ;
     RECT  0.108 121.531 0.126 121.819 ;
     RECT  0.108 121.819 0.162 121.949 ;
     RECT  34.815 121.703 38.394 122.107 ;
     RECT  39.348 121.297 43.197 122.107 ;
     RECT  34.815 122.107 43.197 122.179 ;
     RECT  2.304 121.711 8.514 122.251 ;
     RECT  2.268 122.251 8.514 122.279 ;
     RECT  2.268 122.279 5.706 122.369 ;
     RECT  6.84 122.279 7.038 122.405 ;
     RECT  4.284 122.369 5.706 122.429 ;
     RECT  2.268 122.369 3.51 122.441 ;
     RECT  4.284 122.429 5.598 122.441 ;
     RECT  2.415 122.441 3.51 122.549 ;
     RECT  61.815 106.093 62.097 122.611 ;
     RECT  56.415 106.093 56.697 122.635 ;
     RECT  61.815 122.611 62.154 122.635 ;
     RECT  34.815 122.179 43.29 122.647 ;
     RECT  0.108 121.949 0.126 122.669 ;
     RECT  4.572 122.441 5.598 122.711 ;
     RECT  75.315 106.093 75.597 122.719 ;
     RECT  3.42 122.549 3.51 122.747 ;
     RECT  34.776 122.647 43.29 122.783 ;
     RECT  7.815 122.279 8.514 122.791 ;
     RECT  56.415 122.635 56.754 122.791 ;
     RECT  75.24 122.719 75.597 122.791 ;
     RECT  4.68 122.711 5.598 122.909 ;
     RECT  6.84 122.405 7.002 122.909 ;
     RECT  7.815 122.791 8.91 122.909 ;
     RECT  56.415 122.791 57.006 122.909 ;
     RECT  61.815 122.635 62.442 122.909 ;
     RECT  73.944 122.635 73.962 122.945 ;
     RECT  56.415 122.909 56.754 122.957 ;
     RECT  30.78 122.755 30.798 123.017 ;
     RECT  75.06 122.791 75.597 123.025 ;
     RECT  74.988 123.025 75.597 123.061 ;
     RECT  4.68 122.909 5.454 123.101 ;
     RECT  13.215 92.957 13.497 123.151 ;
     RECT  10.515 89.231 10.797 123.163 ;
     RECT  74.196 123.061 75.597 123.179 ;
     RECT  13.104 123.151 13.497 123.197 ;
     RECT  7.815 122.909 8.586 123.253 ;
     RECT  7.74 123.253 8.586 123.293 ;
     RECT  10.515 123.163 10.818 123.293 ;
     RECT  14.832 123.163 14.85 123.293 ;
     RECT  7.815 123.293 8.586 123.629 ;
     RECT  74.592 123.179 75.597 123.871 ;
     RECT  5.115 123.101 5.454 123.899 ;
     RECT  73.656 123.685 73.818 124.141 ;
     RECT  74.592 123.871 75.654 124.141 ;
     RECT  3.492 122.747 3.51 124.169 ;
     RECT  34.815 122.783 43.29 124.411 ;
     RECT  7.815 123.629 8.478 124.439 ;
     RECT  34.776 124.411 43.29 124.529 ;
     RECT  6.984 122.909 7.002 124.637 ;
     RECT  95.76 124.645 95.778 124.681 ;
     RECT  94.215 104.387 94.497 124.747 ;
     RECT  95.76 124.681 95.922 124.781 ;
     RECT  95.76 124.781 95.85 124.799 ;
     RECT  95.76 124.799 95.778 124.835 ;
     RECT  93.456 125.041 93.474 125.176 ;
     RECT  73.656 124.141 75.654 125.185 ;
     RECT  92.88 125.176 93.474 125.221 ;
     RECT  92.664 125.221 93.474 125.311 ;
     RECT  94.215 124.747 94.662 125.311 ;
     RECT  92.664 125.311 94.662 125.383 ;
     RECT  95.472 125.179 95.634 125.383 ;
     RECT  97.452 125.131 97.47 125.411 ;
     RECT  5.115 123.899 5.397 125.419 ;
     RECT  72.615 106.093 72.897 125.419 ;
     RECT  73.656 125.185 75.762 125.419 ;
     RECT  72.615 125.419 75.762 125.453 ;
     RECT  88.815 116.621 89.097 125.563 ;
     RECT  74.052 125.453 75.762 125.725 ;
     RECT  91.515 105.233 91.797 125.725 ;
     RECT  92.664 125.383 95.634 125.725 ;
     RECT  34.815 124.529 43.29 125.851 ;
     RECT  90.72 125.761 90.738 125.851 ;
     RECT  91.515 125.725 95.778 125.851 ;
     RECT  72.615 125.453 73.278 125.879 ;
     RECT  83.415 90.845 83.697 125.899 ;
     RECT  84.6 117.437 84.618 125.899 ;
     RECT  90.72 125.851 95.85 125.923 ;
     RECT  90.468 125.923 95.85 125.933 ;
     RECT  80.715 85.649 80.997 126.121 ;
     RECT  4.68 125.419 5.397 126.149 ;
     RECT  83.415 125.899 84.618 126.221 ;
     RECT  76.644 126.184 76.662 126.229 ;
     RECT  74.052 125.725 75.798 126.301 ;
     RECT  76.644 126.229 76.806 126.301 ;
     RECT  90.468 125.933 95.814 126.391 ;
     RECT  88.815 125.563 89.19 126.419 ;
     RECT  34.815 125.851 43.326 126.463 ;
     RECT  83.415 126.221 83.697 126.475 ;
     RECT  80.715 126.121 81.162 126.478 ;
     RECT  74.052 126.301 76.806 126.535 ;
     RECT  45.615 106.093 45.897 126.571 ;
     RECT  51.015 106.093 51.297 126.571 ;
     RECT  74.016 126.535 76.806 126.571 ;
     RECT  78.015 97.403 78.297 126.667 ;
     RECT  82.8 126.475 83.697 126.725 ;
     RECT  78.015 126.667 78.678 126.797 ;
     RECT  83.016 126.725 83.697 126.797 ;
     RECT  72.615 125.879 72.897 126.805 ;
     RECT  73.764 126.571 76.806 126.805 ;
     RECT  89.964 126.391 95.814 126.841 ;
     RECT  89.964 126.841 95.994 126.893 ;
     RECT  55.476 126.841 55.494 126.931 ;
     RECT  56.415 122.957 56.697 126.931 ;
     RECT  89.964 126.893 95.85 126.959 ;
     RECT  90.648 126.959 95.85 126.989 ;
     RECT  50.724 126.571 51.297 126.995 ;
     RECT  90.648 126.989 95.778 126.995 ;
     RECT  72.615 126.805 76.806 127.031 ;
     RECT  55.476 126.931 56.697 127.103 ;
     RECT  45 126.571 45.897 127.187 ;
     RECT  48.315 106.093 48.597 127.187 ;
     RECT  51.015 126.995 51.297 127.187 ;
     RECT  53.715 106.093 53.997 127.187 ;
     RECT  55.728 127.103 56.697 127.187 ;
     RECT  59.115 106.093 59.397 127.187 ;
     RECT  61.815 122.909 62.097 127.187 ;
     RECT  64.515 118.229 64.797 127.187 ;
     RECT  67.215 106.093 67.497 127.187 ;
     RECT  69.915 106.093 70.197 127.187 ;
     RECT  72.615 127.031 72.897 127.187 ;
     RECT  45 127.187 45.705 127.201 ;
     RECT  74.268 127.031 76.806 127.265 ;
     RECT  44.64 127.201 45.705 127.277 ;
     RECT  55.728 127.187 56.505 127.277 ;
     RECT  34.815 126.463 43.362 127.291 ;
     RECT  55.836 127.277 56.505 127.301 ;
     RECT  74.376 127.265 76.806 127.301 ;
     RECT  44.928 127.277 45.705 127.409 ;
     RECT  45.615 127.409 45.705 127.457 ;
     RECT  48.315 127.187 48.405 127.457 ;
     RECT  51.015 127.187 51.105 127.457 ;
     RECT  53.715 127.187 53.805 127.457 ;
     RECT  56.415 127.301 56.505 127.457 ;
     RECT  59.115 127.187 59.205 127.457 ;
     RECT  61.815 127.187 61.905 127.457 ;
     RECT  64.515 127.187 64.605 127.457 ;
     RECT  67.215 127.187 67.305 127.457 ;
     RECT  69.915 127.187 70.005 127.457 ;
     RECT  72.615 127.187 72.705 127.457 ;
     RECT  74.628 127.301 76.806 127.471 ;
     RECT  78.015 126.797 78.297 127.471 ;
     RECT  34.704 127.291 43.362 127.499 ;
     RECT  34.704 127.499 43.29 127.661 ;
     RECT  90.9 126.995 95.778 127.723 ;
     RECT  34.812 127.661 43.29 127.805 ;
     RECT  90.9 127.723 95.922 128.147 ;
     RECT  84.6 126.221 84.618 128.309 ;
     RECT  95.76 128.147 95.922 128.333 ;
     RECT  95.76 128.333 95.778 128.345 ;
     RECT  34.815 127.805 43.29 128.965 ;
     RECT  34.776 128.965 43.29 129.155 ;
     RECT  90.9 128.147 94.914 129.211 ;
     RECT  90.9 129.211 95.058 129.299 ;
     RECT  90.9 129.299 94.986 129.437 ;
     RECT  34.815 129.155 43.29 129.6 ;
     RECT  74.628 127.471 78.297 129.6 ;
     RECT  5.115 126.149 5.397 129.775 ;
     RECT  3.456 129.787 3.474 129.811 ;
     RECT  5.115 129.775 5.67 129.811 ;
     RECT  94.032 129.437 94.986 129.839 ;
     RECT  5.115 129.811 5.706 130.009 ;
     RECT  30.78 130.009 30.798 130.109 ;
     RECT  2.415 122.549 2.697 130.171 ;
     RECT  7.815 124.439 8.097 130.171 ;
     RECT  5.115 130.009 6.318 130.279 ;
     RECT  2.304 130.171 2.697 130.441 ;
     RECT  3.456 129.811 4.266 130.441 ;
     RECT  5.115 130.279 6.894 130.441 ;
     RECT  7.815 130.171 8.586 130.441 ;
     RECT  88.815 126.419 89.097 130.459 ;
     RECT  90.9 129.437 92.97 130.477 ;
     RECT  88.815 130.459 89.514 130.555 ;
     RECT  90.612 130.477 92.97 130.555 ;
     RECT  34.815 129.6 78.297 130.603 ;
     RECT  85.752 117.437 86.397 130.603 ;
     RECT  88.815 130.555 93.078 130.621 ;
     RECT  94.032 129.839 94.626 130.621 ;
     RECT  2.304 130.441 4.266 130.649 ;
     RECT  88.815 130.621 94.626 130.649 ;
     RECT  34.815 130.603 78.894 130.781 ;
     RECT  5.076 130.441 6.894 130.783 ;
     RECT  7.632 130.441 8.586 130.783 ;
     RECT  0.108 129.787 0.126 130.795 ;
     RECT  83.415 126.797 83.697 130.795 ;
     RECT  5.076 130.783 8.586 130.829 ;
     RECT  7.815 130.829 8.586 130.981 ;
     RECT  80.715 126.478 80.997 130.981 ;
     RECT  83.415 130.795 84.042 130.987 ;
     RECT  85.752 130.603 86.67 130.987 ;
     RECT  5.076 130.829 7.074 131.009 ;
     RECT  80.715 130.981 81.09 131.021 ;
     RECT  34.815 130.781 78.786 131.069 ;
     RECT  82.764 130.987 84.042 131.069 ;
     RECT  0.108 130.795 0.162 131.081 ;
     RECT  82.764 131.069 83.697 131.117 ;
     RECT  7.815 130.981 8.91 131.125 ;
     RECT  34.815 131.069 78.678 131.287 ;
     RECT  0.144 131.081 0.162 131.309 ;
     RECT  90.072 130.649 94.626 131.357 ;
     RECT  2.415 130.649 4.266 131.549 ;
     RECT  2.415 131.549 3.438 131.585 ;
     RECT  34.776 131.287 78.678 131.597 ;
     RECT  2.415 131.585 2.697 131.611 ;
     RECT  81.972 131.557 81.99 131.645 ;
     RECT  90.072 131.357 90.666 131.657 ;
     RECT  7.815 131.125 9.162 131.729 ;
     RECT  2.304 131.611 2.697 131.755 ;
     RECT  34.815 131.597 78.678 131.803 ;
     RECT  2.268 131.755 2.697 131.819 ;
     RECT  90.072 131.657 90.09 131.819 ;
     RECT  4.176 131.549 4.266 131.837 ;
     RECT  34.815 131.803 78.786 131.933 ;
     RECT  85.752 130.987 86.778 131.933 ;
     RECT  4.248 131.837 4.266 131.935 ;
     RECT  5.115 131.009 6.75 131.935 ;
     RECT  2.304 131.819 2.697 131.999 ;
     RECT  4.248 131.935 6.75 131.999 ;
     RECT  9.396 131.935 9.414 132.089 ;
     RECT  4.716 131.999 6.282 132.359 ;
     RECT  34.815 131.933 78.678 132.413 ;
     RECT  85.752 131.933 86.67 132.413 ;
     RECT  34.815 132.413 78.426 132.797 ;
     RECT  77.328 132.797 78.426 133.043 ;
     RECT  32.115 2.413 32.397 133.249 ;
     RECT  3.42 131.585 3.438 133.277 ;
     RECT  77.328 133.043 78.297 133.277 ;
     RECT  32.115 133.249 33.102 133.349 ;
     RECT  34.815 132.797 76.41 133.565 ;
     RECT  77.364 133.277 78.297 133.745 ;
     RECT  77.4 133.745 78.297 133.817 ;
     RECT  4.716 132.359 6.102 134.123 ;
     RECT  77.472 133.817 78.297 134.249 ;
     RECT  34.815 133.565 41.706 134.293 ;
     RECT  42.48 133.565 76.41 134.293 ;
     RECT  77.616 134.249 78.297 134.401 ;
     RECT  32.115 133.349 32.397 134.671 ;
     RECT  34.815 134.293 76.41 134.779 ;
     RECT  4.716 134.123 6.066 134.897 ;
     RECT  77.616 134.401 78.462 134.905 ;
     RECT  34.815 134.779 76.482 134.909 ;
     RECT  7.815 131.729 8.622 134.969 ;
     RECT  32.115 134.671 33.102 134.969 ;
     RECT  5.115 134.897 6.066 135.239 ;
     RECT  77.616 134.905 78.642 135.329 ;
     RECT  34.815 134.909 76.41 135.389 ;
     RECT  77.616 135.329 78.297 135.445 ;
     RECT  34.815 135.389 41.634 135.485 ;
     RECT  77.58 135.445 78.297 135.677 ;
     RECT  77.616 135.677 78.297 135.869 ;
     RECT  34.815 135.485 41.31 135.941 ;
     RECT  35.82 135.941 41.31 136.139 ;
     RECT  35.856 136.139 41.31 136.589 ;
     RECT  35.856 136.589 41.022 136.679 ;
     RECT  77.652 135.869 78.297 136.699 ;
     RECT  42.768 135.389 76.41 136.829 ;
     RECT  77.436 136.699 78.297 136.949 ;
     RECT  42.768 136.829 75.192 137.275 ;
     RECT  35.856 136.679 36.234 137.525 ;
     RECT  77.544 136.949 78.297 137.597 ;
     RECT  35.856 137.525 35.874 137.669 ;
     RECT  37.008 136.679 41.022 137.755 ;
     RECT  42.156 137.275 75.192 137.755 ;
     RECT  37.008 137.755 75.192 137.903 ;
     RECT  42.192 137.903 75.192 137.981 ;
     RECT  85.752 132.413 86.397 138.029 ;
     RECT  37.008 137.903 41.022 138.109 ;
     RECT  95.76 138.145 95.778 138.181 ;
     RECT  95.76 138.181 95.922 138.343 ;
     RECT  91.515 131.357 94.626 138.541 ;
     RECT  95.724 138.343 95.922 138.541 ;
     RECT  36.792 138.109 41.022 138.649 ;
     RECT  36.792 138.649 41.31 138.653 ;
     RECT  77.616 137.597 78.297 138.685 ;
     RECT  42.228 137.981 75.192 138.715 ;
     RECT  37.404 138.653 41.31 138.721 ;
     RECT  37.404 138.721 41.382 138.749 ;
     RECT  76.392 136.829 76.41 138.875 ;
     RECT  90.648 138.721 90.738 138.875 ;
     RECT  85.788 138.029 86.397 138.955 ;
     RECT  90.648 138.875 90.666 138.955 ;
     RECT  77.58 138.685 78.297 139.003 ;
     RECT  37.515 138.749 41.382 139.099 ;
     RECT  42.156 138.715 75.192 139.099 ;
     RECT  85.788 138.955 86.958 139.109 ;
     RECT  97.452 139.099 97.47 139.181 ;
     RECT  77.436 139.003 78.297 139.189 ;
     RECT  85.788 139.109 86.742 139.253 ;
     RECT  88.815 130.649 89.19 139.261 ;
     RECT  90.108 138.955 90.666 139.261 ;
     RECT  86.115 139.253 86.742 139.379 ;
     RECT  37.515 139.099 75.192 139.387 ;
     RECT  91.515 138.541 95.922 139.531 ;
     RECT  91.476 139.531 95.922 139.649 ;
     RECT  88.815 139.261 90.666 139.685 ;
     RECT  37.515 139.387 75.834 139.771 ;
     RECT  37.515 139.771 76.41 139.867 ;
     RECT  77.22 139.189 78.297 139.867 ;
     RECT  88.056 130.477 88.074 139.915 ;
     RECT  37.515 139.867 78.297 139.963 ;
     RECT  90.252 139.685 90.666 140.071 ;
     RECT  91.476 139.649 95.814 140.071 ;
     RECT  37.515 139.963 78.678 140.093 ;
     RECT  86.115 139.379 86.706 140.099 ;
     RECT  88.815 139.685 89.478 140.189 ;
     RECT  90.252 140.071 95.814 140.189 ;
     RECT  82.656 139.189 82.674 140.237 ;
     RECT  87.66 139.915 88.074 140.237 ;
     RECT  90.288 140.189 95.778 140.621 ;
     RECT  88.815 140.189 89.298 140.765 ;
     RECT  90.288 140.621 90.63 140.765 ;
     RECT  90.324 140.765 90.63 140.837 ;
     RECT  37.515 140.093 78.297 141.241 ;
     RECT  37.404 141.241 78.297 141.269 ;
     RECT  37.404 141.269 77.238 141.341 ;
     RECT  86.115 140.099 86.397 141.349 ;
     RECT  90.432 140.837 90.63 141.511 ;
     RECT  91.368 140.621 95.778 141.511 ;
     RECT  37.512 141.341 77.238 141.611 ;
     RECT  86.115 141.349 86.67 141.611 ;
     RECT  90.432 141.511 95.778 141.643 ;
     RECT  90.432 141.643 95.922 141.719 ;
     RECT  37.512 141.611 41.562 141.869 ;
     RECT  90.432 141.719 95.886 141.889 ;
     RECT  37.515 141.869 41.562 142.079 ;
     RECT  88.815 140.765 89.19 142.231 ;
     RECT  90.324 141.889 95.886 142.231 ;
     RECT  88.815 142.231 95.886 142.349 ;
     RECT  88.815 142.349 89.55 142.355 ;
     RECT  88.056 140.237 88.074 142.493 ;
     RECT  90.324 142.349 95.886 142.555 ;
     RECT  90.324 142.555 96.426 142.685 ;
     RECT  90.324 142.685 95.922 143.083 ;
     RECT  88.815 142.355 89.19 143.159 ;
     RECT  90.108 143.083 95.922 143.195 ;
     RECT  90.324 143.195 95.922 144.005 ;
     RECT  93.204 144.005 95.922 144.509 ;
     RECT  93.204 144.509 95.778 144.545 ;
     RECT  42.444 141.611 77.238 144.661 ;
     RECT  37.515 142.079 41.454 144.779 ;
     RECT  38.844 144.779 41.454 144.851 ;
     RECT  38.88 144.851 41.454 145.867 ;
     RECT  38.844 145.867 41.454 145.931 ;
     RECT  37.515 144.779 38.07 146.101 ;
     RECT  37.515 146.101 38.142 146.141 ;
     RECT  37.515 146.141 38.07 146.281 ;
     RECT  37.44 146.281 38.07 146.429 ;
     RECT  42.192 144.661 77.238 146.904 ;
     RECT  42.192 146.904 43.146 147.119 ;
     RECT  93.204 144.545 95.382 147.119 ;
     RECT  70.704 146.904 70.722 147.197 ;
     RECT  90.324 144.005 92.322 147.209 ;
     RECT  75.168 146.904 77.238 147.281 ;
     RECT  75.168 147.281 75.726 147.353 ;
     RECT  75.168 147.353 75.654 147.389 ;
     RECT  76.644 147.281 77.238 147.479 ;
     RECT  75.168 147.389 75.51 147.515 ;
     RECT  38.88 145.931 41.454 147.659 ;
     RECT  41.292 147.659 41.454 147.749 ;
     RECT  42.48 147.119 43.146 147.785 ;
     RECT  93.528 147.119 95.382 147.785 ;
     RECT  41.292 147.749 41.382 147.821 ;
     RECT  41.292 147.821 41.31 147.857 ;
     RECT  77.22 147.479 77.238 147.893 ;
     RECT  37.515 146.429 38.07 148.219 ;
     RECT  38.88 147.659 40.497 148.219 ;
     RECT  94.215 147.785 95.382 148.469 ;
     RECT  37.515 148.219 40.497 148.559 ;
     RECT  95.364 148.469 95.382 148.559 ;
     RECT  37.515 148.559 38.07 148.792 ;
     RECT  90.324 147.209 91.797 148.901 ;
     RECT  50.832 148.441 50.85 148.909 ;
     RECT  51.66 148.531 51.678 148.945 ;
     RECT  48.132 148.873 48.15 148.981 ;
     RECT  50.652 148.909 50.85 148.981 ;
     RECT  90.324 148.901 90.342 149.009 ;
     RECT  48.132 148.981 48.258 149.023 ;
     RECT  50.58 148.981 50.85 149.023 ;
     RECT  51.66 148.945 51.75 149.023 ;
     RECT  75.168 147.515 75.33 149.023 ;
     RECT  42.696 147.785 43.146 149.099 ;
     RECT  48.132 149.023 48.405 149.099 ;
     RECT  50.58 149.023 51.75 149.099 ;
     RECT  75.168 149.023 75.405 149.135 ;
     RECT  46.764 149.071 46.782 149.171 ;
     RECT  75.24 149.135 75.405 149.207 ;
     RECT  42.915 149.099 43.146 149.293 ;
     RECT  45.615 149.023 45.705 149.293 ;
     RECT  48.315 149.099 48.405 149.293 ;
     RECT  53.715 149.023 53.805 149.293 ;
     RECT  56.415 149.023 56.505 149.293 ;
     RECT  59.115 149.023 59.205 149.293 ;
     RECT  61.815 149.023 61.905 149.293 ;
     RECT  64.515 149.023 64.605 149.293 ;
     RECT  67.215 149.023 67.305 149.293 ;
     RECT  69.915 149.023 70.005 149.293 ;
     RECT  72.615 149.023 72.705 149.293 ;
     RECT  75.315 149.207 75.405 149.293 ;
     RECT  37.188 148.792 38.07 149.357 ;
     RECT  37.515 149.357 38.07 150.715 ;
     RECT  37.515 150.715 38.142 150.989 ;
     RECT  37.515 150.989 38.07 155.803 ;
     RECT  38.88 148.559 40.497 155.803 ;
     RECT  37.515 155.803 40.497 155.849 ;
     RECT  37.515 155.849 38.07 160.939 ;
     RECT  37.515 160.939 38.142 160.979 ;
     RECT  37.515 160.979 38.07 163.771 ;
     RECT  38.88 155.849 40.497 163.771 ;
     RECT  37.515 163.771 40.497 165.883 ;
     RECT  37.152 165.883 40.497 166.109 ;
     RECT  37.296 166.109 40.497 166.415 ;
     RECT  2.415 131.999 2.697 168.227 ;
     RECT  5.115 135.239 5.397 168.227 ;
     RECT  7.815 134.969 8.097 168.227 ;
     RECT  10.515 123.293 10.797 168.227 ;
     RECT  13.215 123.197 13.497 168.227 ;
     RECT  15.915 2.413 16.197 168.227 ;
     RECT  18.615 92.309 18.897 168.227 ;
     RECT  21.315 100.109 21.597 168.227 ;
     RECT  24.015 91.229 24.297 168.227 ;
     RECT  26.715 2.413 26.997 168.227 ;
     RECT  29.415 74.957 29.697 168.227 ;
     RECT  32.115 134.969 32.397 168.227 ;
     RECT  34.815 135.941 35.097 168.227 ;
     RECT  37.515 166.415 40.497 168.227 ;
     RECT  42.915 149.293 43.197 168.227 ;
     RECT  45.615 149.293 45.897 168.227 ;
     RECT  48.315 149.293 48.597 168.227 ;
     RECT  51.015 149.099 51.297 168.227 ;
     RECT  53.715 149.293 53.997 168.227 ;
     RECT  56.415 149.293 56.697 168.227 ;
     RECT  59.115 149.293 59.397 168.227 ;
     RECT  61.815 149.293 62.097 168.227 ;
     RECT  64.515 149.293 64.797 168.227 ;
     RECT  67.215 149.293 67.497 168.227 ;
     RECT  69.915 149.293 70.197 168.227 ;
     RECT  72.615 149.293 72.897 168.227 ;
     RECT  75.315 149.293 75.597 168.227 ;
     RECT  78.015 141.269 78.297 168.227 ;
     RECT  80.715 131.021 80.997 168.227 ;
     RECT  83.415 131.117 83.697 168.227 ;
     RECT  86.115 141.611 86.397 168.227 ;
     RECT  88.815 143.159 89.097 168.227 ;
     RECT  91.515 148.901 91.797 168.227 ;
     RECT  94.215 148.469 94.497 168.227 ;
     RECT  37.515 168.227 40.305 168.269 ;
     RECT  37.515 168.269 39.294 168.341 ;
     RECT  2.415 168.227 2.505 168.497 ;
     RECT  5.115 168.227 5.205 168.497 ;
     RECT  7.815 168.227 7.905 168.497 ;
     RECT  10.515 168.227 10.605 168.497 ;
     RECT  13.215 168.227 13.305 168.497 ;
     RECT  15.915 168.227 16.005 168.497 ;
     RECT  18.615 168.227 18.705 168.497 ;
     RECT  21.315 168.227 21.405 168.497 ;
     RECT  24.015 168.227 24.105 168.497 ;
     RECT  26.715 168.227 26.805 168.497 ;
     RECT  29.415 168.227 29.505 168.497 ;
     RECT  32.115 168.227 32.205 168.497 ;
     RECT  34.815 168.227 34.905 168.497 ;
     RECT  37.515 168.341 39.006 168.497 ;
     RECT  40.215 168.269 40.305 168.497 ;
     RECT  42.915 168.227 43.005 168.497 ;
     RECT  45.615 168.227 45.705 168.497 ;
     RECT  48.315 168.227 48.405 168.497 ;
     RECT  51.015 168.227 51.105 168.497 ;
     RECT  53.715 168.227 53.805 168.497 ;
     RECT  56.415 168.227 56.505 168.497 ;
     RECT  59.115 168.227 59.205 168.497 ;
     RECT  61.815 168.227 61.905 168.497 ;
     RECT  64.515 168.227 64.605 168.497 ;
     RECT  67.215 168.227 67.305 168.497 ;
     RECT  69.915 168.227 70.005 168.497 ;
     RECT  72.615 168.227 72.705 168.497 ;
     RECT  75.315 168.227 75.405 168.497 ;
     RECT  78.015 168.227 78.105 168.497 ;
     RECT  80.715 168.227 80.805 168.497 ;
     RECT  83.415 168.227 83.505 168.497 ;
     RECT  86.115 168.227 86.205 168.497 ;
     RECT  88.815 168.227 88.905 168.497 ;
     RECT  91.515 168.227 91.605 168.497 ;
     RECT  94.215 168.227 94.305 168.497 ;
     RECT  38.124 168.497 39.006 170.395 ;
     RECT  37.836 170.395 39.006 170.609 ;
     RECT  37.908 170.609 39.006 170.621 ;
    LAYER M4 ;
     RECT  0.06 118.08 0.097 122.568 ;
     RECT  0.06 129.888 0.097 131.784 ;
     RECT  0.06 74.304 0.137 78.792 ;
     RECT  0.097 118.08 0.137 122.664 ;
     RECT  0.06 40.896 0.569 45.384 ;
     RECT  0.06 31.68 2.252 36.168 ;
     RECT  2.252 31.68 2.408 36.264 ;
     RECT  0.569 41.136 2.408 45.384 ;
     RECT  0.137 74.352 2.408 78.792 ;
     RECT  0.06 84.672 2.408 89.16 ;
     RECT  0.137 118.224 2.408 122.664 ;
     RECT  0.097 129.792 2.408 131.784 ;
     RECT  2.408 2.148 2.512 168.492 ;
     RECT  2.512 2.418 2.704 168.222 ;
     RECT  2.704 31.68 3.449 36.12 ;
     RECT  2.704 41.136 3.485 45.432 ;
     RECT  2.704 129.792 3.485 131.832 ;
     RECT  3.449 31.728 3.701 36.12 ;
     RECT  3.701 31.968 3.913 36.12 ;
     RECT  2.704 84.672 3.989 89.16 ;
     RECT  3.989 84.96 4.025 89.16 ;
     RECT  3.913 31.968 4.412 36.168 ;
     RECT  3.485 129.936 4.561 131.832 ;
     RECT  2.704 118.368 4.625 122.664 ;
     RECT  4.645 126.096 4.669 126.12 ;
     RECT  4.412 31.968 5.108 36.696 ;
     RECT  3.485 41.184 5.108 45.432 ;
     RECT  2.704 74.448 5.108 78.792 ;
     RECT  4.025 85.104 5.108 89.16 ;
     RECT  4.625 118.368 5.108 123.096 ;
     RECT  4.669 125.424 5.108 126.12 ;
     RECT  4.561 129.936 5.108 131.976 ;
     RECT  5.108 2.148 5.212 168.492 ;
     RECT  5.212 2.418 5.404 168.222 ;
     RECT  5.404 41.28 5.465 44.904 ;
     RECT  5.404 31.776 5.501 36.12 ;
     RECT  5.404 87.312 5.501 87.768 ;
     RECT  5.404 74.64 5.573 78.792 ;
     RECT  5.573 75.168 5.681 78.792 ;
     RECT  5.404 118.32 5.681 122.424 ;
     RECT  5.501 31.776 5.717 35.448 ;
     RECT  5.465 43.296 5.717 44.904 ;
     RECT  5.404 85.488 5.717 86.28 ;
     RECT  5.681 118.32 5.717 119.016 ;
     RECT  5.681 120.24 5.717 122.424 ;
     RECT  5.681 75.792 5.753 78.792 ;
     RECT  5.717 85.488 5.753 85.704 ;
     RECT  5.753 85.68 5.789 85.704 ;
     RECT  5.753 76.32 5.861 78.792 ;
     RECT  5.404 130.8 5.897 131.976 ;
     RECT  5.501 87.408 6.083 87.768 ;
     RECT  5.717 31.776 6.113 33.528 ;
     RECT  5.717 120.24 6.131 121.992 ;
     RECT  6.113 33.504 6.329 33.528 ;
     RECT  5.465 41.28 6.419 42.168 ;
     RECT  5.717 43.296 6.419 44.184 ;
     RECT  5.861 78 6.581 78.792 ;
     RECT  6.131 120.24 6.721 121.944 ;
     RECT  5.717 34.752 6.793 35.4 ;
     RECT  6.083 87.408 6.829 87.432 ;
     RECT  5.717 118.32 6.829 118.344 ;
     RECT  6.721 120.192 6.829 121.944 ;
     RECT  6.419 44.064 6.833 44.184 ;
     RECT  6.581 78.048 6.901 78.792 ;
     RECT  6.793 34.752 7.669 35.448 ;
     RECT  7.388 39.888 7.669 39.912 ;
     RECT  6.419 41.904 7.669 42.168 ;
     RECT  5.404 92.688 7.669 92.712 ;
     RECT  7.669 89.328 7.693 89.352 ;
     RECT  6.113 31.776 7.808 31.8 ;
     RECT  7.669 34.752 7.808 36.312 ;
     RECT  7.669 39.696 7.808 39.912 ;
     RECT  7.669 41.376 7.808 42.168 ;
     RECT  6.833 44.064 7.808 44.088 ;
     RECT  6.901 45.168 7.808 45.192 ;
     RECT  7.669 70.272 7.808 70.296 ;
     RECT  6.908 75.168 7.808 75.192 ;
     RECT  5.861 76.32 7.808 77.016 ;
     RECT  6.901 78.048 7.808 79.272 ;
     RECT  6.829 87.312 7.808 87.432 ;
     RECT  7.693 89.28 7.808 89.352 ;
     RECT  7.669 92.688 7.808 93.048 ;
     RECT  7.045 104.832 7.808 104.952 ;
     RECT  6.829 118.32 7.808 121.944 ;
     RECT  7.045 123.264 7.808 123.288 ;
     RECT  5.404 125.424 7.808 125.448 ;
     RECT  5.897 130.8 7.808 131.448 ;
     RECT  7.808 2.148 7.912 168.492 ;
     RECT  7.912 2.418 8.104 168.222 ;
     RECT  8.104 41.376 8.165 41.928 ;
     RECT  8.104 76.752 8.165 77.496 ;
     RECT  8.104 121.92 8.165 121.944 ;
     RECT  8.104 45.168 8.201 45.192 ;
     RECT  8.104 85.44 8.243 85.464 ;
     RECT  8.104 88.896 8.243 89.304 ;
     RECT  8.104 104.784 8.243 104.952 ;
     RECT  8.104 118.32 8.243 119.16 ;
     RECT  8.165 41.376 8.273 41.4 ;
     RECT  8.104 86.64 8.281 87.336 ;
     RECT  8.104 123.264 8.281 123.384 ;
     RECT  8.104 35.424 8.381 36.312 ;
     RECT  8.104 130.56 8.453 131.064 ;
     RECT  8.165 77.472 8.597 77.496 ;
     RECT  8.243 104.784 8.597 104.808 ;
     RECT  8.453 131.04 8.921 131.064 ;
     RECT  8.104 70.272 10.508 70.296 ;
     RECT  8.281 87.312 10.508 87.336 ;
     RECT  8.104 92.688 10.508 93.048 ;
     RECT  8.281 123.264 10.508 123.288 ;
     RECT  10.508 2.148 10.612 168.492 ;
     RECT  10.612 2.418 10.804 168.222 ;
     RECT  10.804 123.168 10.829 123.288 ;
     RECT  10.804 70.272 13.208 70.296 ;
     RECT  10.804 87.408 13.208 87.432 ;
     RECT  10.804 92.688 13.208 92.952 ;
     RECT  10.829 123.168 13.208 123.192 ;
     RECT  13.208 2.148 13.312 168.492 ;
     RECT  13.312 2.418 13.504 168.222 ;
     RECT  13.504 87.408 14.821 87.432 ;
     RECT  13.504 92.688 14.821 92.952 ;
     RECT  13.504 123.168 14.821 123.192 ;
     RECT  14.821 87.312 14.861 87.432 ;
     RECT  14.821 123.168 14.861 123.288 ;
     RECT  13.504 70.272 15.908 70.584 ;
     RECT  15.541 74.928 15.908 74.952 ;
     RECT  14.861 87.312 15.908 87.336 ;
     RECT  14.821 92.688 15.908 93.048 ;
     RECT  14.861 123.264 15.908 123.288 ;
     RECT  15.908 2.148 16.012 168.492 ;
     RECT  16.012 2.418 16.204 168.222 ;
     RECT  16.204 70.56 18.608 70.584 ;
     RECT  16.204 74.928 18.608 74.952 ;
     RECT  16.204 87.312 18.608 87.336 ;
     RECT  16.204 92.688 18.608 93.048 ;
     RECT  16.204 123.264 18.608 123.288 ;
     RECT  18.608 2.148 18.712 168.492 ;
     RECT  18.712 2.418 18.904 168.222 ;
     RECT  18.904 92.688 20.053 92.952 ;
     RECT  20.041 118.56 20.125 118.584 ;
     RECT  20.053 91.728 20.197 92.952 ;
     RECT  18.904 70.56 20.243 70.584 ;
     RECT  20.197 91.632 20.243 92.952 ;
     RECT  18.904 74.928 21.308 74.952 ;
     RECT  18.904 87.408 21.308 87.432 ;
     RECT  20.243 91.632 21.308 91.656 ;
     RECT  20.243 92.688 21.308 92.952 ;
     RECT  20.365 119.664 21.308 119.688 ;
     RECT  18.904 123.168 21.308 123.192 ;
     RECT  20.197 127.344 21.308 127.368 ;
     RECT  21.308 2.148 21.412 168.492 ;
     RECT  21.412 2.418 21.604 168.222 ;
     RECT  21.604 74.832 21.701 74.952 ;
     RECT  21.604 99.744 22.163 100.104 ;
     RECT  21.604 91.632 22.385 92.952 ;
     RECT  22.163 99.744 22.457 99.768 ;
     RECT  22.385 91.632 22.601 91.656 ;
     RECT  21.701 74.832 22.813 74.856 ;
     RECT  21.604 87.408 22.813 87.432 ;
     RECT  22.385 92.688 22.813 92.952 ;
     RECT  22.813 74.832 22.853 74.952 ;
     RECT  22.813 87.312 22.853 87.432 ;
     RECT  22.853 74.928 24.008 74.952 ;
     RECT  22.853 87.312 24.008 87.336 ;
     RECT  22.813 92.688 24.008 93.048 ;
     RECT  21.604 127.344 24.008 127.368 ;
     RECT  21.604 142.944 24.008 142.968 ;
     RECT  24.008 2.148 24.112 168.492 ;
     RECT  24.112 2.418 24.304 168.222 ;
     RECT  24.304 74.928 26.708 74.952 ;
     RECT  24.304 87.312 26.708 87.336 ;
     RECT  24.304 92.688 26.708 93.048 ;
     RECT  24.304 127.344 26.708 127.368 ;
     RECT  24.304 142.944 26.708 142.968 ;
     RECT  26.708 2.148 26.812 168.492 ;
     RECT  26.812 2.418 27.004 168.222 ;
     RECT  27.004 74.928 29.408 74.952 ;
     RECT  27.004 87.312 29.408 87.336 ;
     RECT  27.004 92.688 29.408 93.048 ;
     RECT  27.004 127.344 29.408 127.368 ;
     RECT  27.004 142.944 29.408 142.968 ;
     RECT  29.408 2.148 29.512 168.492 ;
     RECT  29.512 2.418 29.704 168.222 ;
     RECT  29.704 74.832 29.801 74.952 ;
     RECT  29.801 74.832 30.769 74.856 ;
     RECT  29.704 87.408 30.769 87.432 ;
     RECT  29.704 92.688 30.769 92.952 ;
     RECT  30.769 74.832 30.809 74.952 ;
     RECT  30.769 87.312 30.809 87.432 ;
     RECT  30.809 74.928 32.108 74.952 ;
     RECT  30.809 87.312 32.108 87.336 ;
     RECT  30.769 92.688 32.108 93.048 ;
     RECT  29.704 127.344 32.108 127.368 ;
     RECT  29.704 142.944 32.108 142.968 ;
     RECT  32.108 2.148 32.212 168.492 ;
     RECT  32.212 2.418 32.404 168.222 ;
     RECT  32.404 127.344 34.693 127.368 ;
     RECT  32.404 74.928 34.808 74.952 ;
     RECT  32.404 87.312 34.808 87.336 ;
     RECT  32.404 92.688 34.808 93.048 ;
     RECT  34.693 127.296 34.808 127.656 ;
     RECT  34.765 131.568 34.808 131.592 ;
     RECT  32.404 142.944 34.808 142.968 ;
     RECT  34.808 2.148 34.912 168.492 ;
     RECT  34.912 2.418 35.104 168.222 ;
     RECT  35.104 127.296 35.219 127.752 ;
     RECT  35.104 121.392 35.363 123.624 ;
     RECT  35.363 122.352 35.417 123.624 ;
     RECT  35.417 122.544 35.555 123.624 ;
     RECT  35.104 125.904 35.555 126.312 ;
     RECT  35.104 129.264 35.555 132.264 ;
     RECT  35.555 132.24 35.561 132.264 ;
     RECT  35.104 124.704 35.596 124.776 ;
     RECT  35.555 129.264 35.597 131.064 ;
     RECT  35.555 123.6 35.741 123.624 ;
     RECT  35.104 133.392 35.741 134.088 ;
     RECT  35.104 135.072 35.891 135.336 ;
     RECT  35.104 136.704 35.932 137.4 ;
     RECT  35.555 126.288 36.035 126.312 ;
     RECT  35.741 133.872 36.065 134.088 ;
     RECT  35.596 124.704 36.133 124.728 ;
     RECT  35.597 129.264 36.209 130.776 ;
     RECT  35.932 137.376 36.245 137.4 ;
     RECT  35.219 127.344 36.277 127.752 ;
     RECT  35.891 135.072 36.277 135.096 ;
     RECT  36.277 127.104 36.467 127.752 ;
     RECT  35.104 119.568 36.524 119.832 ;
     RECT  36.421 118.08 36.673 118.104 ;
     RECT  35.555 122.544 36.673 122.568 ;
     RECT  36.673 122.544 36.745 123.048 ;
     RECT  36.133 124.128 36.745 124.728 ;
     RECT  36.277 134.736 36.889 135.096 ;
     RECT  36.745 122.544 36.997 124.728 ;
     RECT  36.889 134.736 37.052 135.192 ;
     RECT  36.781 131.04 37.141 131.112 ;
     RECT  36.925 132.096 37.141 132.12 ;
     RECT  36.997 122.544 37.177 125.064 ;
     RECT  36.209 129.264 37.237 129.816 ;
     RECT  37.141 131.04 37.237 132.12 ;
     RECT  37.237 129.264 37.285 132.12 ;
     RECT  36.997 113.808 37.349 113.832 ;
     RECT  36.709 97.392 37.381 97.416 ;
     RECT  37.177 122.544 37.381 125.736 ;
     RECT  37.237 141.84 37.393 141.864 ;
     RECT  37.285 129.264 37.501 132.936 ;
     RECT  35.104 74.928 37.508 74.952 ;
     RECT  35.104 87.312 37.508 87.336 ;
     RECT  35.104 92.688 37.508 93.048 ;
     RECT  37.381 96.288 37.508 97.416 ;
     RECT  37.349 113.808 37.508 113.976 ;
     RECT  36.673 118.08 37.508 118.584 ;
     RECT  36.524 119.568 37.508 120.648 ;
     RECT  37.381 121.872 37.508 125.736 ;
     RECT  36.467 127.344 37.508 127.752 ;
     RECT  37.501 129.264 37.508 133.56 ;
     RECT  37.052 134.736 37.508 135.48 ;
     RECT  37.285 136.752 37.508 136.776 ;
     RECT  36.781 138.144 37.508 138.648 ;
     RECT  37.393 141.312 37.508 141.864 ;
     RECT  35.104 142.944 37.508 142.968 ;
     RECT  37.429 146.4 37.508 146.424 ;
     RECT  37.177 148.8 37.508 149.352 ;
     RECT  37.141 165.888 37.508 165.912 ;
     RECT  37.508 2.148 37.612 168.492 ;
     RECT  37.612 2.418 37.804 168.222 ;
     RECT  37.804 124.368 37.865 128.232 ;
     RECT  37.804 74.832 37.901 74.952 ;
     RECT  37.865 124.368 37.955 124.728 ;
     RECT  37.825 170.4 37.957 170.424 ;
     RECT  37.804 132.912 37.973 135.144 ;
     RECT  37.957 170.4 38.044 170.52 ;
     RECT  37.865 125.712 38.051 128.232 ;
     RECT  37.804 136.368 38.051 136.872 ;
     RECT  37.804 121.392 38.117 123.336 ;
     RECT  38.051 136.368 38.147 136.776 ;
     RECT  37.804 140.208 38.147 141.336 ;
     RECT  37.804 145.872 38.147 146.424 ;
     RECT  37.804 155.808 38.147 156.168 ;
     RECT  38.044 170.4 38.147 170.424 ;
     RECT  38.147 140.208 38.153 141.192 ;
     RECT  38.147 145.872 38.153 146.136 ;
     RECT  37.804 150.72 38.153 150.84 ;
     RECT  37.804 160.944 38.153 161.304 ;
     RECT  37.955 124.56 38.189 124.728 ;
     RECT  37.804 129.408 38.195 131.064 ;
     RECT  38.153 150.816 38.195 150.84 ;
     RECT  38.153 161.28 38.195 161.304 ;
     RECT  37.804 162.48 38.195 162.504 ;
     RECT  38.147 155.808 38.233 155.832 ;
     RECT  37.804 166.944 38.243 167.064 ;
     RECT  37.804 165.456 38.261 165.624 ;
     RECT  38.153 140.208 38.339 140.232 ;
     RECT  37.804 142.944 38.339 143.256 ;
     RECT  37.804 168.144 38.435 168.168 ;
     RECT  38.243 166.992 38.476 167.064 ;
     RECT  38.261 165.6 38.483 165.624 ;
     RECT  38.117 122.112 38.549 123.336 ;
     RECT  37.804 148.224 38.579 148.296 ;
     RECT  37.973 132.912 38.585 135.096 ;
     RECT  37.804 144.336 38.675 144.36 ;
     RECT  37.804 163.776 38.675 163.8 ;
     RECT  38.189 124.56 38.765 124.632 ;
     RECT  38.195 129.408 38.801 130.344 ;
     RECT  38.579 148.272 38.801 148.296 ;
     RECT  38.476 167.04 38.801 167.064 ;
     RECT  37.804 92.688 38.869 93.864 ;
     RECT  38.765 124.56 38.873 124.584 ;
     RECT  38.153 145.872 38.873 145.896 ;
     RECT  37.804 50.736 38.905 50.76 ;
     RECT  38.585 134.304 38.972 135.096 ;
     RECT  38.147 136.368 38.972 136.536 ;
     RECT  38.051 126.432 39.013 128.232 ;
     RECT  38.801 129.408 39.013 129.912 ;
     RECT  38.972 134.304 39.053 136.536 ;
     RECT  39.053 134.304 39.059 135.72 ;
     RECT  39.059 134.304 39.117 134.328 ;
     RECT  39.013 126.432 39.197 129.912 ;
     RECT  38.869 91.92 39.337 93.864 ;
     RECT  38.549 122.112 39.337 123.288 ;
     RECT  38.869 132.672 39.373 132.696 ;
     RECT  37.804 138.624 39.373 138.648 ;
     RECT  39.229 89.712 39.445 89.736 ;
     RECT  39.337 91.392 39.445 93.864 ;
     RECT  37.804 87.408 39.517 87.432 ;
     RECT  38.339 142.944 39.517 142.968 ;
     RECT  38.905 50.544 39.589 50.76 ;
     RECT  37.804 52.176 39.589 52.2 ;
     RECT  37.804 96.912 39.685 96.936 ;
     RECT  39.445 89.712 39.692 93.864 ;
     RECT  39.685 96.048 39.697 96.936 ;
     RECT  39.373 132.576 39.697 132.696 ;
     RECT  37.804 83.76 39.733 83.784 ;
     RECT  39.373 138.624 39.769 138.984 ;
     RECT  39.589 40.56 39.841 40.584 ;
     RECT  39.589 50.544 39.877 52.2 ;
     RECT  39.841 48.672 39.913 48.696 ;
     RECT  39.913 48.672 39.949 49.032 ;
     RECT  39.877 50.304 39.949 52.2 ;
     RECT  39.733 45.504 39.985 45.528 ;
     RECT  39.949 48.672 39.985 52.2 ;
     RECT  39.517 87.408 40.021 88.392 ;
     RECT  39.692 89.712 40.021 94.008 ;
     RECT  39.337 121.392 40.021 123.288 ;
     RECT  39.985 48.48 40.057 52.2 ;
     RECT  40.021 121.392 40.057 123.336 ;
     RECT  37.901 74.832 40.069 74.856 ;
     RECT  40.057 121.392 40.165 123.48 ;
     RECT  39.841 40.56 40.208 41.304 ;
     RECT  39.985 45.456 40.208 45.528 ;
     RECT  40.057 47.712 40.208 52.2 ;
     RECT  40.069 74.832 40.208 75.192 ;
     RECT  39.733 83.76 40.208 84.12 ;
     RECT  40.021 87.408 40.208 94.008 ;
     RECT  39.697 95.184 40.208 96.936 ;
     RECT  37.804 118.08 40.208 118.104 ;
     RECT  40.165 121.392 40.208 124.104 ;
     RECT  39.197 126.432 40.208 128.04 ;
     RECT  39.197 129.12 40.208 129.912 ;
     RECT  39.697 131.664 40.208 132.696 ;
     RECT  40.129 134.256 40.208 134.28 ;
     RECT  39.059 135.696 40.208 135.72 ;
     RECT  39.769 138.528 40.208 138.984 ;
     RECT  39.481 140.208 40.208 140.232 ;
     RECT  39.481 141.312 40.208 141.336 ;
     RECT  39.517 142.512 40.208 142.968 ;
     RECT  39.013 144.528 40.208 144.552 ;
     RECT  40.208 2.148 40.312 168.492 ;
     RECT  40.312 2.418 40.504 168.222 ;
     RECT  40.504 47.712 40.601 52.248 ;
     RECT  40.504 122.112 40.643 127.32 ;
     RECT  40.504 40.56 40.817 41.064 ;
     RECT  40.643 122.112 40.853 124.584 ;
     RECT  40.853 124.08 40.889 124.584 ;
     RECT  40.504 142.512 41.033 142.536 ;
     RECT  40.504 120.768 41.267 120.792 ;
     RECT  40.504 114.528 41.465 114.552 ;
     RECT  40.504 53.376 41.497 53.688 ;
     RECT  40.504 45.504 41.533 45.528 ;
     RECT  40.601 47.808 41.533 52.248 ;
     RECT  41.497 53.28 41.533 53.688 ;
     RECT  40.853 122.112 41.537 122.808 ;
     RECT  41.533 132.576 41.569 132.6 ;
     RECT  40.504 134.208 41.605 135.192 ;
     RECT  40.889 124.56 41.641 124.584 ;
     RECT  40.643 125.616 41.641 127.32 ;
     RECT  41.605 134.208 41.641 135.48 ;
     RECT  41.533 45.504 41.677 45.816 ;
     RECT  40.817 40.56 41.713 40.584 ;
     RECT  41.677 45.504 41.713 46.68 ;
     RECT  41.533 47.808 41.713 53.688 ;
     RECT  40.504 83.76 41.749 84.12 ;
     RECT  41.569 132.576 41.785 132.696 ;
     RECT  41.785 132.096 41.821 132.696 ;
     RECT  41.749 114 41.833 114.024 ;
     RECT  41.713 34.8 41.861 34.824 ;
     RECT  41.713 45.504 41.893 53.688 ;
     RECT  41.893 45.312 41.929 53.688 ;
     RECT  41.821 131.52 41.965 132.696 ;
     RECT  41.713 39.888 41.996 40.584 ;
     RECT  41.965 131.424 42.001 132.696 ;
     RECT  41.641 133.824 42.001 135.48 ;
     RECT  41.996 39.456 42.044 40.584 ;
     RECT  42.001 131.424 42.109 135.48 ;
     RECT  42.001 42.72 42.113 42.744 ;
     RECT  41.929 44.736 42.133 53.688 ;
     RECT  42.109 131.136 42.145 135.48 ;
     RECT  40.504 137.376 42.145 140.184 ;
     RECT  42.044 39.36 42.217 40.584 ;
     RECT  42.145 128.784 42.217 128.808 ;
     RECT  41.641 124.56 42.253 127.32 ;
     RECT  42.145 130.752 42.253 135.48 ;
     RECT  42.289 37.632 42.325 37.656 ;
     RECT  41.749 83.568 42.325 84.12 ;
     RECT  42.253 124.32 42.325 127.368 ;
     RECT  40.504 87.936 42.373 96.984 ;
     RECT  42.133 44.448 42.421 53.688 ;
     RECT  41.929 120.384 42.421 120.408 ;
     RECT  40.504 103.824 42.433 103.848 ;
     RECT  42.421 44.352 42.469 53.688 ;
     RECT  42.421 120.384 42.469 120.888 ;
     RECT  42.469 120.384 42.505 120.984 ;
     RECT  42.373 87.36 42.517 96.984 ;
     RECT  41.537 122.112 42.541 122.712 ;
     RECT  42.325 124.176 42.541 127.368 ;
     RECT  42.325 36.768 42.572 37.656 ;
     RECT  42.325 82.656 42.613 84.12 ;
     RECT  42.541 122.112 42.613 127.368 ;
     RECT  42.217 128.736 42.613 128.808 ;
     RECT  42.469 44.16 42.661 53.688 ;
     RECT  42.565 64.704 42.661 64.728 ;
     RECT  42.613 122.112 42.661 128.808 ;
     RECT  42.613 107.28 42.709 107.304 ;
     RECT  42.661 122.112 42.709 129.576 ;
     RECT  42.253 130.56 42.709 135.48 ;
     RECT  42.661 64.608 42.757 64.728 ;
     RECT  42.505 120.288 42.757 120.984 ;
     RECT  42.709 122.112 42.757 135.48 ;
     RECT  42.757 120.288 42.761 135.48 ;
     RECT  42.613 34.752 42.908 34.776 ;
     RECT  42.572 36.48 42.908 37.656 ;
     RECT  42.217 38.784 42.908 40.584 ;
     RECT  42.757 64.608 42.908 64.968 ;
     RECT  42.613 82.656 42.908 84.36 ;
     RECT  42.709 107.28 42.908 108.216 ;
     RECT  40.504 118.08 42.908 118.104 ;
     RECT  42.761 120.288 42.908 128.232 ;
     RECT  42.661 43.968 42.973 53.688 ;
     RECT  42.908 2.148 43.012 41.052 ;
     RECT  42.908 62.628 43.012 84.36 ;
     RECT  42.908 105.828 43.012 128.232 ;
     RECT  42.908 149.028 43.012 168.492 ;
     RECT  42.761 129.36 43.2 135.48 ;
     RECT  42.145 137.28 43.2 140.184 ;
     RECT  43.012 2.418 43.204 40.782 ;
     RECT  43.012 62.898 43.204 84.36 ;
     RECT  43.012 106.098 43.204 128.232 ;
     RECT  43.012 149.298 43.204 168.222 ;
     RECT  43.204 64.608 43.229 64.968 ;
     RECT  43.204 107.28 43.265 108.552 ;
     RECT  43.204 126.24 43.265 126.264 ;
     RECT  43.204 127.248 43.265 128.232 ;
     RECT  43.2 129.36 43.265 140.184 ;
     RECT  42.973 43.968 43.272 54.12 ;
     RECT  42.517 87.168 43.272 96.984 ;
     RECT  42.433 103.776 43.272 103.848 ;
     RECT  43.265 129.456 43.272 140.184 ;
     RECT  40.504 147.072 43.272 147.24 ;
     RECT  43.229 64.608 43.331 64.872 ;
     RECT  43.272 129.456 43.331 147.24 ;
     RECT  43.265 108.192 43.409 108.552 ;
     RECT  43.331 64.608 43.553 64.728 ;
     RECT  43.204 83.28 43.553 84.36 ;
     RECT  43.204 40.56 45.608 40.584 ;
     RECT  43.553 83.76 45.608 84.12 ;
     RECT  43.204 118.08 45.608 118.104 ;
     RECT  43.204 122.688 45.608 122.712 ;
     RECT  43.265 127.248 45.608 127.32 ;
     RECT  45.608 2.148 45.712 41.052 ;
     RECT  45.608 62.628 45.712 84.252 ;
     RECT  45.608 105.828 45.712 127.452 ;
     RECT  45.608 149.028 45.712 168.492 ;
     RECT  45.712 2.418 45.904 40.872 ;
     RECT  45.712 62.898 45.904 84.12 ;
     RECT  45.712 106.098 45.904 127.272 ;
     RECT  45.712 149.298 45.904 168.222 ;
     RECT  45.904 40.56 46.541 40.872 ;
     RECT  45.904 83.76 46.753 84.12 ;
     RECT  46.541 40.848 48.308 40.872 ;
     RECT  46.753 83.76 48.308 84.168 ;
     RECT  45.904 118.08 48.308 118.104 ;
     RECT  45.904 122.688 48.308 122.712 ;
     RECT  45.904 127.248 48.308 127.272 ;
     RECT  48.308 2.148 48.412 41.052 ;
     RECT  48.308 62.628 48.412 84.252 ;
     RECT  48.308 105.828 48.412 127.452 ;
     RECT  48.308 149.028 48.412 168.492 ;
     RECT  48.412 2.418 48.604 40.872 ;
     RECT  48.412 62.898 48.604 84.168 ;
     RECT  48.412 106.098 48.604 127.272 ;
     RECT  48.412 149.298 48.604 168.222 ;
     RECT  48.604 40.848 51.008 40.872 ;
     RECT  48.604 83.76 51.008 84.168 ;
     RECT  48.604 118.08 51.008 118.104 ;
     RECT  48.604 122.688 51.008 122.712 ;
     RECT  48.604 127.248 51.008 127.272 ;
     RECT  51.008 2.148 51.112 41.052 ;
     RECT  51.008 62.628 51.112 84.252 ;
     RECT  51.008 105.828 51.112 127.452 ;
     RECT  51.008 149.028 51.112 168.492 ;
     RECT  51.112 2.418 51.304 40.872 ;
     RECT  51.112 62.898 51.304 84.168 ;
     RECT  51.112 106.098 51.304 127.272 ;
     RECT  51.112 149.298 51.304 168.222 ;
     RECT  51.304 40.848 53.708 40.872 ;
     RECT  51.304 83.76 53.708 84.168 ;
     RECT  51.304 118.08 53.708 118.104 ;
     RECT  51.304 122.688 53.708 122.712 ;
     RECT  51.304 127.248 53.708 127.272 ;
     RECT  53.708 2.148 53.812 41.052 ;
     RECT  53.708 62.628 53.812 84.252 ;
     RECT  53.708 105.828 53.812 127.452 ;
     RECT  53.708 149.028 53.812 168.492 ;
     RECT  53.812 2.418 54.004 40.872 ;
     RECT  53.812 62.898 54.004 84.168 ;
     RECT  53.812 106.098 54.004 127.272 ;
     RECT  53.812 149.298 54.004 168.222 ;
     RECT  54.004 122.688 55.717 122.712 ;
     RECT  54.004 127.248 55.717 127.272 ;
     RECT  55.717 127.104 55.933 127.272 ;
     RECT  54.004 40.848 56.408 40.872 ;
     RECT  54.004 83.76 56.408 84.168 ;
     RECT  54.004 118.08 56.408 118.104 ;
     RECT  55.717 122.688 56.408 122.952 ;
     RECT  55.933 127.056 56.408 127.272 ;
     RECT  56.408 2.148 56.512 41.052 ;
     RECT  56.408 62.628 56.512 84.252 ;
     RECT  56.408 105.828 56.512 127.452 ;
     RECT  56.408 149.028 56.512 168.492 ;
     RECT  56.512 2.418 56.704 40.872 ;
     RECT  56.512 62.898 56.704 84.168 ;
     RECT  56.512 106.098 56.704 127.182 ;
     RECT  56.512 149.298 56.704 168.222 ;
     RECT  56.704 122.64 56.765 122.952 ;
     RECT  56.704 40.848 57.517 40.872 ;
     RECT  57.517 40.848 59.108 40.92 ;
     RECT  56.704 83.76 59.108 84.168 ;
     RECT  56.704 118.08 59.108 118.104 ;
     RECT  56.765 122.64 59.108 122.664 ;
     RECT  56.704 127.056 59.108 127.08 ;
     RECT  59.108 2.148 59.212 41.052 ;
     RECT  59.108 62.628 59.212 84.252 ;
     RECT  59.108 105.828 59.212 127.452 ;
     RECT  59.108 149.028 59.212 168.492 ;
     RECT  59.212 2.418 59.404 40.92 ;
     RECT  59.212 62.898 59.404 84.168 ;
     RECT  59.212 106.098 59.404 127.182 ;
     RECT  59.212 149.298 59.404 168.222 ;
     RECT  59.404 40.848 61.808 40.92 ;
     RECT  59.404 83.76 61.808 84.168 ;
     RECT  59.404 118.08 61.808 118.104 ;
     RECT  59.404 122.64 61.808 122.664 ;
     RECT  59.404 127.056 61.808 127.08 ;
     RECT  61.808 2.148 61.912 41.052 ;
     RECT  61.808 62.628 61.912 84.252 ;
     RECT  61.808 105.828 61.912 127.452 ;
     RECT  61.808 149.028 61.912 168.492 ;
     RECT  61.912 2.418 62.104 40.92 ;
     RECT  61.912 62.898 62.104 84.168 ;
     RECT  61.912 106.098 62.104 127.182 ;
     RECT  61.912 149.298 62.104 168.222 ;
     RECT  62.104 83.76 62.309 84.168 ;
     RECT  62.104 118.08 63.164 118.104 ;
     RECT  63.164 118.08 63.251 118.152 ;
     RECT  62.104 127.056 63.251 127.08 ;
     RECT  62.309 83.76 64.501 84.072 ;
     RECT  62.104 40.848 64.508 40.92 ;
     RECT  64.501 83.76 64.508 84.168 ;
     RECT  63.205 108.144 64.508 108.168 ;
     RECT  63.251 118.08 64.508 118.104 ;
     RECT  62.104 122.64 64.508 122.664 ;
     RECT  64.508 2.148 64.612 41.052 ;
     RECT  64.508 62.628 64.612 84.252 ;
     RECT  64.508 105.828 64.612 127.452 ;
     RECT  64.508 149.028 64.612 168.492 ;
     RECT  64.612 2.418 64.804 41.016 ;
     RECT  64.612 62.898 64.804 84.168 ;
     RECT  64.612 105.828 64.804 127.182 ;
     RECT  64.612 149.298 64.804 168.222 ;
     RECT  64.804 83.232 65.161 84.168 ;
     RECT  64.804 40.848 65.233 41.016 ;
     RECT  64.804 78.048 65.441 78.12 ;
     RECT  64.804 107.76 65.441 108.168 ;
     RECT  65.077 105.456 65.459 105.48 ;
     RECT  65.441 107.76 65.459 107.784 ;
     RECT  65.161 83.472 65.485 84.168 ;
     RECT  64.804 106.56 65.485 106.584 ;
     RECT  65.441 78.096 65.843 78.12 ;
     RECT  65.485 83.856 66.089 84.168 ;
     RECT  65.233 40.848 67.208 40.92 ;
     RECT  65.797 65.712 67.208 65.736 ;
     RECT  64.804 75.456 67.208 75.48 ;
     RECT  66.089 83.856 67.208 84.072 ;
     RECT  64.804 118.08 67.208 118.104 ;
     RECT  64.804 122.64 67.208 122.664 ;
     RECT  67.208 2.148 67.312 41.052 ;
     RECT  67.208 62.628 67.312 84.252 ;
     RECT  67.208 105.828 67.312 127.452 ;
     RECT  67.208 149.028 67.312 168.492 ;
     RECT  67.312 2.418 67.504 40.92 ;
     RECT  67.312 62.898 67.504 84.072 ;
     RECT  67.312 106.098 67.504 127.182 ;
     RECT  67.312 149.298 67.504 168.222 ;
     RECT  67.504 40.848 69.908 40.92 ;
     RECT  67.504 65.712 69.908 65.736 ;
     RECT  67.504 75.456 69.908 75.48 ;
     RECT  67.504 83.856 69.908 84.072 ;
     RECT  67.504 118.08 69.908 118.104 ;
     RECT  67.504 122.64 69.908 122.664 ;
     RECT  69.908 2.148 70.012 41.052 ;
     RECT  69.908 62.628 70.012 84.252 ;
     RECT  69.908 105.828 70.012 127.452 ;
     RECT  69.908 149.028 70.012 168.492 ;
     RECT  70.012 2.418 70.204 40.92 ;
     RECT  70.012 62.898 70.204 84.12 ;
     RECT  70.012 106.098 70.204 127.182 ;
     RECT  70.012 149.298 70.204 168.222 ;
     RECT  70.204 83.76 70.835 84.12 ;
     RECT  70.204 40.848 72.608 40.92 ;
     RECT  70.204 65.712 72.608 65.736 ;
     RECT  70.204 75.456 72.608 75.48 ;
     RECT  70.835 83.856 72.608 84.12 ;
     RECT  70.204 118.08 72.608 118.104 ;
     RECT  70.204 122.64 72.608 122.664 ;
     RECT  72.608 2.148 72.712 41.052 ;
     RECT  72.608 62.628 72.712 84.252 ;
     RECT  72.608 105.828 72.712 127.452 ;
     RECT  72.608 149.028 72.712 168.492 ;
     RECT  72.712 2.418 72.904 40.92 ;
     RECT  72.712 62.898 72.904 84.12 ;
     RECT  72.712 106.098 72.904 127.182 ;
     RECT  72.712 149.298 72.904 168.222 ;
     RECT  72.904 123.696 73.708 124.296 ;
     RECT  72.904 125.424 73.811 125.448 ;
     RECT  72.904 122.64 73.973 122.664 ;
     RECT  72.904 126.576 74.293 126.6 ;
     RECT  74.293 126.384 74.329 126.6 ;
     RECT  73.969 125.376 74.339 125.4 ;
     RECT  43.331 129.6 74.941 147.24 ;
     RECT  74.941 129.36 75.049 147.24 ;
     RECT  72.904 40.848 75.116 40.92 ;
     RECT  73.708 124.272 75.116 124.296 ;
     RECT  43.272 43.2 75.12 60.504 ;
     RECT  43.272 86.4 75.12 103.848 ;
     RECT  75.049 128.832 75.12 147.24 ;
     RECT  72.904 83.856 75.121 84.12 ;
     RECT  75.12 43.2 75.157 53.88 ;
     RECT  74.329 126.384 75.157 126.744 ;
     RECT  75.116 40.848 75.203 41.64 ;
     RECT  75.12 128.832 75.269 140.184 ;
     RECT  75.12 87.168 75.305 96.984 ;
     RECT  75.203 40.848 75.308 41.052 ;
     RECT  72.904 65.712 75.308 65.736 ;
     RECT  72.904 75.456 75.308 75.48 ;
     RECT  75.121 83.856 75.308 84.504 ;
     RECT  72.904 118.08 75.308 118.104 ;
     RECT  75.116 124.224 75.308 124.296 ;
     RECT  75.157 125.424 75.308 126.744 ;
     RECT  75.157 43.056 75.341 53.88 ;
     RECT  75.308 62.628 75.341 84.504 ;
     RECT  75.269 129.36 75.341 140.184 ;
     RECT  75.341 44.064 75.377 53.688 ;
     RECT  75.341 129.36 75.377 140.088 ;
     RECT  75.308 2.148 75.412 41.052 ;
     RECT  75.341 62.628 75.412 84.252 ;
     RECT  75.308 105.828 75.412 127.452 ;
     RECT  75.308 149.028 75.412 168.492 ;
     RECT  75.341 43.056 75.449 43.08 ;
     RECT  75.305 87.264 75.485 96.888 ;
     RECT  75.377 129.36 75.557 139.992 ;
     RECT  75.377 44.064 75.593 53.592 ;
     RECT  75.412 2.418 75.604 40.92 ;
     RECT  75.412 62.898 75.604 84.12 ;
     RECT  75.412 106.098 75.604 127.272 ;
     RECT  75.412 149.298 75.604 168.222 ;
     RECT  75.12 103.776 75.701 103.848 ;
     RECT  75.557 129.36 75.701 139.896 ;
     RECT  75.604 124.224 75.731 124.248 ;
     RECT  75.604 126 75.779 127.272 ;
     RECT  75.701 129.408 75.827 139.896 ;
     RECT  75.604 75.456 75.917 75.576 ;
     RECT  75.917 75.552 76.259 75.576 ;
     RECT  75.604 83.856 76.259 84.12 ;
     RECT  75.593 44.064 76.385 53.496 ;
     RECT  75.827 130.368 76.493 139.896 ;
     RECT  75.604 73.296 76.673 73.32 ;
     RECT  75.485 87.264 76.673 96.792 ;
     RECT  76.385 48.672 76.709 53.496 ;
     RECT  76.493 135.168 76.709 139.896 ;
     RECT  76.673 87.264 76.781 96.696 ;
     RECT  76.709 135.168 77.749 139.704 ;
     RECT  75.604 40.848 78.008 40.92 ;
     RECT  76.385 44.064 78.008 47.64 ;
     RECT  76.709 48.672 78.008 53.4 ;
     RECT  75.604 65.712 78.008 65.736 ;
     RECT  77.461 70.656 78.008 70.68 ;
     RECT  77.461 72.96 78.008 72.984 ;
     RECT  76.259 84.048 78.008 84.12 ;
     RECT  76.781 87.264 78.008 96.408 ;
     RECT  75.701 103.776 78.008 103.8 ;
     RECT  75.604 118.08 78.008 118.104 ;
     RECT  75.779 126.192 78.008 127.272 ;
     RECT  76.493 130.368 78.008 133.848 ;
     RECT  77.749 135.168 78.008 139.992 ;
     RECT  75.12 147.072 78.008 147.24 ;
     RECT  78.008 2.148 78.112 168.492 ;
     RECT  78.112 2.418 78.304 168.222 ;
     RECT  78.304 67.824 78.659 68.232 ;
     RECT  78.304 70.128 78.689 70.152 ;
     RECT  78.304 139.968 78.689 140.088 ;
     RECT  78.304 65.712 79.057 66.12 ;
     RECT  78.659 67.824 79.265 67.848 ;
     RECT  78.304 40.848 79.523 40.92 ;
     RECT  79.523 40.848 80.708 40.872 ;
     RECT  78.304 44.064 80.708 47.64 ;
     RECT  79.057 65.712 80.708 65.736 ;
     RECT  78.304 84.048 80.708 84.12 ;
     RECT  80.197 85.392 80.708 85.416 ;
     RECT  78.304 87.264 80.708 90.888 ;
     RECT  78.304 103.776 80.708 103.8 ;
     RECT  78.304 118.08 80.708 118.104 ;
     RECT  78.304 126.192 80.708 127.272 ;
     RECT  78.304 130.464 80.708 132.408 ;
     RECT  78.689 139.968 80.708 139.992 ;
     RECT  78.304 147.072 80.708 147.24 ;
     RECT  80.708 2.148 80.812 168.492 ;
     RECT  80.812 2.418 81.004 168.222 ;
     RECT  81.004 139.968 82.645 139.992 ;
     RECT  81.004 84.048 82.844 84.12 ;
     RECT  81.004 85.392 82.844 85.416 ;
     RECT  81.004 40.848 83.408 40.872 ;
     RECT  81.004 44.064 83.408 47.64 ;
     RECT  81.004 65.712 83.408 65.736 ;
     RECT  82.885 76.752 83.408 76.776 ;
     RECT  82.844 84.048 83.408 85.416 ;
     RECT  81.004 87.264 83.408 90.888 ;
     RECT  81.004 103.776 83.408 103.8 ;
     RECT  81.004 118.08 83.408 118.104 ;
     RECT  81.004 126.144 83.408 127.272 ;
     RECT  81.004 130.464 83.408 132.408 ;
     RECT  82.645 139.968 83.408 140.232 ;
     RECT  81.004 147.072 83.408 147.24 ;
     RECT  83.408 2.148 83.512 168.492 ;
     RECT  83.512 2.418 83.704 168.222 ;
     RECT  83.704 44.064 84.557 47.64 ;
     RECT  83.704 87.264 84.593 90.888 ;
     RECT  83.704 118.08 85.057 118.104 ;
     RECT  85.189 139.152 86.029 139.176 ;
     RECT  83.704 40.848 86.108 40.872 ;
     RECT  84.557 44.064 86.108 47.16 ;
     RECT  83.704 65.712 86.108 65.736 ;
     RECT  83.704 76.464 86.108 76.488 ;
     RECT  83.704 84.048 86.108 85.416 ;
     RECT  84.593 87.312 86.108 90.888 ;
     RECT  84.733 99.792 86.108 99.816 ;
     RECT  83.704 103.776 86.108 103.8 ;
     RECT  85.057 117.408 86.108 118.104 ;
     RECT  83.704 125.904 86.108 127.032 ;
     RECT  83.704 130.464 86.108 132.408 ;
     RECT  86.029 138.96 86.108 139.176 ;
     RECT  83.704 140.208 86.108 140.232 ;
     RECT  83.704 147.072 86.108 147.24 ;
     RECT  86.108 2.148 86.212 168.492 ;
     RECT  86.212 2.418 86.404 168.222 ;
     RECT  86.404 116.688 86.681 116.808 ;
     RECT  86.404 138.96 86.969 140.232 ;
     RECT  86.404 99.792 87.545 100.392 ;
     RECT  87.545 100.08 88.153 100.392 ;
     RECT  86.404 40.848 88.808 40.872 ;
     RECT  88.765 42.576 88.808 42.6 ;
     RECT  86.404 44.064 88.808 47.16 ;
     RECT  86.404 65.712 88.808 65.736 ;
     RECT  86.404 76.464 88.808 76.488 ;
     RECT  86.404 84.048 88.808 84.888 ;
     RECT  86.404 87.312 88.808 90.888 ;
     RECT  88.153 100.08 88.808 100.632 ;
     RECT  86.404 103.776 88.808 103.8 ;
     RECT  86.681 116.784 88.808 116.808 ;
     RECT  86.404 125.904 88.808 127.032 ;
     RECT  86.404 130.464 88.808 132.408 ;
     RECT  86.969 139.92 88.808 140.232 ;
     RECT  86.404 147.072 88.808 147.24 ;
     RECT  88.808 2.148 88.912 168.492 ;
     RECT  88.912 2.418 89.104 168.222 ;
     RECT  89.104 40.848 89.219 40.872 ;
     RECT  89.104 116.256 89.219 116.808 ;
     RECT  89.104 125.568 89.245 127.032 ;
     RECT  89.104 42.576 89.273 47.16 ;
     RECT  89.273 43.68 89.315 47.16 ;
     RECT  89.104 107.76 89.315 108.264 ;
     RECT  89.219 116.256 89.315 116.616 ;
     RECT  89.315 116.256 89.373 116.328 ;
     RECT  89.315 44.064 89.411 47.16 ;
     RECT  89.104 84.048 89.459 90.888 ;
     RECT  89.104 96.384 89.459 96.888 ;
     RECT  89.104 100.032 89.459 100.872 ;
     RECT  89.373 116.304 89.489 116.328 ;
     RECT  89.104 52.656 89.525 53.592 ;
     RECT  89.104 130.464 89.525 132.408 ;
     RECT  89.104 139.92 89.596 142.344 ;
     RECT  89.315 107.76 89.651 107.784 ;
     RECT  89.459 84.144 90.083 90.888 ;
     RECT  89.104 55.536 90.097 55.56 ;
     RECT  89.596 139.92 90.097 141.576 ;
     RECT  89.525 130.56 90.101 132.408 ;
     RECT  90.097 55.536 90.137 56.952 ;
     RECT  89.104 98.736 90.137 99 ;
     RECT  90.101 130.752 90.137 132.408 ;
     RECT  89.273 42.576 90.236 42.6 ;
     RECT  90.137 56.016 90.241 56.952 ;
     RECT  89.104 82.656 90.241 82.728 ;
     RECT  90.137 98.976 90.241 99 ;
     RECT  89.459 100.032 90.241 100.632 ;
     RECT  90.236 41.808 90.277 42.6 ;
     RECT  90.241 82.656 90.277 82.968 ;
     RECT  90.277 41.808 90.323 42.744 ;
     RECT  89.104 76.464 90.323 76.488 ;
     RECT  89.459 96.576 90.349 96.888 ;
     RECT  90.241 98.976 90.389 100.632 ;
     RECT  90.421 40.416 90.517 40.44 ;
     RECT  90.517 40.416 90.524 40.632 ;
     RECT  90.421 41.616 90.524 41.64 ;
     RECT  90.323 42.672 90.565 42.744 ;
     RECT  89.411 44.064 90.565 47.064 ;
     RECT  90.524 54.096 90.565 54.12 ;
     RECT  90.097 139.392 90.565 141.576 ;
     RECT  90.097 143.088 90.565 143.112 ;
     RECT  90.241 56.016 90.853 57.096 ;
     RECT  89.525 52.656 90.889 52.68 ;
     RECT  90.889 52.656 90.997 53.016 ;
     RECT  90.565 54.096 90.997 54.696 ;
     RECT  90.083 84.144 91.069 85.128 ;
     RECT  90.083 86.304 91.069 90.888 ;
     RECT  90.524 40.416 91.105 41.64 ;
     RECT  90.997 52.656 91.105 54.696 ;
     RECT  90.349 96.576 91.34 97.032 ;
     RECT  91.105 39.6 91.381 41.64 ;
     RECT  91.381 39.312 91.508 41.64 ;
     RECT  90.565 42.672 91.508 47.064 ;
     RECT  91.105 52.656 91.508 54.888 ;
     RECT  90.853 56.016 91.508 57.144 ;
     RECT  89.104 65.712 91.508 65.736 ;
     RECT  90.277 82.08 91.508 82.968 ;
     RECT  91.069 84.144 91.508 90.888 ;
     RECT  91.34 96.576 91.508 97.512 ;
     RECT  90.389 98.976 91.508 100.296 ;
     RECT  89.104 103.776 91.508 103.8 ;
     RECT  89.245 125.904 91.508 127.032 ;
     RECT  90.137 130.848 91.508 132.408 ;
     RECT  90.565 139.392 91.508 143.112 ;
     RECT  89.104 147.072 91.508 147.24 ;
     RECT  91.508 2.148 91.612 168.492 ;
     RECT  91.612 2.418 91.804 168.222 ;
     RECT  91.804 89.76 91.865 90.888 ;
     RECT  91.804 139.008 92.045 143.736 ;
     RECT  91.865 89.76 92.225 90.648 ;
     RECT  91.804 42.624 92.585 47.064 ;
     RECT  92.225 90.624 92.765 90.648 ;
     RECT  91.804 52.944 92.78 57.192 ;
     RECT  91.804 125.904 92.797 125.976 ;
     RECT  92.78 52.944 92.828 57.528 ;
     RECT  92.828 52.896 92.867 57.528 ;
     RECT  92.797 125.904 92.869 126.312 ;
     RECT  91.804 50.16 92.905 50.184 ;
     RECT  91.804 130.848 92.909 132.408 ;
     RECT  91.804 81.456 92.945 88.488 ;
     RECT  92.869 125.184 93.049 126.312 ;
     RECT  92.909 130.848 93.049 132.216 ;
     RECT  92.905 50.16 93.053 50.712 ;
     RECT  92.945 87.984 93.089 88.488 ;
     RECT  93.049 125.184 93.121 126.456 ;
     RECT  91.804 96 93.265 100.584 ;
     RECT  91.804 51.888 93.373 51.912 ;
     RECT  92.867 52.896 93.373 57.192 ;
     RECT  92.945 81.456 93.373 86.808 ;
     RECT  93.121 125.184 93.397 126.984 ;
     RECT  91.804 38.736 93.404 41.4 ;
     RECT  92.585 42.624 93.404 46.584 ;
     RECT  93.265 96 93.445 100.872 ;
     RECT  93.397 125.184 93.445 127.128 ;
     RECT  93.397 129.024 93.445 129.048 ;
     RECT  93.445 125.184 93.661 129.048 ;
     RECT  93.373 47.808 93.692 47.832 ;
     RECT  93.445 78 93.733 78.024 ;
     RECT  92.045 139.248 93.733 143.736 ;
     RECT  93.692 47.808 93.797 47.88 ;
     RECT  91.804 65.712 93.829 65.736 ;
     RECT  93.373 80.88 93.913 86.808 ;
     RECT  93.089 87.984 93.913 88.392 ;
     RECT  93.661 125.184 93.925 129.432 ;
     RECT  93.049 130.56 93.925 132.216 ;
     RECT  93.373 51.888 93.98 57.192 ;
     RECT  93.404 38.736 93.985 46.584 ;
     RECT  93.985 38.16 94.021 46.584 ;
     RECT  93.98 51.888 94.021 57.576 ;
     RECT  93.553 89.52 94.057 89.544 ;
     RECT  93.589 50.736 94.069 50.76 ;
     RECT  94.021 51.888 94.069 57.912 ;
     RECT  94.021 37.872 94.208 46.584 ;
     RECT  93.797 47.808 94.208 48.216 ;
     RECT  94.069 50.736 94.208 57.912 ;
     RECT  93.829 65.712 94.208 66.12 ;
     RECT  93.733 78 94.208 78.264 ;
     RECT  93.913 80.88 94.208 88.392 ;
     RECT  94.057 89.52 94.208 89.976 ;
     RECT  93.445 95.376 94.208 100.872 ;
     RECT  91.804 103.776 94.208 103.8 ;
     RECT  93.925 125.184 94.208 132.216 ;
     RECT  93.733 139.248 94.208 143.832 ;
     RECT  91.804 147.072 94.208 147.24 ;
     RECT  94.208 2.148 94.312 168.492 ;
     RECT  94.312 2.418 94.504 168.222 ;
     RECT  94.504 37.872 94.601 45.192 ;
     RECT  94.601 37.872 94.961 45.048 ;
     RECT  94.504 124.704 94.997 129.816 ;
     RECT  94.504 80.304 95.033 88.152 ;
     RECT  94.997 124.704 95.123 129.432 ;
     RECT  95.123 129.408 95.171 129.432 ;
     RECT  94.504 140.208 95.497 144.312 ;
     RECT  94.504 138.24 95.509 139.128 ;
     RECT  95.497 140.112 95.509 144.312 ;
     RECT  95.123 124.704 95.708 128.328 ;
     RECT  94.504 51.648 95.749 58.152 ;
     RECT  95.033 80.304 95.749 87.384 ;
     RECT  95.509 138.24 95.749 144.312 ;
     RECT  95.749 80.112 95.795 87.384 ;
     RECT  95.708 124.656 95.795 128.328 ;
     RECT  95.795 80.112 95.843 80.376 ;
     RECT  95.749 138.192 95.843 144.36 ;
     RECT  94.961 37.872 95.861 44.616 ;
     RECT  95.795 124.704 95.861 128.328 ;
     RECT  95.843 80.112 95.891 80.328 ;
     RECT  95.861 37.872 95.933 44.376 ;
     RECT  95.749 51.648 95.933 58.248 ;
     RECT  95.891 80.304 95.933 80.328 ;
     RECT  94.504 95.376 95.933 102.12 ;
     RECT  95.861 124.752 95.933 128.328 ;
     RECT  95.843 138.24 95.933 144.36 ;
     RECT  95.933 52.56 96.227 58.248 ;
     RECT  95.795 81.36 96.227 87.384 ;
     RECT  95.933 96.336 96.227 102.072 ;
     RECT  95.933 138.96 96.227 144.36 ;
     RECT  95.933 38.736 96.275 44.184 ;
     RECT  96.227 52.56 96.275 57.72 ;
     RECT  96.227 81.36 96.275 87.288 ;
     RECT  96.227 96.336 96.275 101.592 ;
     RECT  95.933 125.424 96.275 128.28 ;
     RECT  96.275 38.736 96.323 43.944 ;
     RECT  96.275 81.36 96.323 86.664 ;
     RECT  96.275 96.336 96.323 101.496 ;
     RECT  96.275 125.424 96.323 127.704 ;
     RECT  96.227 138.96 96.323 144.264 ;
     RECT  96.275 52.56 96.337 57.624 ;
     RECT  96.323 125.424 97.441 127.032 ;
     RECT  96.323 38.736 98.22 43.224 ;
     RECT  96.337 52.56 98.22 57.048 ;
     RECT  96.323 81.36 98.22 85.848 ;
     RECT  96.323 96.336 98.22 100.824 ;
     RECT  97.441 125.136 98.22 127.032 ;
     RECT  96.323 138.96 98.22 143.448 ;
     RECT  98.22 97.296 98.273 97.32 ;
    LAYER M5 ;
     RECT  2.4 2.137 2.52 2.151 ;
     RECT  5.1 2.137 5.22 2.151 ;
     RECT  7.8 2.137 7.92 2.151 ;
     RECT  10.5 2.137 10.62 2.151 ;
     RECT  13.2 2.137 13.32 2.151 ;
     RECT  15.9 2.137 16.02 2.151 ;
     RECT  18.6 2.137 18.72 2.151 ;
     RECT  21.3 2.137 21.42 2.151 ;
     RECT  24 2.137 24.12 2.151 ;
     RECT  26.7 2.137 26.82 2.151 ;
     RECT  29.4 2.137 29.52 2.151 ;
     RECT  32.1 2.137 32.22 2.151 ;
     RECT  34.8 2.137 34.92 2.151 ;
     RECT  37.5 2.137 37.62 2.151 ;
     RECT  40.2 2.137 40.32 2.151 ;
     RECT  42.9 2.137 43.02 2.151 ;
     RECT  45.6 2.137 45.72 2.151 ;
     RECT  48.3 2.137 48.42 2.151 ;
     RECT  51 2.137 51.12 2.151 ;
     RECT  53.7 2.137 53.82 2.151 ;
     RECT  56.4 2.137 56.52 2.151 ;
     RECT  59.1 2.137 59.22 2.151 ;
     RECT  61.8 2.137 61.92 2.151 ;
     RECT  64.5 2.137 64.62 2.151 ;
     RECT  67.2 2.137 67.32 2.151 ;
     RECT  69.9 2.137 70.02 2.151 ;
     RECT  72.6 2.137 72.72 2.151 ;
     RECT  75.3 2.137 75.42 2.151 ;
     RECT  78 2.137 78.12 2.151 ;
     RECT  80.7 2.137 80.82 2.151 ;
     RECT  83.4 2.137 83.52 2.151 ;
     RECT  86.1 2.137 86.22 2.151 ;
     RECT  88.8 2.137 88.92 2.151 ;
     RECT  91.5 2.137 91.62 2.151 ;
     RECT  94.2 2.137 94.32 2.151 ;
     RECT  2.4 2.151 2.712 32.341 ;
     RECT  2.4 32.341 3.48 33.347 ;
     RECT  7.8 2.151 8.112 34.741 ;
     RECT  2.4 33.347 2.712 36.085 ;
     RECT  5.1 2.151 5.412 36.133 ;
     RECT  2.304 36.085 2.712 36.275 ;
     RECT  42.9 2.151 43.212 36.469 ;
     RECT  42.624 36.469 43.212 36.757 ;
     RECT  94.2 2.151 94.512 37.957 ;
     RECT  94.08 37.957 94.512 38.101 ;
     RECT  95.76 38.005 95.784 38.101 ;
     RECT  94.08 38.101 95.784 38.149 ;
     RECT  91.5 2.151 91.812 39.301 ;
     RECT  42.336 36.757 43.212 39.349 ;
     RECT  42.096 39.349 43.212 39.445 ;
     RECT  94.08 38.149 95.832 39.877 ;
     RECT  92.88 39.205 92.904 39.923 ;
     RECT  94.08 39.877 96.312 40.163 ;
     RECT  40.2 2.151 40.512 40.549 ;
     RECT  91.392 39.301 91.812 40.597 ;
     RECT  88.8 2.151 89.112 40.837 ;
     RECT  64.5 2.151 64.812 40.981 ;
     RECT  39.6 40.549 40.512 41.029 ;
     RECT  94.2 40.163 96.312 41.557 ;
     RECT  75.3 2.151 75.612 41.605 ;
     RECT  90.528 40.597 91.812 41.651 ;
     RECT  93.84 41.557 96.312 41.797 ;
     RECT  88.8 40.837 89.208 42.565 ;
     RECT  91.5 41.651 91.812 42.613 ;
     RECT  93.456 41.797 96.312 42.613 ;
     RECT  90.288 41.797 90.312 42.661 ;
     RECT  91.5 42.613 96.312 42.661 ;
     RECT  4.464 36.133 5.412 42.707 ;
     RECT  90.288 42.661 96.312 42.803 ;
     RECT  93.744 42.803 96.312 42.947 ;
     RECT  75.168 41.605 75.612 43.091 ;
     RECT  6.384 41.269 6.408 43.331 ;
     RECT  95.568 42.947 96.312 43.379 ;
     RECT  90.288 42.803 92.664 43.427 ;
     RECT  88.8 42.565 89.256 43.669 ;
     RECT  95.616 43.379 96.312 43.955 ;
     RECT  7.44 34.741 8.112 44.099 ;
     RECT  95.616 43.955 96.264 44.195 ;
     RECT  2.4 36.275 2.712 44.389 ;
     RECT  91.5 43.427 91.812 44.437 ;
     RECT  95.616 44.195 95.64 44.483 ;
     RECT  0.144 44.629 0.168 44.771 ;
     RECT  2.4 44.389 3.288 44.963 ;
     RECT  93.744 42.947 94.512 44.965 ;
     RECT  90.288 43.427 90.312 45.827 ;
     RECT  42.048 39.445 43.212 46.211 ;
     RECT  42.096 46.211 43.212 46.787 ;
     RECT  79.488 40.885 79.512 46.787 ;
     RECT  88.8 43.669 89.304 46.981 ;
     RECT  88.8 46.981 89.4 47.171 ;
     RECT  91.5 44.437 92.184 50.195 ;
     RECT  93.6 44.965 94.512 50.677 ;
     RECT  39.6 41.029 40.632 51.395 ;
     RECT  91.5 50.195 91.812 51.877 ;
     RECT  92.928 50.677 94.512 51.877 ;
     RECT  95.76 51.781 95.784 52.021 ;
     RECT  95.76 52.021 95.832 52.309 ;
     RECT  91.5 51.877 94.512 52.405 ;
     RECT  88.8 47.171 89.256 52.691 ;
     RECT  95.76 52.309 95.88 52.693 ;
     RECT  91.5 52.405 94.68 52.933 ;
     RECT  95.76 52.693 96.312 52.933 ;
     RECT  91.5 52.933 96.312 53.075 ;
     RECT  88.8 52.691 89.208 53.123 ;
     RECT  95.568 53.075 96.312 53.603 ;
     RECT  95.568 53.603 95.64 53.747 ;
     RECT  91.5 53.075 94.512 53.795 ;
     RECT  95.568 53.747 95.592 53.891 ;
     RECT  91.5 53.795 91.812 54.085 ;
     RECT  92.928 53.795 94.512 54.085 ;
     RECT  92.928 54.085 95.208 54.467 ;
     RECT  90.576 54.085 91.812 54.611 ;
     RECT  92.928 54.467 95.16 55.043 ;
     RECT  95.712 56.005 95.736 56.149 ;
     RECT  92.928 55.043 94.512 56.293 ;
     RECT  95.664 56.149 95.736 56.293 ;
     RECT  95.616 56.293 95.736 56.437 ;
     RECT  91.5 54.611 91.812 56.869 ;
     RECT  92.832 56.293 94.512 56.869 ;
     RECT  91.5 56.869 94.512 57.107 ;
     RECT  95.616 56.437 96.312 57.155 ;
     RECT  91.5 57.107 92.856 57.539 ;
     RECT  95.712 57.155 96.312 57.635 ;
     RECT  96.192 57.635 96.264 57.731 ;
     RECT  96.192 57.731 96.216 58.259 ;
     RECT  42.144 46.787 43.212 64.837 ;
     RECT  64.5 40.981 65.208 65.701 ;
     RECT  78 2.151 78.312 66.085 ;
     RECT  93.84 57.107 94.512 66.131 ;
     RECT  78 66.085 79.032 67.859 ;
     RECT  78 67.859 78.648 70.163 ;
     RECT  15.9 2.151 16.212 70.261 ;
     RECT  78 70.163 78.312 70.645 ;
     RECT  77.472 70.645 78.312 72.995 ;
     RECT  75.3 43.091 75.612 73.285 ;
     RECT  2.4 44.963 2.712 74.581 ;
     RECT  5.1 42.707 5.412 74.629 ;
     RECT  2.4 74.581 3.528 74.771 ;
     RECT  15.552 70.261 16.212 74.963 ;
     RECT  7.68 44.099 8.112 75.157 ;
     RECT  5.1 74.629 5.544 75.827 ;
     RECT  2.4 74.771 3.48 75.875 ;
     RECT  6.96 75.157 8.112 76.355 ;
     RECT  5.1 75.827 5.412 76.357 ;
     RECT  83.4 2.151 83.712 76.741 ;
     RECT  7.68 76.355 8.112 76.787 ;
     RECT  2.4 75.875 2.712 77.125 ;
     RECT  4.416 76.357 5.412 77.845 ;
     RECT  7.8 76.787 8.112 78.037 ;
     RECT  64.5 65.701 65.832 78.131 ;
     RECT  94.032 66.131 94.512 78.229 ;
     RECT  4.416 77.845 5.688 78.707 ;
     RECT  2.4 77.125 3.288 78.755 ;
     RECT  6.912 78.037 8.112 79.283 ;
     RECT  95.856 80.101 95.88 80.341 ;
     RECT  95.808 80.341 95.88 80.917 ;
     RECT  93.744 78.229 94.512 81.205 ;
     RECT  95.52 80.917 95.88 81.205 ;
     RECT  93.744 81.205 95.88 82.213 ;
     RECT  90.288 56.917 90.312 82.691 ;
     RECT  93.744 82.213 96.312 82.691 ;
     RECT  88.8 53.123 89.112 82.693 ;
     RECT  91.5 57.539 92.712 82.789 ;
     RECT  93.744 82.691 94.632 82.789 ;
     RECT  95.616 82.691 96.312 83.267 ;
     RECT  91.5 82.789 94.632 83.315 ;
     RECT  64.5 78.131 65.352 83.461 ;
     RECT  42.144 64.837 43.32 83.557 ;
     RECT  37.5 2.151 37.812 83.749 ;
     RECT  69.9 2.151 70.212 83.749 ;
     RECT  75.3 73.285 76.248 83.891 ;
     RECT  53.7 2.151 54.012 84.037 ;
     RECT  69.9 83.749 70.824 84.083 ;
     RECT  40.08 51.395 40.632 84.085 ;
     RECT  53.7 84.037 54.744 84.179 ;
     RECT  88.8 82.693 89.88 84.179 ;
     RECT  41.76 83.557 43.32 84.371 ;
     RECT  91.5 83.315 94.512 84.467 ;
     RECT  95.616 83.267 95.736 84.517 ;
     RECT  82.896 76.741 83.712 84.563 ;
     RECT  91.5 84.467 92.664 84.853 ;
     RECT  95.568 84.517 95.736 85.381 ;
     RECT  7.8 79.283 8.112 85.429 ;
     RECT  88.8 84.179 89.448 85.429 ;
     RECT  91.392 84.853 92.664 85.477 ;
     RECT  93.744 84.467 94.512 85.477 ;
     RECT  91.392 85.477 94.512 85.523 ;
     RECT  95.568 85.381 96.312 85.525 ;
     RECT  88.8 85.429 89.496 86.005 ;
     RECT  93.456 85.523 94.512 86.243 ;
     RECT  93.744 86.243 94.512 86.341 ;
     RECT  95.52 85.525 96.312 86.341 ;
     RECT  7.8 85.429 8.232 86.675 ;
     RECT  93.744 86.341 96.312 86.675 ;
     RECT  88.8 86.005 90.072 86.771 ;
     RECT  93.744 86.675 96.264 87.251 ;
     RECT  96.192 87.251 96.264 87.299 ;
     RECT  4.416 78.707 5.412 87.347 ;
     RECT  93.744 87.251 95.112 87.347 ;
     RECT  96.192 87.299 96.216 87.395 ;
     RECT  2.4 78.755 2.712 87.685 ;
     RECT  5.1 87.347 5.412 87.733 ;
     RECT  2.4 87.685 3.432 87.925 ;
     RECT  2.304 87.925 3.432 88.115 ;
     RECT  7.8 86.675 8.112 88.885 ;
     RECT  2.4 88.115 3.432 88.979 ;
     RECT  39.744 84.085 40.632 89.269 ;
     RECT  7.8 88.885 8.232 89.317 ;
     RECT  93.744 87.347 94.512 89.555 ;
     RECT  39.744 89.269 40.68 89.699 ;
     RECT  78 72.995 78.312 90.037 ;
     RECT  78 90.037 78.696 90.179 ;
     RECT  20.208 70.549 20.232 91.717 ;
     RECT  20.064 91.717 20.232 91.763 ;
     RECT  21.3 2.151 21.612 91.813 ;
     RECT  5.1 87.733 6.072 92.723 ;
     RECT  7.68 89.317 8.232 93.059 ;
     RECT  37.5 83.749 38.472 93.061 ;
     RECT  37.5 93.061 38.568 93.875 ;
     RECT  94.08 89.555 94.512 95.365 ;
     RECT  95.808 95.509 95.832 95.701 ;
     RECT  39.744 89.699 40.632 96.037 ;
     RECT  93.456 95.365 94.512 96.181 ;
     RECT  95.76 95.701 95.832 96.181 ;
     RECT  93.456 96.181 95.832 96.229 ;
     RECT  37.5 93.875 38.472 96.277 ;
     RECT  92.88 96.229 95.832 96.277 ;
     RECT  92.88 96.277 95.88 96.371 ;
     RECT  88.8 86.771 89.448 96.419 ;
     RECT  94.2 96.371 95.88 96.659 ;
     RECT  39.696 96.037 40.632 96.947 ;
     RECT  92.88 96.371 92.904 96.947 ;
     RECT  94.2 96.659 95.544 96.947 ;
     RECT  95.52 96.947 95.544 97.091 ;
     RECT  96.288 98.197 96.312 98.533 ;
     RECT  94.2 96.947 94.512 98.581 ;
     RECT  95.856 98.533 96.312 98.581 ;
     RECT  94.2 98.581 96.312 98.675 ;
     RECT  94.2 98.675 95.88 99.107 ;
     RECT  94.2 99.107 95.16 99.299 ;
     RECT  91.392 85.523 91.812 99.491 ;
     RECT  94.2 99.299 95.112 99.539 ;
     RECT  21.3 91.813 22.344 99.779 ;
     RECT  88.8 96.419 89.112 100.261 ;
     RECT  96.288 100.069 96.312 100.357 ;
     RECT  94.2 99.539 94.512 100.789 ;
     RECT  95.712 100.357 96.312 100.789 ;
     RECT  94.2 100.789 96.312 101.507 ;
     RECT  94.2 101.507 96.264 101.555 ;
     RECT  96.192 101.555 96.264 101.603 ;
     RECT  96.192 101.603 96.216 102.083 ;
     RECT  94.2 101.555 95.16 102.131 ;
     RECT  7.8 93.059 8.232 104.821 ;
     RECT  64.5 83.461 65.448 105.491 ;
     RECT  64.5 105.491 64.812 106.549 ;
     RECT  64.5 106.549 65.448 107.795 ;
     RECT  88.8 100.261 89.64 107.795 ;
     RECT  41.76 84.371 43.212 108.517 ;
     RECT  37.392 96.277 38.472 113.797 ;
     RECT  41.76 108.517 43.32 114.035 ;
     RECT  40.2 96.947 40.632 114.517 ;
     RECT  88.8 107.795 89.448 116.339 ;
     RECT  86.1 2.151 86.412 117.397 ;
     RECT  37.152 113.797 38.472 118.069 ;
     RECT  20.064 91.763 20.088 118.595 ;
     RECT  7.056 104.821 8.232 119.171 ;
     RECT  7.056 119.171 8.112 119.653 ;
     RECT  21.3 99.779 22.152 119.653 ;
     RECT  5.1 92.723 5.412 120.229 ;
     RECT  6.864 119.653 8.112 120.229 ;
     RECT  40.2 114.517 41.016 120.757 ;
     RECT  42.144 114.035 43.32 120.757 ;
     RECT  4.56 120.229 8.112 121.379 ;
     RECT  34.8 2.151 35.112 121.381 ;
     RECT  5.1 121.379 8.112 122.003 ;
     RECT  40.2 120.757 43.32 122.147 ;
     RECT  72.6 2.151 72.912 122.629 ;
     RECT  56.4 2.151 56.712 122.917 ;
     RECT  34.8 121.381 35.352 123.013 ;
     RECT  36.432 118.069 38.472 123.013 ;
     RECT  5.1 122.003 5.412 123.061 ;
     RECT  20.4 119.653 22.152 123.157 ;
     RECT  20.208 123.157 22.152 123.203 ;
     RECT  7.056 122.003 8.112 123.349 ;
     RECT  42.72 122.147 43.32 123.397 ;
     RECT  72.6 122.629 73.656 123.731 ;
     RECT  42.672 123.397 43.32 124.165 ;
     RECT  75.3 83.891 75.612 124.213 ;
     RECT  94.2 102.131 94.512 124.693 ;
     RECT  95.76 124.645 95.784 124.693 ;
     RECT  40.2 122.147 41.304 124.789 ;
     RECT  42.336 124.165 43.32 124.789 ;
     RECT  94.2 124.693 95.784 124.789 ;
     RECT  75.168 124.213 75.72 125.365 ;
     RECT  94.2 124.789 95.832 125.365 ;
     RECT  72.6 123.731 72.912 125.413 ;
     RECT  74.304 125.365 75.72 125.413 ;
     RECT  7.056 123.349 8.232 125.459 ;
     RECT  72.6 125.413 75.72 125.459 ;
     RECT  94.08 125.365 95.832 125.749 ;
     RECT  94.08 125.749 95.88 125.797 ;
     RECT  91.5 99.491 91.812 125.941 ;
     RECT  75.3 125.459 75.72 125.989 ;
     RECT  40.2 124.789 43.32 126.035 ;
     RECT  4.656 123.061 5.412 126.131 ;
     RECT  93.456 125.797 95.88 126.277 ;
     RECT  93.408 126.277 95.88 126.323 ;
     RECT  72.6 125.459 74.328 126.419 ;
     RECT  78 90.179 78.312 126.421 ;
     RECT  72.6 126.419 73.8 126.611 ;
     RECT  90.432 125.941 91.812 126.611 ;
     RECT  88.8 116.339 89.304 126.659 ;
     RECT  90.432 126.611 90.456 126.659 ;
     RECT  63.216 108.133 63.24 127.091 ;
     RECT  34.8 123.013 38.472 127.139 ;
     RECT  55.728 122.917 56.712 127.139 ;
     RECT  93.408 126.323 95.112 127.139 ;
     RECT  37.152 127.139 38.472 127.333 ;
     RECT  20.208 123.203 20.232 127.379 ;
     RECT  40.2 126.035 41.016 127.381 ;
     RECT  93.456 127.139 95.112 127.381 ;
     RECT  34.8 127.139 36.168 127.715 ;
     RECT  96.192 126.421 96.312 127.715 ;
     RECT  96.192 127.715 96.264 127.907 ;
     RECT  96.24 127.907 96.264 128.291 ;
     RECT  93.456 127.381 95.16 129.013 ;
     RECT  34.8 127.715 35.112 129.253 ;
     RECT  36.144 127.715 36.168 129.253 ;
     RECT  75.3 125.989 75.768 129.397 ;
     RECT  93.408 129.013 95.16 129.443 ;
     RECT  42 126.035 43.32 129.491 ;
     RECT  34.8 129.253 36.168 129.781 ;
     RECT  37.152 127.333 38.568 129.781 ;
     RECT  34.8 129.781 38.568 129.923 ;
     RECT  39.888 127.381 41.016 129.923 ;
     RECT  4.992 126.131 5.412 129.925 ;
     RECT  34.8 129.923 35.88 130.019 ;
     RECT  4.272 129.925 5.412 130.547 ;
     RECT  7.8 125.459 8.232 130.595 ;
     RECT  77.568 126.421 78.312 130.789 ;
     RECT  83.4 84.563 83.712 131.077 ;
     RECT  85.2 117.397 86.412 131.077 ;
     RECT  36.96 129.923 38.568 131.123 ;
     RECT  93.408 129.443 94.512 131.123 ;
     RECT  77.568 130.789 78.696 131.267 ;
     RECT  82.656 131.077 83.712 131.315 ;
     RECT  37.152 131.123 38.568 131.699 ;
     RECT  93.792 131.123 94.512 131.747 ;
     RECT  85.2 131.077 86.664 131.939 ;
     RECT  78 131.267 78.696 132.131 ;
     RECT  42 129.491 43.212 132.515 ;
     RECT  78 132.131 78.312 132.757 ;
     RECT  42.432 132.515 43.212 132.803 ;
     RECT  42.528 132.803 43.212 132.899 ;
     RECT  42.624 132.899 43.212 132.995 ;
     RECT  77.568 132.757 78.312 133.475 ;
     RECT  75.3 129.397 75.816 133.763 ;
     RECT  34.8 130.019 35.592 133.861 ;
     RECT  37.344 131.699 38.568 134.293 ;
     RECT  75.3 133.763 75.768 134.627 ;
     RECT  37.344 134.293 39.048 135.445 ;
     RECT  78 133.475 78.312 135.493 ;
     RECT  37.104 135.445 39.048 135.731 ;
     RECT  34.8 133.861 35.88 137.411 ;
     RECT  94.2 131.747 94.512 138.229 ;
     RECT  95.808 138.181 95.832 138.229 ;
     RECT  37.104 135.731 38.568 138.659 ;
     RECT  94.2 138.229 95.832 138.709 ;
     RECT  40.2 129.923 41.016 138.949 ;
     RECT  85.2 131.939 86.412 138.997 ;
     RECT  91.5 126.611 91.812 138.997 ;
     RECT  94.2 138.709 95.88 139.139 ;
     RECT  85.2 138.997 86.616 139.187 ;
     RECT  95.52 139.139 95.88 139.427 ;
     RECT  91.5 138.997 91.992 139.477 ;
     RECT  95.52 139.427 95.736 139.571 ;
     RECT  86.1 139.187 86.616 139.955 ;
     RECT  77.76 135.493 78.312 140.003 ;
     RECT  91.392 139.477 91.992 140.197 ;
     RECT  39.552 138.949 41.016 140.243 ;
     RECT  88.8 126.659 89.112 140.725 ;
     RECT  94.2 139.139 94.512 141.253 ;
     RECT  95.712 139.571 95.736 141.253 ;
     RECT  40.2 140.243 41.016 141.301 ;
     RECT  94.2 141.253 95.736 141.301 ;
     RECT  93.696 141.301 95.736 141.683 ;
     RECT  91.392 140.197 92.424 141.685 ;
     RECT  91.344 141.685 92.424 141.877 ;
     RECT  94.2 141.683 95.736 141.971 ;
     RECT  95.52 141.971 95.736 141.973 ;
     RECT  91.344 141.877 92.664 142.213 ;
     RECT  95.52 141.973 96.312 142.307 ;
     RECT  88.8 140.725 89.544 142.355 ;
     RECT  39.744 141.301 41.016 142.547 ;
     RECT  95.712 142.307 96.312 142.547 ;
     RECT  90.576 142.213 92.664 142.739 ;
     RECT  94.2 141.971 94.512 142.789 ;
     RECT  21.3 123.203 22.152 142.979 ;
     RECT  90.576 142.739 91.812 143.123 ;
     RECT  93.744 142.789 94.512 143.317 ;
     RECT  93.744 143.317 94.92 143.843 ;
     RECT  96.192 142.547 96.312 144.275 ;
     RECT  94.2 143.843 94.92 144.323 ;
     RECT  37.248 138.659 38.568 144.325 ;
     RECT  96.192 144.275 96.216 144.371 ;
     RECT  37.248 144.325 38.664 149.317 ;
     RECT  37.2 149.317 38.664 163.811 ;
     RECT  37.2 163.811 38.472 165.635 ;
     RECT  37.2 165.635 38.136 165.923 ;
     RECT  37.5 165.923 38.136 166.933 ;
     RECT  37.5 166.933 38.232 166.981 ;
     RECT  37.5 166.981 38.424 168.179 ;
     RECT  2.4 88.979 2.712 168.489 ;
     RECT  5.1 130.547 5.412 168.489 ;
     RECT  7.8 130.595 8.112 168.489 ;
     RECT  10.5 2.151 10.812 168.489 ;
     RECT  13.2 2.151 13.512 168.489 ;
     RECT  15.9 74.963 16.212 168.489 ;
     RECT  18.6 2.151 18.912 168.489 ;
     RECT  21.3 142.979 21.612 168.489 ;
     RECT  24 2.151 24.312 168.489 ;
     RECT  26.7 2.151 27.012 168.489 ;
     RECT  29.4 2.151 29.712 168.489 ;
     RECT  32.1 2.151 32.412 168.489 ;
     RECT  34.8 137.411 35.112 168.489 ;
     RECT  40.2 142.547 40.512 168.489 ;
     RECT  42.9 132.995 43.212 168.489 ;
     RECT  45.6 2.151 45.912 168.489 ;
     RECT  48.3 2.151 48.612 168.489 ;
     RECT  51 2.151 51.312 168.489 ;
     RECT  53.7 84.179 54.012 168.489 ;
     RECT  56.4 127.139 56.712 168.489 ;
     RECT  59.1 2.151 59.412 168.489 ;
     RECT  61.8 2.151 62.112 168.489 ;
     RECT  64.5 107.795 64.812 168.489 ;
     RECT  67.2 2.151 67.512 168.489 ;
     RECT  69.9 84.083 70.212 168.489 ;
     RECT  72.6 126.611 72.912 168.489 ;
     RECT  75.3 134.627 75.612 168.489 ;
     RECT  78 140.003 78.312 168.489 ;
     RECT  80.7 2.151 81.012 168.489 ;
     RECT  83.4 131.315 83.712 168.489 ;
     RECT  86.1 139.955 86.412 168.489 ;
     RECT  88.8 142.355 89.112 168.489 ;
     RECT  91.5 143.123 91.812 168.489 ;
     RECT  94.2 144.323 94.512 168.489 ;
     RECT  2.4 168.489 2.52 168.503 ;
     RECT  5.1 168.489 5.22 168.503 ;
     RECT  7.8 168.489 7.92 168.503 ;
     RECT  10.5 168.489 10.62 168.503 ;
     RECT  13.2 168.489 13.32 168.503 ;
     RECT  15.9 168.489 16.02 168.503 ;
     RECT  18.6 168.489 18.72 168.503 ;
     RECT  21.3 168.489 21.42 168.503 ;
     RECT  24 168.489 24.12 168.503 ;
     RECT  26.7 168.489 26.82 168.503 ;
     RECT  29.4 168.489 29.52 168.503 ;
     RECT  32.1 168.489 32.22 168.503 ;
     RECT  34.8 168.489 34.92 168.503 ;
     RECT  37.5 168.179 38.136 168.503 ;
     RECT  40.2 168.489 40.32 168.503 ;
     RECT  42.9 168.489 43.02 168.503 ;
     RECT  45.6 168.489 45.72 168.503 ;
     RECT  48.3 168.489 48.42 168.503 ;
     RECT  51 168.489 51.12 168.503 ;
     RECT  53.7 168.489 53.82 168.503 ;
     RECT  56.4 168.489 56.52 168.503 ;
     RECT  59.1 168.489 59.22 168.503 ;
     RECT  61.8 168.489 61.92 168.503 ;
     RECT  64.5 168.489 64.62 168.503 ;
     RECT  67.2 168.489 67.32 168.503 ;
     RECT  69.9 168.489 70.02 168.503 ;
     RECT  72.6 168.489 72.72 168.503 ;
     RECT  75.3 168.489 75.42 168.503 ;
     RECT  78 168.489 78.12 168.503 ;
     RECT  80.7 168.489 80.82 168.503 ;
     RECT  83.4 168.489 83.52 168.503 ;
     RECT  86.1 168.489 86.22 168.503 ;
     RECT  88.8 168.489 88.92 168.503 ;
     RECT  91.5 168.489 91.62 168.503 ;
     RECT  94.2 168.489 94.32 168.503 ;
     RECT  37.968 168.503 38.136 170.435 ;
     RECT  37.968 170.435 37.992 170.531 ;
  END
END qfd_landh0d8s_174_EW_98x171
END LIBRARY
